# SINH BOI run_workspace/mcu/innovus/scripts/make_1x_lef.py sram - KHONG sua tay.
# = srambank_128x4x20_6t122.lef.4x.fixed.lef chia 4 (ban 4x da chay sach DRC).
VERSION 5.8 ;
BUSBITCHARS "[]" ; 
DIVIDERCHAR "/" ; 


PROPERTYDEFINITIONS 
  MACRO CatenaDesignType STRING ; 
END PROPERTYDEFINITIONS 


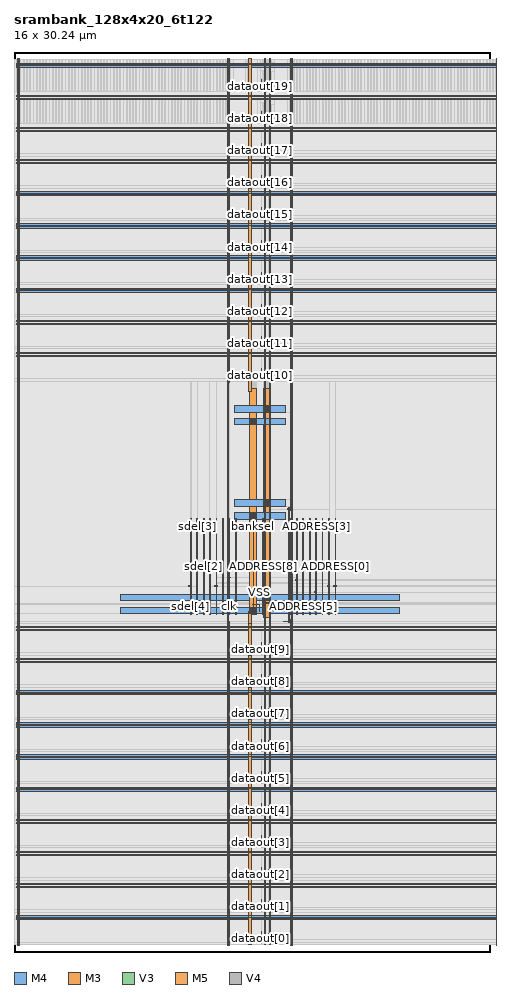
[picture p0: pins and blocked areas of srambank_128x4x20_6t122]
MACRO srambank_128x4x20_6t122 
  CLASS BLOCK ; 
  ORIGIN 0 0 ; 
  FOREIGN srambank_128x4x20_6t122 0 0 ; 
  SIZE 16 BY 30.24 ; 
  SYMMETRY X Y ; 
  SITE asap7sc7p5t ; 
  PIN VDD 
    DIRECTION INOUT ; 
    USE POWER ; 
    PORT 
      LAYER M4 ; 
        RECT 0.094 1.172 16.442 1.22 ; 
        RECT 0.094 2.252 16.442 2.3 ; 
        RECT 0.094 3.332 16.442 3.38 ; 
        RECT 0.094 4.412 16.442 4.46 ; 
        RECT 0.094 5.492 16.442 5.54 ; 
        RECT 0.094 6.572 16.442 6.62 ; 
        RECT 0.094 7.652 16.442 7.7 ; 
        RECT 0.094 8.732 16.442 8.78 ; 
        RECT 0.094 9.812 16.442 9.86 ; 
        RECT 0.094 10.892 16.442 10.94 ; 
        RECT 3.564 11.373 12.96 11.589 ; 
        RECT 9.197 14.877 9.338 14.901 ; 
        RECT 9.066 11.093 9.329 11.117 ; 
        RECT 7.398 14.541 9.126 14.757 ; 
        RECT 7.398 17.709 9.126 17.925 ; 
        RECT 0.094 20.099 16.442 20.147 ; 
        RECT 0.094 21.179 16.442 21.227 ; 
        RECT 0.094 22.259 16.442 22.307 ; 
        RECT 0.094 23.339 16.442 23.387 ; 
        RECT 0.094 24.419 16.442 24.467 ; 
        RECT 0.094 25.499 16.442 25.547 ; 
        RECT 0.094 26.579 16.442 26.627 ; 
        RECT 0.094 27.659 16.442 27.707 ; 
        RECT 0.094 28.739 16.442 28.787 ; 
        RECT 0.094 29.819 16.442 29.867 ; 
      LAYER M3 ; 
        RECT 16.394 0.217 16.412 1.377 ; 
        RECT 9.284 0.217 9.302 1.376 ; 
        RECT 7.88 0.257 7.97 1.371 ; 
        RECT 7.232 0.217 7.25 1.376 ; 
        RECT 0.122 0.217 0.14 1.377 ; 
        RECT 16.394 1.297 16.412 2.457 ; 
        RECT 9.284 1.297 9.302 2.456 ; 
        RECT 7.88 1.337 7.97 2.451 ; 
        RECT 7.232 1.297 7.25 2.456 ; 
        RECT 0.122 1.297 0.14 2.457 ; 
        RECT 16.394 2.377 16.412 3.537 ; 
        RECT 9.284 2.377 9.302 3.536 ; 
        RECT 7.88 2.417 7.97 3.531 ; 
        RECT 7.232 2.377 7.25 3.536 ; 
        RECT 0.122 2.377 0.14 3.537 ; 
        RECT 16.394 3.457 16.412 4.617 ; 
        RECT 9.284 3.457 9.302 4.616 ; 
        RECT 7.88 3.497 7.97 4.611 ; 
        RECT 7.232 3.457 7.25 4.616 ; 
        RECT 0.122 3.457 0.14 4.617 ; 
        RECT 16.394 4.537 16.412 5.697 ; 
        RECT 9.284 4.537 9.302 5.696 ; 
        RECT 7.88 4.577 7.97 5.691 ; 
        RECT 7.232 4.537 7.25 5.696 ; 
        RECT 0.122 4.537 0.14 5.697 ; 
        RECT 16.394 5.617 16.412 6.777 ; 
        RECT 9.284 5.617 9.302 6.776 ; 
        RECT 7.88 5.657 7.97 6.771 ; 
        RECT 7.232 5.617 7.25 6.776 ; 
        RECT 0.122 5.617 0.14 6.777 ; 
        RECT 16.394 6.697 16.412 7.857 ; 
        RECT 9.284 6.697 9.302 7.856 ; 
        RECT 7.88 6.737 7.97 7.851 ; 
        RECT 7.232 6.697 7.25 7.856 ; 
        RECT 0.122 6.697 0.14 7.857 ; 
        RECT 16.394 7.777 16.412 8.937 ; 
        RECT 9.284 7.777 9.302 8.936 ; 
        RECT 7.88 7.817 7.97 8.931 ; 
        RECT 7.232 7.777 7.25 8.936 ; 
        RECT 0.122 7.777 0.14 8.937 ; 
        RECT 16.394 8.857 16.412 10.017 ; 
        RECT 9.284 8.857 9.302 10.016 ; 
        RECT 7.88 8.897 7.97 10.011 ; 
        RECT 7.232 8.857 7.25 10.016 ; 
        RECT 0.122 8.857 0.14 10.017 ; 
        RECT 16.394 9.937 16.412 11.097 ; 
        RECT 9.284 9.937 9.302 11.096 ; 
        RECT 7.88 9.977 7.97 11.091 ; 
        RECT 7.232 9.937 7.25 11.096 ; 
        RECT 0.122 9.937 0.14 11.097 ; 
        RECT 16.389 11.011 16.407 19.218 ; 
        RECT 9.297 14.83 9.315 19.179 ; 
        RECT 9.279 11.044 9.297 11.182 ; 
        RECT 7.911 11.334 8.145 18.917 ; 
        RECT 7.875 18.834 7.965 19.21 ; 
        RECT 7.875 11.05 7.965 11.426 ; 
        RECT 0.117 11.011 0.135 19.218 ; 
        RECT 16.394 19.144 16.412 20.304 ; 
        RECT 9.284 19.144 9.302 20.303 ; 
        RECT 7.88 19.184 7.97 20.298 ; 
        RECT 7.232 19.144 7.25 20.303 ; 
        RECT 0.122 19.144 0.14 20.304 ; 
        RECT 16.394 20.224 16.412 21.384 ; 
        RECT 9.284 20.224 9.302 21.383 ; 
        RECT 7.88 20.264 7.97 21.378 ; 
        RECT 7.232 20.224 7.25 21.383 ; 
        RECT 0.122 20.224 0.14 21.384 ; 
        RECT 16.394 21.304 16.412 22.464 ; 
        RECT 9.284 21.304 9.302 22.463 ; 
        RECT 7.88 21.344 7.97 22.458 ; 
        RECT 7.232 21.304 7.25 22.463 ; 
        RECT 0.122 21.304 0.14 22.464 ; 
        RECT 16.394 22.384 16.412 23.544 ; 
        RECT 9.284 22.384 9.302 23.543 ; 
        RECT 7.88 22.424 7.97 23.538 ; 
        RECT 7.232 22.384 7.25 23.543 ; 
        RECT 0.122 22.384 0.14 23.544 ; 
        RECT 16.394 23.464 16.412 24.624 ; 
        RECT 9.284 23.464 9.302 24.623 ; 
        RECT 7.88 23.504 7.97 24.618 ; 
        RECT 7.232 23.464 7.25 24.623 ; 
        RECT 0.122 23.464 0.14 24.624 ; 
        RECT 16.394 24.544 16.412 25.704 ; 
        RECT 9.284 24.544 9.302 25.703 ; 
        RECT 7.88 24.584 7.97 25.698 ; 
        RECT 7.232 24.544 7.25 25.703 ; 
        RECT 0.122 24.544 0.14 25.704 ; 
        RECT 16.394 25.624 16.412 26.784 ; 
        RECT 9.284 25.624 9.302 26.783 ; 
        RECT 7.88 25.664 7.97 26.778 ; 
        RECT 7.232 25.624 7.25 26.783 ; 
        RECT 0.122 25.624 0.14 26.784 ; 
        RECT 16.394 26.704 16.412 27.864 ; 
        RECT 9.284 26.704 9.302 27.863 ; 
        RECT 7.88 26.744 7.97 27.858 ; 
        RECT 7.232 26.704 7.25 27.863 ; 
        RECT 0.122 26.704 0.14 27.864 ; 
        RECT 16.394 27.784 16.412 28.944 ; 
        RECT 9.284 27.784 9.302 28.943 ; 
        RECT 7.88 27.824 7.97 28.938 ; 
        RECT 7.232 27.784 7.25 28.943 ; 
        RECT 0.122 27.784 0.14 28.944 ; 
        RECT 16.394 28.864 16.412 30.024 ; 
        RECT 9.284 28.864 9.302 30.023 ; 
        RECT 7.88 28.904 7.97 30.018 ; 
        RECT 7.232 28.864 7.25 30.023 ; 
        RECT 0.122 28.864 0.14 30.024 ; 
      LAYER V3 ; 
        RECT 0.122 1.172 0.14 1.22 ; 
        RECT 7.232 1.172 7.25 1.22 ; 
        RECT 7.88 1.172 7.97 1.22 ; 
        RECT 9.284 1.172 9.302 1.22 ; 
        RECT 16.394 1.172 16.412 1.22 ; 
        RECT 0.122 2.252 0.14 2.3 ; 
        RECT 7.232 2.252 7.25 2.3 ; 
        RECT 7.88 2.252 7.97 2.3 ; 
        RECT 9.284 2.252 9.302 2.3 ; 
        RECT 16.394 2.252 16.412 2.3 ; 
        RECT 0.122 3.332 0.14 3.38 ; 
        RECT 7.232 3.332 7.25 3.38 ; 
        RECT 7.88 3.332 7.97 3.38 ; 
        RECT 9.284 3.332 9.302 3.38 ; 
        RECT 16.394 3.332 16.412 3.38 ; 
        RECT 0.122 4.412 0.14 4.46 ; 
        RECT 7.232 4.412 7.25 4.46 ; 
        RECT 7.88 4.412 7.97 4.46 ; 
        RECT 9.284 4.412 9.302 4.46 ; 
        RECT 16.394 4.412 16.412 4.46 ; 
        RECT 0.122 5.492 0.14 5.54 ; 
        RECT 7.232 5.492 7.25 5.54 ; 
        RECT 7.88 5.492 7.97 5.54 ; 
        RECT 9.284 5.492 9.302 5.54 ; 
        RECT 16.394 5.492 16.412 5.54 ; 
        RECT 0.122 6.572 0.14 6.62 ; 
        RECT 7.232 6.572 7.25 6.62 ; 
        RECT 7.88 6.572 7.97 6.62 ; 
        RECT 9.284 6.572 9.302 6.62 ; 
        RECT 16.394 6.572 16.412 6.62 ; 
        RECT 0.122 7.652 0.14 7.7 ; 
        RECT 7.232 7.652 7.25 7.7 ; 
        RECT 7.88 7.652 7.97 7.7 ; 
        RECT 9.284 7.652 9.302 7.7 ; 
        RECT 16.394 7.652 16.412 7.7 ; 
        RECT 0.122 8.732 0.14 8.78 ; 
        RECT 7.232 8.732 7.25 8.78 ; 
        RECT 7.88 8.732 7.97 8.78 ; 
        RECT 9.284 8.732 9.302 8.78 ; 
        RECT 16.394 8.732 16.412 8.78 ; 
        RECT 0.122 9.812 0.14 9.86 ; 
        RECT 7.232 9.812 7.25 9.86 ; 
        RECT 7.88 9.812 7.97 9.86 ; 
        RECT 9.284 9.812 9.302 9.86 ; 
        RECT 16.394 9.812 16.412 9.86 ; 
        RECT 0.122 10.892 0.14 10.94 ; 
        RECT 7.232 10.892 7.25 10.94 ; 
        RECT 7.88 10.892 7.97 10.94 ; 
        RECT 9.284 10.892 9.302 10.94 ; 
        RECT 16.394 10.892 16.412 10.94 ; 
        RECT 7.915 17.709 7.933 17.925 ; 
        RECT 7.915 14.541 7.933 14.757 ; 
        RECT 7.915 11.373 7.933 11.589 ; 
        RECT 7.967 17.709 7.985 17.925 ; 
        RECT 7.967 14.541 7.985 14.757 ; 
        RECT 7.967 11.373 7.985 11.589 ; 
        RECT 8.019 17.709 8.037 17.925 ; 
        RECT 8.019 14.541 8.037 14.757 ; 
        RECT 8.019 11.373 8.037 11.589 ; 
        RECT 8.071 17.709 8.089 17.925 ; 
        RECT 8.071 14.541 8.089 14.757 ; 
        RECT 8.071 11.373 8.089 11.589 ; 
        RECT 8.123 17.709 8.141 17.925 ; 
        RECT 8.123 14.541 8.141 14.757 ; 
        RECT 8.123 11.373 8.141 11.589 ; 
        RECT 9.279 11.093 9.297 11.117 ; 
        RECT 9.297 14.877 9.315 14.901 ; 
        RECT 0.122 20.099 0.14 20.147 ; 
        RECT 7.232 20.099 7.25 20.147 ; 
        RECT 7.88 20.099 7.97 20.147 ; 
        RECT 9.284 20.099 9.302 20.147 ; 
        RECT 16.394 20.099 16.412 20.147 ; 
        RECT 0.122 21.179 0.14 21.227 ; 
        RECT 7.232 21.179 7.25 21.227 ; 
        RECT 7.88 21.179 7.97 21.227 ; 
        RECT 9.284 21.179 9.302 21.227 ; 
        RECT 16.394 21.179 16.412 21.227 ; 
        RECT 0.122 22.259 0.14 22.307 ; 
        RECT 7.232 22.259 7.25 22.307 ; 
        RECT 7.88 22.259 7.97 22.307 ; 
        RECT 9.284 22.259 9.302 22.307 ; 
        RECT 16.394 22.259 16.412 22.307 ; 
        RECT 0.122 23.339 0.14 23.387 ; 
        RECT 7.232 23.339 7.25 23.387 ; 
        RECT 7.88 23.339 7.97 23.387 ; 
        RECT 9.284 23.339 9.302 23.387 ; 
        RECT 16.394 23.339 16.412 23.387 ; 
        RECT 0.122 24.419 0.14 24.467 ; 
        RECT 7.232 24.419 7.25 24.467 ; 
        RECT 7.88 24.419 7.97 24.467 ; 
        RECT 9.284 24.419 9.302 24.467 ; 
        RECT 16.394 24.419 16.412 24.467 ; 
        RECT 0.122 25.499 0.14 25.547 ; 
        RECT 7.232 25.499 7.25 25.547 ; 
        RECT 7.88 25.499 7.97 25.547 ; 
        RECT 9.284 25.499 9.302 25.547 ; 
        RECT 16.394 25.499 16.412 25.547 ; 
        RECT 0.122 26.579 0.14 26.627 ; 
        RECT 7.232 26.579 7.25 26.627 ; 
        RECT 7.88 26.579 7.97 26.627 ; 
        RECT 9.284 26.579 9.302 26.627 ; 
        RECT 16.394 26.579 16.412 26.627 ; 
        RECT 0.122 27.659 0.14 27.707 ; 
        RECT 7.232 27.659 7.25 27.707 ; 
        RECT 7.88 27.659 7.97 27.707 ; 
        RECT 9.284 27.659 9.302 27.707 ; 
        RECT 16.394 27.659 16.412 27.707 ; 
        RECT 0.122 28.739 0.14 28.787 ; 
        RECT 7.232 28.739 7.25 28.787 ; 
        RECT 7.88 28.739 7.97 28.787 ; 
        RECT 9.284 28.739 9.302 28.787 ; 
        RECT 16.394 28.739 16.412 28.787 ; 
        RECT 0.122 29.819 0.14 29.867 ; 
        RECT 7.232 29.819 7.25 29.867 ; 
        RECT 7.88 29.819 7.97 29.867 ; 
        RECT 9.284 29.819 9.302 29.867 ; 
        RECT 16.394 29.819 16.412 29.867 ; 
      LAYER M5 ; 
        RECT 9.216 11.075 9.24 14.919 ; 
      LAYER V4 ; 
        RECT 9.216 14.877 9.24 14.901 ; 
        RECT 9.216 11.373 9.24 11.589 ; 
        RECT 9.216 11.093 9.24 11.117 ; 
    END 
  END VDD 
  PIN VSS 
    DIRECTION INOUT ; 
    USE POWER ; 
    PORT 
      LAYER M4 ; 
        RECT 0.094 1.076 16.437 1.124 ; 
        RECT 0.094 2.156 16.437 2.204 ; 
        RECT 0.094 3.236 16.437 3.284 ; 
        RECT 0.094 4.316 16.437 4.364 ; 
        RECT 0.094 5.396 16.437 5.444 ; 
        RECT 0.094 6.476 16.437 6.524 ; 
        RECT 0.094 7.556 16.437 7.604 ; 
        RECT 0.094 8.636 16.437 8.684 ; 
        RECT 0.094 9.716 16.437 9.764 ; 
        RECT 0.094 10.796 16.437 10.844 ; 
        RECT 3.564 11.805 12.96 12.021 ; 
        RECT 7.398 14.973 9.126 15.189 ; 
        RECT 7.398 18.141 9.126 18.357 ; 
        RECT 0.094 20.003 16.437 20.051 ; 
        RECT 0.094 21.083 16.437 21.131 ; 
        RECT 0.094 22.163 16.437 22.211 ; 
        RECT 0.094 23.243 16.437 23.291 ; 
        RECT 0.094 24.323 16.437 24.371 ; 
        RECT 0.094 25.403 16.437 25.451 ; 
        RECT 0.094 26.483 16.437 26.531 ; 
        RECT 0.094 27.563 16.437 27.611 ; 
        RECT 0.094 28.643 16.437 28.691 ; 
        RECT 0.094 29.723 16.437 29.771 ; 
      LAYER M3 ; 
        RECT 16.358 0.217 16.376 1.377 ; 
        RECT 9.338 0.217 9.356 1.377 ; 
        RECT 8.573 0.253 8.609 1.367 ; 
        RECT 8.42 0.253 8.447 1.367 ; 
        RECT 7.178 0.217 7.196 1.377 ; 
        RECT 0.158 0.217 0.176 1.377 ; 
        RECT 16.358 1.297 16.376 2.457 ; 
        RECT 9.338 1.297 9.356 2.457 ; 
        RECT 8.573 1.333 8.609 2.447 ; 
        RECT 8.42 1.333 8.447 2.447 ; 
        RECT 7.178 1.297 7.196 2.457 ; 
        RECT 0.158 1.297 0.176 2.457 ; 
        RECT 16.358 2.377 16.376 3.537 ; 
        RECT 9.338 2.377 9.356 3.537 ; 
        RECT 8.573 2.413 8.609 3.527 ; 
        RECT 8.42 2.413 8.447 3.527 ; 
        RECT 7.178 2.377 7.196 3.537 ; 
        RECT 0.158 2.377 0.176 3.537 ; 
        RECT 16.358 3.457 16.376 4.617 ; 
        RECT 9.338 3.457 9.356 4.617 ; 
        RECT 8.573 3.493 8.609 4.607 ; 
        RECT 8.42 3.493 8.447 4.607 ; 
        RECT 7.178 3.457 7.196 4.617 ; 
        RECT 0.158 3.457 0.176 4.617 ; 
        RECT 16.358 4.537 16.376 5.697 ; 
        RECT 9.338 4.537 9.356 5.697 ; 
        RECT 8.573 4.573 8.609 5.687 ; 
        RECT 8.42 4.573 8.447 5.687 ; 
        RECT 7.178 4.537 7.196 5.697 ; 
        RECT 0.158 4.537 0.176 5.697 ; 
        RECT 16.358 5.617 16.376 6.777 ; 
        RECT 9.338 5.617 9.356 6.777 ; 
        RECT 8.573 5.653 8.609 6.767 ; 
        RECT 8.42 5.653 8.447 6.767 ; 
        RECT 7.178 5.617 7.196 6.777 ; 
        RECT 0.158 5.617 0.176 6.777 ; 
        RECT 16.358 6.697 16.376 7.857 ; 
        RECT 9.338 6.697 9.356 7.857 ; 
        RECT 8.573 6.733 8.609 7.847 ; 
        RECT 8.42 6.733 8.447 7.847 ; 
        RECT 7.178 6.697 7.196 7.857 ; 
        RECT 0.158 6.697 0.176 7.857 ; 
        RECT 16.358 7.777 16.376 8.937 ; 
        RECT 9.338 7.777 9.356 8.937 ; 
        RECT 8.573 7.813 8.609 8.927 ; 
        RECT 8.42 7.813 8.447 8.927 ; 
        RECT 7.178 7.777 7.196 8.937 ; 
        RECT 0.158 7.777 0.176 8.937 ; 
        RECT 16.358 8.857 16.376 10.017 ; 
        RECT 9.338 8.857 9.356 10.017 ; 
        RECT 8.573 8.893 8.609 10.007 ; 
        RECT 8.42 8.893 8.447 10.007 ; 
        RECT 7.178 8.857 7.196 10.017 ; 
        RECT 0.158 8.857 0.176 10.017 ; 
        RECT 16.358 9.937 16.376 11.097 ; 
        RECT 9.338 9.937 9.356 11.097 ; 
        RECT 8.573 9.973 8.609 11.087 ; 
        RECT 8.42 9.973 8.447 11.087 ; 
        RECT 7.178 9.937 7.196 11.097 ; 
        RECT 0.158 9.937 0.176 11.097 ; 
        RECT 16.353 11.011 16.371 19.218 ; 
        RECT 9.333 11.011 9.351 19.218 ; 
        RECT 8.379 11.234 8.613 18.917 ; 
        RECT 8.568 11.055 8.604 19.174 ; 
        RECT 8.415 11.054 8.442 19.174 ; 
        RECT 7.173 11.011 7.191 19.218 ; 
        RECT 0.153 11.011 0.171 19.218 ; 
        RECT 16.358 19.144 16.376 20.304 ; 
        RECT 9.338 19.144 9.356 20.304 ; 
        RECT 8.573 19.18 8.609 20.294 ; 
        RECT 8.42 19.18 8.447 20.294 ; 
        RECT 7.178 19.144 7.196 20.304 ; 
        RECT 0.158 19.144 0.176 20.304 ; 
        RECT 16.358 20.224 16.376 21.384 ; 
        RECT 9.338 20.224 9.356 21.384 ; 
        RECT 8.573 20.26 8.609 21.374 ; 
        RECT 8.42 20.26 8.447 21.374 ; 
        RECT 7.178 20.224 7.196 21.384 ; 
        RECT 0.158 20.224 0.176 21.384 ; 
        RECT 16.358 21.304 16.376 22.464 ; 
        RECT 9.338 21.304 9.356 22.464 ; 
        RECT 8.573 21.34 8.609 22.454 ; 
        RECT 8.42 21.34 8.447 22.454 ; 
        RECT 7.178 21.304 7.196 22.464 ; 
        RECT 0.158 21.304 0.176 22.464 ; 
        RECT 16.358 22.384 16.376 23.544 ; 
        RECT 9.338 22.384 9.356 23.544 ; 
        RECT 8.573 22.42 8.609 23.534 ; 
        RECT 8.42 22.42 8.447 23.534 ; 
        RECT 7.178 22.384 7.196 23.544 ; 
        RECT 0.158 22.384 0.176 23.544 ; 
        RECT 16.358 23.464 16.376 24.624 ; 
        RECT 9.338 23.464 9.356 24.624 ; 
        RECT 8.573 23.5 8.609 24.614 ; 
        RECT 8.42 23.5 8.447 24.614 ; 
        RECT 7.178 23.464 7.196 24.624 ; 
        RECT 0.158 23.464 0.176 24.624 ; 
        RECT 16.358 24.544 16.376 25.704 ; 
        RECT 9.338 24.544 9.356 25.704 ; 
        RECT 8.573 24.58 8.609 25.694 ; 
        RECT 8.42 24.58 8.447 25.694 ; 
        RECT 7.178 24.544 7.196 25.704 ; 
        RECT 0.158 24.544 0.176 25.704 ; 
        RECT 16.358 25.624 16.376 26.784 ; 
        RECT 9.338 25.624 9.356 26.784 ; 
        RECT 8.573 25.66 8.609 26.774 ; 
        RECT 8.42 25.66 8.447 26.774 ; 
        RECT 7.178 25.624 7.196 26.784 ; 
        RECT 0.158 25.624 0.176 26.784 ; 
        RECT 16.358 26.704 16.376 27.864 ; 
        RECT 9.338 26.704 9.356 27.864 ; 
        RECT 8.573 26.74 8.609 27.854 ; 
        RECT 8.42 26.74 8.447 27.854 ; 
        RECT 7.178 26.704 7.196 27.864 ; 
        RECT 0.158 26.704 0.176 27.864 ; 
        RECT 16.358 27.784 16.376 28.944 ; 
        RECT 9.338 27.784 9.356 28.944 ; 
        RECT 8.573 27.82 8.609 28.934 ; 
        RECT 8.42 27.82 8.447 28.934 ; 
        RECT 7.178 27.784 7.196 28.944 ; 
        RECT 0.158 27.784 0.176 28.944 ; 
        RECT 16.358 28.864 16.376 30.024 ; 
        RECT 9.338 28.864 9.356 30.024 ; 
        RECT 8.573 28.9 8.609 30.014 ; 
        RECT 8.42 28.9 8.447 30.014 ; 
        RECT 7.178 28.864 7.196 30.024 ; 
        RECT 0.158 28.864 0.176 30.024 ; 
      LAYER V3 ; 
        RECT 0.158 1.076 0.176 1.124 ; 
        RECT 7.178 1.076 7.196 1.124 ; 
        RECT 8.42 1.076 8.447 1.124 ; 
        RECT 8.573 1.076 8.609 1.124 ; 
        RECT 9.338 1.076 9.356 1.124 ; 
        RECT 16.358 1.076 16.376 1.124 ; 
        RECT 0.158 2.156 0.176 2.204 ; 
        RECT 7.178 2.156 7.196 2.204 ; 
        RECT 8.42 2.156 8.447 2.204 ; 
        RECT 8.573 2.156 8.609 2.204 ; 
        RECT 9.338 2.156 9.356 2.204 ; 
        RECT 16.358 2.156 16.376 2.204 ; 
        RECT 0.158 3.236 0.176 3.284 ; 
        RECT 7.178 3.236 7.196 3.284 ; 
        RECT 8.42 3.236 8.447 3.284 ; 
        RECT 8.573 3.236 8.609 3.284 ; 
        RECT 9.338 3.236 9.356 3.284 ; 
        RECT 16.358 3.236 16.376 3.284 ; 
        RECT 0.158 4.316 0.176 4.364 ; 
        RECT 7.178 4.316 7.196 4.364 ; 
        RECT 8.42 4.316 8.447 4.364 ; 
        RECT 8.573 4.316 8.609 4.364 ; 
        RECT 9.338 4.316 9.356 4.364 ; 
        RECT 16.358 4.316 16.376 4.364 ; 
        RECT 0.158 5.396 0.176 5.444 ; 
        RECT 7.178 5.396 7.196 5.444 ; 
        RECT 8.42 5.396 8.447 5.444 ; 
        RECT 8.573 5.396 8.609 5.444 ; 
        RECT 9.338 5.396 9.356 5.444 ; 
        RECT 16.358 5.396 16.376 5.444 ; 
        RECT 0.158 6.476 0.176 6.524 ; 
        RECT 7.178 6.476 7.196 6.524 ; 
        RECT 8.42 6.476 8.447 6.524 ; 
        RECT 8.573 6.476 8.609 6.524 ; 
        RECT 9.338 6.476 9.356 6.524 ; 
        RECT 16.358 6.476 16.376 6.524 ; 
        RECT 0.158 7.556 0.176 7.604 ; 
        RECT 7.178 7.556 7.196 7.604 ; 
        RECT 8.42 7.556 8.447 7.604 ; 
        RECT 8.573 7.556 8.609 7.604 ; 
        RECT 9.338 7.556 9.356 7.604 ; 
        RECT 16.358 7.556 16.376 7.604 ; 
        RECT 0.158 8.636 0.176 8.684 ; 
        RECT 7.178 8.636 7.196 8.684 ; 
        RECT 8.42 8.636 8.447 8.684 ; 
        RECT 8.573 8.636 8.609 8.684 ; 
        RECT 9.338 8.636 9.356 8.684 ; 
        RECT 16.358 8.636 16.376 8.684 ; 
        RECT 0.158 9.716 0.176 9.764 ; 
        RECT 7.178 9.716 7.196 9.764 ; 
        RECT 8.42 9.716 8.447 9.764 ; 
        RECT 8.573 9.716 8.609 9.764 ; 
        RECT 9.338 9.716 9.356 9.764 ; 
        RECT 16.358 9.716 16.376 9.764 ; 
        RECT 0.158 10.796 0.176 10.844 ; 
        RECT 7.178 10.796 7.196 10.844 ; 
        RECT 8.42 10.796 8.447 10.844 ; 
        RECT 8.573 10.796 8.609 10.844 ; 
        RECT 9.338 10.796 9.356 10.844 ; 
        RECT 16.358 10.796 16.376 10.844 ; 
        RECT 8.383 18.141 8.401 18.357 ; 
        RECT 8.383 14.973 8.401 15.189 ; 
        RECT 8.383 11.805 8.401 12.021 ; 
        RECT 8.435 18.141 8.453 18.357 ; 
        RECT 8.435 14.973 8.453 15.189 ; 
        RECT 8.435 11.805 8.453 12.021 ; 
        RECT 8.487 18.141 8.505 18.357 ; 
        RECT 8.487 14.973 8.505 15.189 ; 
        RECT 8.487 11.805 8.505 12.021 ; 
        RECT 8.539 18.141 8.557 18.357 ; 
        RECT 8.539 14.973 8.557 15.189 ; 
        RECT 8.539 11.805 8.557 12.021 ; 
        RECT 8.591 18.141 8.609 18.357 ; 
        RECT 8.591 14.973 8.609 15.189 ; 
        RECT 8.591 11.805 8.609 12.021 ; 
        RECT 9.333 11.806 9.351 12.022 ; 
        RECT 0.158 20.003 0.176 20.051 ; 
        RECT 7.178 20.003 7.196 20.051 ; 
        RECT 8.42 20.003 8.447 20.051 ; 
        RECT 8.573 20.003 8.609 20.051 ; 
        RECT 9.338 20.003 9.356 20.051 ; 
        RECT 16.358 20.003 16.376 20.051 ; 
        RECT 0.158 21.083 0.176 21.131 ; 
        RECT 7.178 21.083 7.196 21.131 ; 
        RECT 8.42 21.083 8.447 21.131 ; 
        RECT 8.573 21.083 8.609 21.131 ; 
        RECT 9.338 21.083 9.356 21.131 ; 
        RECT 16.358 21.083 16.376 21.131 ; 
        RECT 0.158 22.163 0.176 22.211 ; 
        RECT 7.178 22.163 7.196 22.211 ; 
        RECT 8.42 22.163 8.447 22.211 ; 
        RECT 8.573 22.163 8.609 22.211 ; 
        RECT 9.338 22.163 9.356 22.211 ; 
        RECT 16.358 22.163 16.376 22.211 ; 
        RECT 0.158 23.243 0.176 23.291 ; 
        RECT 7.178 23.243 7.196 23.291 ; 
        RECT 8.42 23.243 8.447 23.291 ; 
        RECT 8.573 23.243 8.609 23.291 ; 
        RECT 9.338 23.243 9.356 23.291 ; 
        RECT 16.358 23.243 16.376 23.291 ; 
        RECT 0.158 24.323 0.176 24.371 ; 
        RECT 7.178 24.323 7.196 24.371 ; 
        RECT 8.42 24.323 8.447 24.371 ; 
        RECT 8.573 24.323 8.609 24.371 ; 
        RECT 9.338 24.323 9.356 24.371 ; 
        RECT 16.358 24.323 16.376 24.371 ; 
        RECT 0.158 25.403 0.176 25.451 ; 
        RECT 7.178 25.403 7.196 25.451 ; 
        RECT 8.42 25.403 8.447 25.451 ; 
        RECT 8.573 25.403 8.609 25.451 ; 
        RECT 9.338 25.403 9.356 25.451 ; 
        RECT 16.358 25.403 16.376 25.451 ; 
        RECT 0.158 26.483 0.176 26.531 ; 
        RECT 7.178 26.483 7.196 26.531 ; 
        RECT 8.42 26.483 8.447 26.531 ; 
        RECT 8.573 26.483 8.609 26.531 ; 
        RECT 9.338 26.483 9.356 26.531 ; 
        RECT 16.358 26.483 16.376 26.531 ; 
        RECT 0.158 27.563 0.176 27.611 ; 
        RECT 7.178 27.563 7.196 27.611 ; 
        RECT 8.42 27.563 8.447 27.611 ; 
        RECT 8.573 27.563 8.609 27.611 ; 
        RECT 9.338 27.563 9.356 27.611 ; 
        RECT 16.358 27.563 16.376 27.611 ; 
        RECT 0.158 28.643 0.176 28.691 ; 
        RECT 7.178 28.643 7.196 28.691 ; 
        RECT 8.42 28.643 8.447 28.691 ; 
        RECT 8.573 28.643 8.609 28.691 ; 
        RECT 9.338 28.643 9.356 28.691 ; 
        RECT 16.358 28.643 16.376 28.691 ; 
        RECT 0.158 29.723 0.176 29.771 ; 
        RECT 7.178 29.723 7.196 29.771 ; 
        RECT 8.42 29.723 8.447 29.771 ; 
        RECT 8.573 29.723 8.609 29.771 ; 
        RECT 9.338 29.723 9.356 29.771 ; 
        RECT 16.358 29.723 16.376 29.771 ; 
    END 
  END VSS 
  PIN ADDRESS[0] 
    DIRECTION INPUT ; 
    USE SIGNAL ; 
    PORT 
      LAYER M3 ; 
        RECT 10.791 12.277 10.809 12.314 ; 
      LAYER M4 ; 
        RECT 10.739 12.285 10.823 12.309 ; 
      LAYER M5 ; 
        RECT 10.788 11.334 10.812 14.574 ; 
      LAYER V3 ; 
        RECT 10.791 12.285 10.809 12.309 ; 
      LAYER V4 ; 
        RECT 10.788 12.285 10.812 12.309 ; 
    END 
  END ADDRESS[0] 
  PIN ADDRESS[1] 
    DIRECTION INPUT ; 
    USE SIGNAL ; 
    PORT 
      LAYER M3 ; 
        RECT 10.575 12.28 10.593 12.317 ; 
      LAYER M4 ; 
        RECT 10.523 12.285 10.607 12.309 ; 
      LAYER M5 ; 
        RECT 10.572 11.334 10.596 14.574 ; 
      LAYER V3 ; 
        RECT 10.575 12.285 10.593 12.309 ; 
      LAYER V4 ; 
        RECT 10.572 12.285 10.596 12.309 ; 
    END 
  END ADDRESS[1] 
  PIN ADDRESS[2] 
    DIRECTION INPUT ; 
    USE SIGNAL ; 
    PORT 
      LAYER M3 ; 
        RECT 10.359 11.701 10.377 11.738 ; 
      LAYER M4 ; 
        RECT 10.307 11.709 10.391 11.733 ; 
      LAYER M5 ; 
        RECT 10.356 11.334 10.38 14.574 ; 
      LAYER V3 ; 
        RECT 10.359 11.709 10.377 11.733 ; 
      LAYER V4 ; 
        RECT 10.356 11.709 10.38 11.733 ; 
    END 
  END ADDRESS[2] 
  PIN ADDRESS[3] 
    DIRECTION INPUT ; 
    USE SIGNAL ; 
    PORT 
      LAYER M3 ; 
        RECT 10.143 11.941 10.161 12.122 ; 
      LAYER M4 ; 
        RECT 10.091 12.093 10.175 12.117 ; 
      LAYER M5 ; 
        RECT 10.14 11.334 10.164 14.574 ; 
      LAYER V3 ; 
        RECT 10.143 12.093 10.161 12.117 ; 
      LAYER V4 ; 
        RECT 10.14 12.093 10.164 12.117 ; 
    END 
  END ADDRESS[3] 
  PIN ADDRESS[4] 
    DIRECTION INPUT ; 
    USE SIGNAL ; 
    PORT 
      LAYER M3 ; 
        RECT 9.927 11.704 9.945 11.771 ; 
      LAYER M4 ; 
        RECT 9.875 11.709 9.959 11.733 ; 
      LAYER M5 ; 
        RECT 9.924 11.334 9.948 14.574 ; 
      LAYER V3 ; 
        RECT 9.927 11.709 9.945 11.733 ; 
      LAYER V4 ; 
        RECT 9.924 11.709 9.948 11.733 ; 
    END 
  END ADDRESS[4] 
  PIN ADDRESS[5] 
    DIRECTION INPUT ; 
    USE SIGNAL ; 
    PORT 
      LAYER M3 ; 
        RECT 9.711 11.437 9.729 11.69 ; 
      LAYER M4 ; 
        RECT 9.659 11.661 9.743 11.685 ; 
      LAYER M5 ; 
        RECT 9.708 11.334 9.732 14.574 ; 
      LAYER V3 ; 
        RECT 9.711 11.661 9.729 11.685 ; 
      LAYER V4 ; 
        RECT 9.708 11.661 9.732 11.685 ; 
    END 
  END ADDRESS[5] 
  PIN ADDRESS[6] 
    DIRECTION INPUT ; 
    USE SIGNAL ; 
    PORT 
      LAYER M3 ; 
        RECT 9.495 12.472 9.513 12.509 ; 
      LAYER M4 ; 
        RECT 9.443 12.477 9.527 12.501 ; 
      LAYER M5 ; 
        RECT 9.492 11.334 9.516 14.574 ; 
      LAYER V3 ; 
        RECT 9.495 12.477 9.513 12.501 ; 
      LAYER V4 ; 
        RECT 9.492 12.477 9.516 12.501 ; 
    END 
  END ADDRESS[6] 
  PIN ADDRESS[7] 
    DIRECTION INPUT ; 
    USE SIGNAL ; 
    PORT 
      LAYER M3 ; 
        RECT 9.279 12.319 9.297 12.41 ; 
      LAYER M4 ; 
        RECT 9.227 12.381 9.311 12.405 ; 
      LAYER M5 ; 
        RECT 9.276 11.334 9.3 14.574 ; 
      LAYER V3 ; 
        RECT 9.279 12.381 9.297 12.405 ; 
      LAYER V4 ; 
        RECT 9.276 12.381 9.3 12.405 ; 
    END 
  END ADDRESS[7] 
  PIN ADDRESS[8] 
    DIRECTION INPUT ; 
    USE SIGNAL ; 
    PORT 
      LAYER M3 ; 
        RECT 8.631 11.704 8.649 11.771 ; 
      LAYER M4 ; 
        RECT 8.347 11.709 8.66 11.733 ; 
      LAYER M5 ; 
        RECT 8.358 11.334 8.382 14.574 ; 
      LAYER V3 ; 
        RECT 8.631 11.709 8.649 11.733 ; 
      LAYER V4 ; 
        RECT 8.358 11.709 8.382 11.733 ; 
    END 
  END ADDRESS[8] 
  PIN banksel 
    DIRECTION INPUT ; 
    USE SIGNAL ; 
    PORT 
      LAYER M3 ; 
        RECT 8.235 11.437 8.253 11.69 ; 
      LAYER M4 ; 
        RECT 8.023 11.661 8.264 11.685 ; 
      LAYER M5 ; 
        RECT 8.034 11.334 8.058 14.574 ; 
      LAYER V3 ; 
        RECT 8.235 11.661 8.253 11.685 ; 
      LAYER V4 ; 
        RECT 8.034 11.661 8.058 11.685 ; 
    END 
  END banksel 
  PIN write 
    DIRECTION INPUT ; 
    USE SIGNAL ; 
    PORT 
      LAYER M3 ; 
        RECT 7.443 11.704 7.461 11.771 ; 
      LAYER M4 ; 
        RECT 7.391 11.709 7.475 11.733 ; 
      LAYER M5 ; 
        RECT 7.44 11.334 7.464 14.574 ; 
      LAYER V3 ; 
        RECT 7.443 11.709 7.461 11.733 ; 
      LAYER V4 ; 
        RECT 7.44 11.709 7.464 11.733 ; 
    END 
  END write 
  PIN clk 
    DIRECTION INPUT ; 
    USE SIGNAL ; 
    PORT 
      LAYER M3 ; 
        RECT 7.227 12.568 7.245 12.617 ; 
      LAYER M4 ; 
        RECT 7.175 12.573 7.259 12.597 ; 
      LAYER M5 ; 
        RECT 7.224 11.334 7.248 14.574 ; 
      LAYER V3 ; 
        RECT 7.227 12.573 7.245 12.597 ; 
      LAYER V4 ; 
        RECT 7.224 12.573 7.248 12.597 ; 
    END 
  END clk 
  PIN read 
    DIRECTION INPUT ; 
    USE SIGNAL ; 
    PORT 
      LAYER M3 ; 
        RECT 7.263 11.437 7.281 11.69 ; 
      LAYER M4 ; 
        RECT 6.997 11.661 7.292 11.685 ; 
      LAYER M5 ; 
        RECT 7.008 11.334 7.032 14.574 ; 
      LAYER V3 ; 
        RECT 7.263 11.661 7.281 11.685 ; 
      LAYER V4 ; 
        RECT 7.008 11.661 7.032 11.685 ; 
    END 
  END read 
  PIN sdel[0] 
    DIRECTION INPUT ; 
    USE SIGNAL ; 
    PORT 
      LAYER M3 ; 
        RECT 6.795 12.277 6.813 12.314 ; 
      LAYER M4 ; 
        RECT 6.743 12.285 6.827 12.309 ; 
      LAYER M5 ; 
        RECT 6.792 11.334 6.816 14.574 ; 
      LAYER V3 ; 
        RECT 6.795 12.285 6.813 12.309 ; 
      LAYER V4 ; 
        RECT 6.792 12.285 6.816 12.309 ; 
    END 
  END sdel[0] 
  PIN sdel[1] 
    DIRECTION INPUT ; 
    USE SIGNAL ; 
    PORT 
      LAYER M3 ; 
        RECT 6.579 11.704 6.597 11.933 ; 
      LAYER M4 ; 
        RECT 6.527 11.709 6.611 11.733 ; 
      LAYER M5 ; 
        RECT 6.576 11.334 6.6 14.574 ; 
      LAYER V3 ; 
        RECT 6.579 11.709 6.597 11.733 ; 
      LAYER V4 ; 
        RECT 6.576 11.709 6.6 11.733 ; 
    END 
  END sdel[1] 
  PIN sdel[2] 
    DIRECTION INPUT ; 
    USE SIGNAL ; 
    PORT 
      LAYER M3 ; 
        RECT 6.363 11.437 6.381 11.69 ; 
      LAYER M4 ; 
        RECT 6.311 11.661 6.395 11.685 ; 
      LAYER M5 ; 
        RECT 6.36 11.334 6.384 14.574 ; 
      LAYER V3 ; 
        RECT 6.363 11.661 6.381 11.685 ; 
      LAYER V4 ; 
        RECT 6.36 11.661 6.384 11.685 ; 
    END 
  END sdel[2] 
  PIN sdel[3] 
    DIRECTION INPUT ; 
    USE SIGNAL ; 
    PORT 
      LAYER M3 ; 
        RECT 6.147 11.701 6.165 11.738 ; 
      LAYER M4 ; 
        RECT 6.095 11.709 6.179 11.733 ; 
      LAYER M5 ; 
        RECT 6.144 11.334 6.168 14.574 ; 
      LAYER V3 ; 
        RECT 6.147 11.709 6.165 11.733 ; 
      LAYER V4 ; 
        RECT 6.144 11.709 6.168 11.733 ; 
    END 
  END sdel[3] 
  PIN sdel[4] 
    DIRECTION INPUT ; 
    USE SIGNAL ; 
    PORT 
      LAYER M3 ; 
        RECT 5.931 12.277 5.949 12.314 ; 
      LAYER M4 ; 
        RECT 5.879 12.285 5.963 12.309 ; 
      LAYER M5 ; 
        RECT 5.928 11.334 5.952 14.574 ; 
      LAYER V3 ; 
        RECT 5.931 12.285 5.949 12.309 ; 
      LAYER V4 ; 
        RECT 5.928 12.285 5.952 12.309 ; 
    END 
  END sdel[4] 
  PIN dataout[0] 
    DIRECTION OUTPUT ; 
    USE SIGNAL ; 
    PORT 
      LAYER M4 ; 
        RECT 7.949 0.428 8.597 0.452 ; 
      LAYER M3 ; 
        RECT 8.537 0.378 8.555 0.617 ; 
      LAYER V3 ; 
        RECT 8.537 0.428 8.555 0.452 ; 
    END 
  END dataout[0] 
  PIN wd[0] 
    DIRECTION INPUT ; 
    USE SIGNAL ; 
    PORT 
      LAYER M4 ; 
        RECT 7.949 0.332 8.665 0.356 ; 
      LAYER M3 ; 
        RECT 8.312 0.27 8.33 0.675 ; 
      LAYER V3 ; 
        RECT 8.312 0.332 8.33 0.356 ; 
    END 
  END wd[0] 
  PIN dataout[1] 
    DIRECTION OUTPUT ; 
    USE SIGNAL ; 
    PORT 
      LAYER M4 ; 
        RECT 7.949 1.508 8.597 1.532 ; 
      LAYER M3 ; 
        RECT 8.537 1.458 8.555 1.697 ; 
      LAYER V3 ; 
        RECT 8.537 1.508 8.555 1.532 ; 
    END 
  END dataout[1] 
  PIN wd[1] 
    DIRECTION INPUT ; 
    USE SIGNAL ; 
    PORT 
      LAYER M4 ; 
        RECT 7.949 1.412 8.665 1.436 ; 
      LAYER M3 ; 
        RECT 8.312 1.35 8.33 1.755 ; 
      LAYER V3 ; 
        RECT 8.312 1.412 8.33 1.436 ; 
    END 
  END wd[1] 
  PIN dataout[2] 
    DIRECTION OUTPUT ; 
    USE SIGNAL ; 
    PORT 
      LAYER M4 ; 
        RECT 7.949 2.588 8.597 2.612 ; 
      LAYER M3 ; 
        RECT 8.537 2.538 8.555 2.777 ; 
      LAYER V3 ; 
        RECT 8.537 2.588 8.555 2.612 ; 
    END 
  END dataout[2] 
  PIN wd[2] 
    DIRECTION INPUT ; 
    USE SIGNAL ; 
    PORT 
      LAYER M4 ; 
        RECT 7.949 2.492 8.665 2.516 ; 
      LAYER M3 ; 
        RECT 8.312 2.43 8.33 2.835 ; 
      LAYER V3 ; 
        RECT 8.312 2.492 8.33 2.516 ; 
    END 
  END wd[2] 
  PIN dataout[3] 
    DIRECTION OUTPUT ; 
    USE SIGNAL ; 
    PORT 
      LAYER M4 ; 
        RECT 7.949 3.668 8.597 3.692 ; 
      LAYER M3 ; 
        RECT 8.537 3.618 8.555 3.857 ; 
      LAYER V3 ; 
        RECT 8.537 3.668 8.555 3.692 ; 
    END 
  END dataout[3] 
  PIN wd[3] 
    DIRECTION INPUT ; 
    USE SIGNAL ; 
    PORT 
      LAYER M4 ; 
        RECT 7.949 3.572 8.665 3.596 ; 
      LAYER M3 ; 
        RECT 8.312 3.51 8.33 3.915 ; 
      LAYER V3 ; 
        RECT 8.312 3.572 8.33 3.596 ; 
    END 
  END wd[3] 
  PIN dataout[4] 
    DIRECTION OUTPUT ; 
    USE SIGNAL ; 
    PORT 
      LAYER M4 ; 
        RECT 7.949 4.748 8.597 4.772 ; 
      LAYER M3 ; 
        RECT 8.537 4.698 8.555 4.937 ; 
      LAYER V3 ; 
        RECT 8.537 4.748 8.555 4.772 ; 
    END 
  END dataout[4] 
  PIN wd[4] 
    DIRECTION INPUT ; 
    USE SIGNAL ; 
    PORT 
      LAYER M4 ; 
        RECT 7.949 4.652 8.665 4.676 ; 
      LAYER M3 ; 
        RECT 8.312 4.59 8.33 4.995 ; 
      LAYER V3 ; 
        RECT 8.312 4.652 8.33 4.676 ; 
    END 
  END wd[4] 
  PIN dataout[5] 
    DIRECTION OUTPUT ; 
    USE SIGNAL ; 
    PORT 
      LAYER M4 ; 
        RECT 7.949 5.828 8.597 5.852 ; 
      LAYER M3 ; 
        RECT 8.537 5.778 8.555 6.017 ; 
      LAYER V3 ; 
        RECT 8.537 5.828 8.555 5.852 ; 
    END 
  END dataout[5] 
  PIN wd[5] 
    DIRECTION INPUT ; 
    USE SIGNAL ; 
    PORT 
      LAYER M4 ; 
        RECT 7.949 5.732 8.665 5.756 ; 
      LAYER M3 ; 
        RECT 8.312 5.67 8.33 6.075 ; 
      LAYER V3 ; 
        RECT 8.312 5.732 8.33 5.756 ; 
    END 
  END wd[5] 
  PIN dataout[6] 
    DIRECTION OUTPUT ; 
    USE SIGNAL ; 
    PORT 
      LAYER M4 ; 
        RECT 7.949 6.908 8.597 6.932 ; 
      LAYER M3 ; 
        RECT 8.537 6.858 8.555 7.097 ; 
      LAYER V3 ; 
        RECT 8.537 6.908 8.555 6.932 ; 
    END 
  END dataout[6] 
  PIN wd[6] 
    DIRECTION INPUT ; 
    USE SIGNAL ; 
    PORT 
      LAYER M4 ; 
        RECT 7.949 6.812 8.665 6.836 ; 
      LAYER M3 ; 
        RECT 8.312 6.75 8.33 7.155 ; 
      LAYER V3 ; 
        RECT 8.312 6.812 8.33 6.836 ; 
    END 
  END wd[6] 
  PIN dataout[7] 
    DIRECTION OUTPUT ; 
    USE SIGNAL ; 
    PORT 
      LAYER M4 ; 
        RECT 7.949 7.988 8.597 8.012 ; 
      LAYER M3 ; 
        RECT 8.537 7.938 8.555 8.177 ; 
      LAYER V3 ; 
        RECT 8.537 7.988 8.555 8.012 ; 
    END 
  END dataout[7] 
  PIN wd[7] 
    DIRECTION INPUT ; 
    USE SIGNAL ; 
    PORT 
      LAYER M4 ; 
        RECT 7.949 7.892 8.665 7.916 ; 
      LAYER M3 ; 
        RECT 8.312 7.83 8.33 8.235 ; 
      LAYER V3 ; 
        RECT 8.312 7.892 8.33 7.916 ; 
    END 
  END wd[7] 
  PIN dataout[8] 
    DIRECTION OUTPUT ; 
    USE SIGNAL ; 
    PORT 
      LAYER M4 ; 
        RECT 7.949 9.068 8.597 9.092 ; 
      LAYER M3 ; 
        RECT 8.537 9.018 8.555 9.257 ; 
      LAYER V3 ; 
        RECT 8.537 9.068 8.555 9.092 ; 
    END 
  END dataout[8] 
  PIN wd[8] 
    DIRECTION INPUT ; 
    USE SIGNAL ; 
    PORT 
      LAYER M4 ; 
        RECT 7.949 8.972 8.665 8.996 ; 
      LAYER M3 ; 
        RECT 8.312 8.91 8.33 9.315 ; 
      LAYER V3 ; 
        RECT 8.312 8.972 8.33 8.996 ; 
    END 
  END wd[8] 
  PIN dataout[9] 
    DIRECTION OUTPUT ; 
    USE SIGNAL ; 
    PORT 
      LAYER M4 ; 
        RECT 7.949 10.148 8.597 10.172 ; 
      LAYER M3 ; 
        RECT 8.537 10.098 8.555 10.337 ; 
      LAYER V3 ; 
        RECT 8.537 10.148 8.555 10.172 ; 
    END 
  END dataout[9] 
  PIN wd[9] 
    DIRECTION INPUT ; 
    USE SIGNAL ; 
    PORT 
      LAYER M4 ; 
        RECT 7.949 10.052 8.665 10.076 ; 
      LAYER M3 ; 
        RECT 8.312 9.99 8.33 10.395 ; 
      LAYER V3 ; 
        RECT 8.312 10.052 8.33 10.076 ; 
    END 
  END wd[9] 
  PIN dataout[10] 
    DIRECTION OUTPUT ; 
    USE SIGNAL ; 
    PORT 
      LAYER M4 ; 
        RECT 7.949 19.355 8.597 19.379 ; 
      LAYER M3 ; 
        RECT 8.537 19.305 8.555 19.544 ; 
      LAYER V3 ; 
        RECT 8.537 19.355 8.555 19.379 ; 
    END 
  END dataout[10] 
  PIN wd[10] 
    DIRECTION INPUT ; 
    USE SIGNAL ; 
    PORT 
      LAYER M4 ; 
        RECT 7.949 19.259 8.665 19.283 ; 
      LAYER M3 ; 
        RECT 8.312 19.197 8.33 19.602 ; 
      LAYER V3 ; 
        RECT 8.312 19.259 8.33 19.283 ; 
    END 
  END wd[10] 
  PIN dataout[11] 
    DIRECTION OUTPUT ; 
    USE SIGNAL ; 
    PORT 
      LAYER M4 ; 
        RECT 7.949 20.435 8.597 20.459 ; 
      LAYER M3 ; 
        RECT 8.537 20.385 8.555 20.624 ; 
      LAYER V3 ; 
        RECT 8.537 20.435 8.555 20.459 ; 
    END 
  END dataout[11] 
  PIN wd[11] 
    DIRECTION INPUT ; 
    USE SIGNAL ; 
    PORT 
      LAYER M4 ; 
        RECT 7.949 20.339 8.665 20.363 ; 
      LAYER M3 ; 
        RECT 8.312 20.277 8.33 20.682 ; 
      LAYER V3 ; 
        RECT 8.312 20.339 8.33 20.363 ; 
    END 
  END wd[11] 
  PIN dataout[12] 
    DIRECTION OUTPUT ; 
    USE SIGNAL ; 
    PORT 
      LAYER M4 ; 
        RECT 7.949 21.515 8.597 21.539 ; 
      LAYER M3 ; 
        RECT 8.537 21.465 8.555 21.704 ; 
      LAYER V3 ; 
        RECT 8.537 21.515 8.555 21.539 ; 
    END 
  END dataout[12] 
  PIN wd[12] 
    DIRECTION INPUT ; 
    USE SIGNAL ; 
    PORT 
      LAYER M4 ; 
        RECT 7.949 21.419 8.665 21.443 ; 
      LAYER M3 ; 
        RECT 8.312 21.357 8.33 21.762 ; 
      LAYER V3 ; 
        RECT 8.312 21.419 8.33 21.443 ; 
    END 
  END wd[12] 
  PIN dataout[13] 
    DIRECTION OUTPUT ; 
    USE SIGNAL ; 
    PORT 
      LAYER M4 ; 
        RECT 7.949 22.595 8.597 22.619 ; 
      LAYER M3 ; 
        RECT 8.537 22.545 8.555 22.784 ; 
      LAYER V3 ; 
        RECT 8.537 22.595 8.555 22.619 ; 
    END 
  END dataout[13] 
  PIN wd[13] 
    DIRECTION INPUT ; 
    USE SIGNAL ; 
    PORT 
      LAYER M4 ; 
        RECT 7.949 22.499 8.665 22.523 ; 
      LAYER M3 ; 
        RECT 8.312 22.437 8.33 22.842 ; 
      LAYER V3 ; 
        RECT 8.312 22.499 8.33 22.523 ; 
    END 
  END wd[13] 
  PIN dataout[14] 
    DIRECTION OUTPUT ; 
    USE SIGNAL ; 
    PORT 
      LAYER M4 ; 
        RECT 7.949 23.675 8.597 23.699 ; 
      LAYER M3 ; 
        RECT 8.537 23.625 8.555 23.864 ; 
      LAYER V3 ; 
        RECT 8.537 23.675 8.555 23.699 ; 
    END 
  END dataout[14] 
  PIN wd[14] 
    DIRECTION INPUT ; 
    USE SIGNAL ; 
    PORT 
      LAYER M4 ; 
        RECT 7.949 23.579 8.665 23.603 ; 
      LAYER M3 ; 
        RECT 8.312 23.517 8.33 23.922 ; 
      LAYER V3 ; 
        RECT 8.312 23.579 8.33 23.603 ; 
    END 
  END wd[14] 
  PIN dataout[15] 
    DIRECTION OUTPUT ; 
    USE SIGNAL ; 
    PORT 
      LAYER M4 ; 
        RECT 7.949 24.755 8.597 24.779 ; 
      LAYER M3 ; 
        RECT 8.537 24.705 8.555 24.944 ; 
      LAYER V3 ; 
        RECT 8.537 24.755 8.555 24.779 ; 
    END 
  END dataout[15] 
  PIN wd[15] 
    DIRECTION INPUT ; 
    USE SIGNAL ; 
    PORT 
      LAYER M4 ; 
        RECT 7.949 24.659 8.665 24.683 ; 
      LAYER M3 ; 
        RECT 8.312 24.597 8.33 25.002 ; 
      LAYER V3 ; 
        RECT 8.312 24.659 8.33 24.683 ; 
    END 
  END wd[15] 
  PIN dataout[16] 
    DIRECTION OUTPUT ; 
    USE SIGNAL ; 
    PORT 
      LAYER M4 ; 
        RECT 7.949 25.835 8.597 25.859 ; 
      LAYER M3 ; 
        RECT 8.537 25.785 8.555 26.024 ; 
      LAYER V3 ; 
        RECT 8.537 25.835 8.555 25.859 ; 
    END 
  END dataout[16] 
  PIN wd[16] 
    DIRECTION INPUT ; 
    USE SIGNAL ; 
    PORT 
      LAYER M4 ; 
        RECT 7.949 25.739 8.665 25.763 ; 
      LAYER M3 ; 
        RECT 8.312 25.677 8.33 26.082 ; 
      LAYER V3 ; 
        RECT 8.312 25.739 8.33 25.763 ; 
    END 
  END wd[16] 
  PIN dataout[17] 
    DIRECTION OUTPUT ; 
    USE SIGNAL ; 
    PORT 
      LAYER M4 ; 
        RECT 7.949 26.915 8.597 26.939 ; 
      LAYER M3 ; 
        RECT 8.537 26.865 8.555 27.104 ; 
      LAYER V3 ; 
        RECT 8.537 26.915 8.555 26.939 ; 
    END 
  END dataout[17] 
  PIN wd[17] 
    DIRECTION INPUT ; 
    USE SIGNAL ; 
    PORT 
      LAYER M4 ; 
        RECT 7.949 26.819 8.665 26.843 ; 
      LAYER M3 ; 
        RECT 8.312 26.757 8.33 27.162 ; 
      LAYER V3 ; 
        RECT 8.312 26.819 8.33 26.843 ; 
    END 
  END wd[17] 
  PIN dataout[18] 
    DIRECTION OUTPUT ; 
    USE SIGNAL ; 
    PORT 
      LAYER M4 ; 
        RECT 7.949 27.995 8.597 28.019 ; 
      LAYER M3 ; 
        RECT 8.537 27.945 8.555 28.184 ; 
      LAYER V3 ; 
        RECT 8.537 27.995 8.555 28.019 ; 
    END 
  END dataout[18] 
  PIN wd[18] 
    DIRECTION INPUT ; 
    USE SIGNAL ; 
    PORT 
      LAYER M4 ; 
        RECT 7.949 27.899 8.665 27.923 ; 
      LAYER M3 ; 
        RECT 8.312 27.837 8.33 28.242 ; 
      LAYER V3 ; 
        RECT 8.312 27.899 8.33 27.923 ; 
    END 
  END wd[18] 
  PIN dataout[19] 
    DIRECTION OUTPUT ; 
    USE SIGNAL ; 
    PORT 
      LAYER M4 ; 
        RECT 7.949 29.075 8.597 29.099 ; 
      LAYER M3 ; 
        RECT 8.537 29.025 8.555 29.264 ; 
      LAYER V3 ; 
        RECT 8.537 29.075 8.555 29.099 ; 
    END 
  END dataout[19] 
  PIN wd[19] 
    DIRECTION INPUT ; 
    USE SIGNAL ; 
    PORT 
      LAYER M4 ; 
        RECT 7.949 28.979 8.665 29.003 ; 
      LAYER M3 ; 
        RECT 8.312 28.917 8.33 29.322 ; 
      LAYER V3 ; 
        RECT 8.312 28.979 8.33 29.003 ; 
    END 
  END wd[19] 
OBS 
  LAYER M1 SPACING 0.072 ; 
      RECT 0.005 0.257 16.529 1.35 ; 
      RECT 0.005 1.337 16.529 2.43 ; 
      RECT 0.005 2.417 16.529 3.51 ; 
      RECT 0.005 3.497 16.529 4.59 ; 
      RECT 0.005 4.577 16.529 5.67 ; 
      RECT 0.005 5.657 16.529 6.75 ; 
      RECT 0.005 6.737 16.529 7.83 ; 
      RECT 0.005 7.817 16.529 8.91 ; 
      RECT 0.005 8.897 16.529 9.99 ; 
      RECT 0.005 9.977 16.529 11.07 ; 
      RECT 0 11.037 16.524 19.691 ; 
        RECT 0.005 19.184 16.529 20.277 ; 
        RECT 0.005 20.264 16.529 21.357 ; 
        RECT 0.005 21.344 16.529 22.437 ; 
        RECT 0.005 22.424 16.529 23.517 ; 
        RECT 0.005 23.504 16.529 24.597 ; 
        RECT 0.005 24.584 16.529 25.677 ; 
        RECT 0.005 25.664 16.529 26.757 ; 
        RECT 0.005 26.744 16.529 27.837 ; 
        RECT 0.005 27.824 16.529 28.917 ; 
        RECT 0.005 28.904 16.529 29.997 ; 
  LAYER M2 SPACING 0.072 ; 
      RECT 0.005 0.257 16.529 1.35 ; 
      RECT 0.005 1.337 16.529 2.43 ; 
      RECT 0.005 2.417 16.529 3.51 ; 
      RECT 0.005 3.497 16.529 4.59 ; 
      RECT 0.005 4.577 16.529 5.67 ; 
      RECT 0.005 5.657 16.529 6.75 ; 
      RECT 0.005 6.737 16.529 7.83 ; 
      RECT 0.005 7.817 16.529 8.91 ; 
      RECT 0.005 8.897 16.529 9.99 ; 
      RECT 0.005 9.977 16.529 11.07 ; 
      RECT 0 11.037 16.524 19.691 ; 
        RECT 0.005 19.184 16.529 20.277 ; 
        RECT 0.005 20.264 16.529 21.357 ; 
        RECT 0.005 21.344 16.529 22.437 ; 
        RECT 0.005 22.424 16.529 23.517 ; 
        RECT 0.005 23.504 16.529 24.597 ; 
        RECT 0.005 24.584 16.529 25.677 ; 
        RECT 0.005 25.664 16.529 26.757 ; 
        RECT 0.005 26.744 16.529 27.837 ; 
        RECT 0.005 27.824 16.529 28.917 ; 
        RECT 0.005 28.904 16.529 29.997 ; 
  LAYER V1 SPACING 0.072 ; 
      RECT 0.005 0.257 16.529 1.35 ; 
      RECT 0.005 1.337 16.529 2.43 ; 
      RECT 0.005 2.417 16.529 3.51 ; 
      RECT 0.005 3.497 16.529 4.59 ; 
      RECT 0.005 4.577 16.529 5.67 ; 
      RECT 0.005 5.657 16.529 6.75 ; 
      RECT 0.005 6.737 16.529 7.83 ; 
      RECT 0.005 7.817 16.529 8.91 ; 
      RECT 0.005 8.897 16.529 9.99 ; 
      RECT 0.005 9.977 16.529 11.07 ; 
      RECT 0 11.037 16.524 19.691 ; 
        RECT 0.005 19.184 16.529 20.277 ; 
        RECT 0.005 20.264 16.529 21.357 ; 
        RECT 0.005 21.344 16.529 22.437 ; 
        RECT 0.005 22.424 16.529 23.517 ; 
        RECT 0.005 23.504 16.529 24.597 ; 
        RECT 0.005 24.584 16.529 25.677 ; 
        RECT 0.005 25.664 16.529 26.757 ; 
        RECT 0.005 26.744 16.529 27.837 ; 
        RECT 0.005 27.824 16.529 28.917 ; 
        RECT 0.005 28.904 16.529 29.997 ; 
  LAYER V2 SPACING 0.072 ; 
      RECT 0.005 0.257 16.529 1.35 ; 
      RECT 0.005 1.337 16.529 2.43 ; 
      RECT 0.005 2.417 16.529 3.51 ; 
      RECT 0.005 3.497 16.529 4.59 ; 
      RECT 0.005 4.577 16.529 5.67 ; 
      RECT 0.005 5.657 16.529 6.75 ; 
      RECT 0.005 6.737 16.529 7.83 ; 
      RECT 0.005 7.817 16.529 8.91 ; 
      RECT 0.005 8.897 16.529 9.99 ; 
      RECT 0.005 9.977 16.529 11.07 ; 
      RECT 0 11.037 16.524 19.691 ; 
        RECT 0.005 19.184 16.529 20.277 ; 
        RECT 0.005 20.264 16.529 21.357 ; 
        RECT 0.005 21.344 16.529 22.437 ; 
        RECT 0.005 22.424 16.529 23.517 ; 
        RECT 0.005 23.504 16.529 24.597 ; 
        RECT 0.005 24.584 16.529 25.677 ; 
        RECT 0.005 25.664 16.529 26.757 ; 
        RECT 0.005 26.744 16.529 27.837 ; 
        RECT 0.005 27.824 16.529 28.917 ; 
        RECT 0.005 28.904 16.529 29.997 ; 
  LAYER M3 ; 
      RECT 8.699 0.345 8.717 1.281 ; 
      RECT 8.663 0.345 8.681 1.281 ; 
      RECT 8.627 0.922 8.645 1.245 ; 
      RECT 8.51 1.119 8.528 1.229 ; 
      RECT 8.501 0.378 8.519 0.617 ; 
      RECT 8.465 0.959 8.483 1.112 ; 
      RECT 8.384 0.984 8.402 1.242 ; 
      RECT 7.844 0.345 7.862 1.281 ; 
      RECT 7.808 0.345 7.826 1.281 ; 
      RECT 7.772 0.526 7.79 1.094 ; 
      RECT 8.699 1.425 8.717 2.361 ; 
      RECT 8.663 1.425 8.681 2.361 ; 
      RECT 8.627 2.002 8.645 2.325 ; 
      RECT 8.51 2.199 8.528 2.309 ; 
      RECT 8.501 1.458 8.519 1.697 ; 
      RECT 8.465 2.039 8.483 2.192 ; 
      RECT 8.384 2.064 8.402 2.322 ; 
      RECT 7.844 1.425 7.862 2.361 ; 
      RECT 7.808 1.425 7.826 2.361 ; 
      RECT 7.772 1.606 7.79 2.174 ; 
      RECT 8.699 2.505 8.717 3.441 ; 
      RECT 8.663 2.505 8.681 3.441 ; 
      RECT 8.627 3.082 8.645 3.405 ; 
      RECT 8.51 3.279 8.528 3.389 ; 
      RECT 8.501 2.538 8.519 2.777 ; 
      RECT 8.465 3.119 8.483 3.272 ; 
      RECT 8.384 3.144 8.402 3.402 ; 
      RECT 7.844 2.505 7.862 3.441 ; 
      RECT 7.808 2.505 7.826 3.441 ; 
      RECT 7.772 2.686 7.79 3.254 ; 
      RECT 8.699 3.585 8.717 4.521 ; 
      RECT 8.663 3.585 8.681 4.521 ; 
      RECT 8.627 4.162 8.645 4.485 ; 
      RECT 8.51 4.359 8.528 4.469 ; 
      RECT 8.501 3.618 8.519 3.857 ; 
      RECT 8.465 4.199 8.483 4.352 ; 
      RECT 8.384 4.224 8.402 4.482 ; 
      RECT 7.844 3.585 7.862 4.521 ; 
      RECT 7.808 3.585 7.826 4.521 ; 
      RECT 7.772 3.766 7.79 4.334 ; 
      RECT 8.699 4.665 8.717 5.601 ; 
      RECT 8.663 4.665 8.681 5.601 ; 
      RECT 8.627 5.242 8.645 5.565 ; 
      RECT 8.51 5.439 8.528 5.549 ; 
      RECT 8.501 4.698 8.519 4.937 ; 
      RECT 8.465 5.279 8.483 5.432 ; 
      RECT 8.384 5.304 8.402 5.562 ; 
      RECT 7.844 4.665 7.862 5.601 ; 
      RECT 7.808 4.665 7.826 5.601 ; 
      RECT 7.772 4.846 7.79 5.414 ; 
      RECT 8.699 5.745 8.717 6.681 ; 
      RECT 8.663 5.745 8.681 6.681 ; 
      RECT 8.627 6.322 8.645 6.645 ; 
      RECT 8.51 6.519 8.528 6.629 ; 
      RECT 8.501 5.778 8.519 6.017 ; 
      RECT 8.465 6.359 8.483 6.512 ; 
      RECT 8.384 6.384 8.402 6.642 ; 
      RECT 7.844 5.745 7.862 6.681 ; 
      RECT 7.808 5.745 7.826 6.681 ; 
      RECT 7.772 5.926 7.79 6.494 ; 
      RECT 8.699 6.825 8.717 7.761 ; 
      RECT 8.663 6.825 8.681 7.761 ; 
      RECT 8.627 7.402 8.645 7.725 ; 
      RECT 8.51 7.599 8.528 7.709 ; 
      RECT 8.501 6.858 8.519 7.097 ; 
      RECT 8.465 7.439 8.483 7.592 ; 
      RECT 8.384 7.464 8.402 7.722 ; 
      RECT 7.844 6.825 7.862 7.761 ; 
      RECT 7.808 6.825 7.826 7.761 ; 
      RECT 7.772 7.006 7.79 7.574 ; 
      RECT 8.699 7.905 8.717 8.841 ; 
      RECT 8.663 7.905 8.681 8.841 ; 
      RECT 8.627 8.482 8.645 8.805 ; 
      RECT 8.51 8.679 8.528 8.789 ; 
      RECT 8.501 7.938 8.519 8.177 ; 
      RECT 8.465 8.519 8.483 8.672 ; 
      RECT 8.384 8.544 8.402 8.802 ; 
      RECT 7.844 7.905 7.862 8.841 ; 
      RECT 7.808 7.905 7.826 8.841 ; 
      RECT 7.772 8.086 7.79 8.654 ; 
      RECT 8.699 8.985 8.717 9.921 ; 
      RECT 8.663 8.985 8.681 9.921 ; 
      RECT 8.627 9.562 8.645 9.885 ; 
      RECT 8.51 9.759 8.528 9.869 ; 
      RECT 8.501 9.018 8.519 9.257 ; 
      RECT 8.465 9.599 8.483 9.752 ; 
      RECT 8.384 9.624 8.402 9.882 ; 
      RECT 7.844 8.985 7.862 9.921 ; 
      RECT 7.808 8.985 7.826 9.921 ; 
      RECT 7.772 9.166 7.79 9.734 ; 
      RECT 8.699 10.065 8.717 11.001 ; 
      RECT 8.663 10.065 8.681 11.001 ; 
      RECT 8.627 10.642 8.645 10.965 ; 
      RECT 8.51 10.839 8.528 10.949 ; 
      RECT 8.501 10.098 8.519 10.337 ; 
      RECT 8.465 10.679 8.483 10.832 ; 
      RECT 8.384 10.704 8.402 10.962 ; 
      RECT 7.844 10.065 7.862 11.001 ; 
      RECT 7.808 10.065 7.826 11.001 ; 
      RECT 7.772 10.246 7.79 10.814 ; 
      RECT 16.317 14.83 16.335 19.184 ; 
      RECT 16.281 13.515 16.299 13.584 ; 
      RECT 16.281 15.135 16.299 15.218 ; 
      RECT 16.245 11.011 16.263 19.218 ; 
      RECT 16.209 14.863 16.227 15.553 ; 
      RECT 16.209 15.604 16.227 16.59 ; 
      RECT 16.209 16.63 16.227 17.247 ; 
      RECT 16.173 14.799 16.191 15.504 ; 
      RECT 16.173 16.257 16.191 17.427 ; 
      RECT 16.137 11.011 16.155 14.607 ; 
      RECT 16.029 11.011 16.047 14.607 ; 
      RECT 15.921 11.011 15.939 14.607 ; 
      RECT 15.813 11.011 15.831 14.607 ; 
      RECT 15.705 11.011 15.723 14.607 ; 
      RECT 15.597 11.011 15.615 14.607 ; 
      RECT 15.489 11.011 15.507 14.607 ; 
      RECT 15.381 11.011 15.399 14.607 ; 
      RECT 15.273 11.011 15.291 14.607 ; 
      RECT 15.165 11.011 15.183 14.607 ; 
      RECT 15.057 11.011 15.075 14.607 ; 
      RECT 14.949 11.011 14.967 14.607 ; 
      RECT 14.841 11.011 14.859 14.607 ; 
      RECT 14.733 11.011 14.751 14.607 ; 
      RECT 14.625 11.011 14.643 14.607 ; 
      RECT 14.517 11.011 14.535 14.607 ; 
      RECT 14.409 11.011 14.427 14.607 ; 
      RECT 14.301 11.011 14.319 14.607 ; 
      RECT 14.193 11.011 14.211 14.607 ; 
      RECT 14.085 11.011 14.103 14.607 ; 
      RECT 13.977 11.011 13.995 14.607 ; 
      RECT 13.869 11.011 13.887 14.607 ; 
      RECT 13.761 11.011 13.779 14.607 ; 
      RECT 13.653 11.011 13.671 14.607 ; 
      RECT 13.545 11.011 13.563 14.607 ; 
      RECT 13.437 11.011 13.455 14.607 ; 
      RECT 13.329 11.011 13.347 14.607 ; 
      RECT 13.221 11.011 13.239 14.607 ; 
      RECT 13.113 11.011 13.131 14.607 ; 
      RECT 13.005 11.011 13.023 14.607 ; 
      RECT 12.897 11.011 12.915 14.607 ; 
      RECT 12.789 11.011 12.807 14.607 ; 
      RECT 12.681 11.011 12.699 14.607 ; 
      RECT 12.573 11.011 12.591 14.607 ; 
      RECT 12.465 11.011 12.483 14.607 ; 
      RECT 12.357 11.011 12.375 14.607 ; 
      RECT 12.249 11.011 12.267 14.607 ; 
      RECT 12.141 11.011 12.159 14.607 ; 
      RECT 12.033 11.011 12.051 14.607 ; 
      RECT 11.925 11.011 11.943 14.607 ; 
      RECT 11.817 11.011 11.835 14.607 ; 
      RECT 11.709 11.011 11.727 14.607 ; 
      RECT 11.601 11.011 11.619 14.607 ; 
      RECT 11.493 11.011 11.511 14.607 ; 
      RECT 11.385 11.011 11.403 14.607 ; 
      RECT 11.277 11.011 11.295 14.607 ; 
      RECT 11.169 11.011 11.187 14.607 ; 
      RECT 11.061 11.011 11.079 14.607 ; 
      RECT 10.953 11.011 10.971 14.607 ; 
      RECT 10.845 11.011 10.863 14.607 ; 
      RECT 10.737 11.011 10.755 14.607 ; 
      RECT 10.629 11.011 10.647 14.607 ; 
      RECT 10.521 11.011 10.539 14.607 ; 
      RECT 10.413 11.011 10.431 14.607 ; 
      RECT 10.305 11.011 10.323 14.607 ; 
      RECT 10.197 11.011 10.215 14.607 ; 
      RECT 10.089 11.011 10.107 14.607 ; 
      RECT 9.981 11.011 9.999 14.607 ; 
      RECT 9.873 11.011 9.891 14.607 ; 
      RECT 9.765 11.011 9.783 14.607 ; 
      RECT 9.657 11.011 9.675 14.607 ; 
      RECT 9.549 11.011 9.567 14.607 ; 
      RECT 9.513 14.866 9.531 15.508 ; 
      RECT 9.513 16.185 9.531 16.717 ; 
      RECT 9.495 11.671 9.513 12.347 ; 
      RECT 9.495 13.093 9.513 13.391 ; 
      RECT 9.495 14.209 9.513 14.471 ; 
      RECT 9.477 14.78 9.495 15.553 ; 
      RECT 9.477 15.604 9.495 16.095 ; 
      RECT 9.477 16.14 9.495 16.511 ; 
      RECT 9.477 16.587 9.495 17.247 ; 
      RECT 9.441 11.011 9.459 19.218 ; 
      RECT 9.405 15.323 9.423 15.788 ; 
      RECT 9.387 11.779 9.405 12.41 ; 
      RECT 9.387 12.823 9.405 13.013 ; 
      RECT 9.387 13.705 9.405 13.754 ; 
      RECT 9.387 14.437 9.405 14.474 ; 
      RECT 9.369 14.83 9.387 19.18 ; 
      RECT 9.279 11.401 9.297 12.203 ; 
      RECT 9.279 12.751 9.297 13.319 ; 
      RECT 9.243 12.823 9.261 13.193 ; 
      RECT 9.207 12.175 9.225 12.311 ; 
      RECT 9.207 13.165 9.225 13.391 ; 
      RECT 9.207 14.407 9.225 14.471 ; 
      RECT 9.171 12.277 9.189 12.314 ; 
      RECT 9.171 13.903 9.189 13.946 ; 
      RECT 9.171 14.437 9.189 14.474 ; 
      RECT 9.135 12.589 9.153 13.085 ; 
      RECT 9.135 13.129 9.153 13.319 ; 
      RECT 9.135 14.089 9.153 14.399 ; 
      RECT 9.099 12.481 9.117 13.728 ; 
      RECT 9.099 16.369 9.117 17.099 ; 
      RECT 9.099 17.449 9.117 18.179 ; 
      RECT 8.775 12.211 8.793 12.509 ; 
      RECT 8.775 13.399 8.793 13.463 ; 
      RECT 8.775 13.669 8.793 14.129 ; 
      RECT 8.775 14.869 8.793 14.906 ; 
      RECT 8.775 16.909 8.793 17.207 ; 
      RECT 8.739 12.283 8.757 12.788 ; 
      RECT 8.739 13.057 8.757 13.859 ; 
      RECT 8.739 14.902 8.757 15.173 ; 
      RECT 8.739 15.253 8.757 15.479 ; 
      RECT 8.703 12.211 8.721 12.887 ; 
      RECT 8.703 12.985 8.721 13.319 ; 
      RECT 8.703 13.525 8.721 13.661 ; 
      RECT 8.703 14.209 8.721 15.011 ; 
      RECT 8.703 15.445 8.721 15.482 ; 
      RECT 8.703 17.611 8.721 17.945 ; 
      RECT 8.667 12.445 8.685 12.581 ; 
      RECT 8.667 14.335 8.685 15.317 ; 
      RECT 8.667 15.757 8.685 16.055 ; 
      RECT 8.667 17.449 8.685 17.711 ; 
      RECT 8.631 11.509 8.649 11.663 ; 
      RECT 8.631 12.319 8.649 14.105 ; 
      RECT 8.631 15.145 8.649 17.477 ; 
      RECT 8.631 17.683 8.649 18.791 ; 
      RECT 8.343 11.779 8.361 12.041 ; 
      RECT 8.343 12.175 8.361 12.239 ; 
      RECT 8.343 12.319 8.361 12.545 ; 
      RECT 8.343 12.589 8.361 12.779 ; 
      RECT 8.343 12.859 8.361 15.479 ; 
      RECT 8.343 15.523 8.361 16.829 ; 
      RECT 8.343 17.917 8.361 18.179 ; 
      RECT 8.307 12.778 8.325 13.049 ; 
      RECT 8.307 13.129 8.325 13.967 ; 
      RECT 8.307 14.137 8.325 14.975 ; 
      RECT 8.307 15.019 8.325 16.289 ; 
      RECT 8.307 16.495 8.325 16.667 ; 
      RECT 8.307 17.377 8.325 18.449 ; 
      RECT 8.271 12.859 8.289 13.13 ; 
      RECT 8.271 13.285 8.289 13.322 ; 
      RECT 8.271 14.065 8.289 15.047 ; 
      RECT 8.271 15.289 8.289 15.749 ; 
      RECT 8.271 16.099 8.289 16.838 ; 
      RECT 8.235 11.977 8.253 13.049 ; 
      RECT 8.235 14.641 8.253 14.858 ; 
      RECT 8.235 16.027 8.253 16.325 ; 
      RECT 8.199 12.625 8.217 13.085 ; 
      RECT 8.199 14.209 8.217 14.399 ; 
      RECT 8.199 14.44 8.217 14.477 ; 
      RECT 8.199 14.713 8.217 15.047 ; 
      RECT 8.199 15.181 8.217 16.523 ; 
      RECT 8.199 16.63 8.217 17.747 ; 
      RECT 8.163 12.049 8.181 12.239 ; 
      RECT 8.163 12.445 8.181 12.581 ; 
      RECT 8.163 12.859 8.181 16.019 ; 
      RECT 8.163 16.099 8.181 16.559 ; 
      RECT 8.163 17.179 8.181 17.639 ; 
      RECT 8.163 18.493 8.181 18.719 ; 
      RECT 8.127 11.037 8.145 11.191 ; 
      RECT 8.127 19.032 8.145 19.198 ; 
      RECT 8.091 11.037 8.109 11.087 ; 
      RECT 8.019 11.037 8.037 11.109 ; 
      RECT 8.019 19.102 8.037 19.218 ; 
      RECT 7.875 12.553 7.893 12.743 ; 
      RECT 7.875 13.291 7.893 13.661 ; 
      RECT 7.875 15.253 7.893 15.479 ; 
      RECT 7.875 15.793 7.893 16.937 ; 
      RECT 7.875 17.719 7.893 18.179 ; 
      RECT 7.875 18.757 7.893 18.794 ; 
      RECT 7.839 11.509 7.857 12.005 ; 
      RECT 7.839 15.589 7.857 15.626 ; 
      RECT 7.839 16.666 7.857 17.477 ; 
      RECT 7.803 11.977 7.821 12.239 ; 
      RECT 7.803 12.517 7.821 12.851 ; 
      RECT 7.803 13.057 7.821 13.157 ; 
      RECT 7.803 13.939 7.821 16.703 ; 
      RECT 7.803 16.837 7.821 17.063 ; 
      RECT 7.767 11.635 7.785 12.779 ; 
      RECT 7.767 16.369 7.785 16.559 ; 
      RECT 7.767 17.173 7.785 17.21 ; 
      RECT 7.767 17.449 7.785 18.251 ; 
      RECT 7.731 12.589 7.749 13.589 ; 
      RECT 7.731 17.029 7.749 17.066 ; 
      RECT 7.371 12.175 7.389 12.581 ; 
      RECT 7.299 12.211 7.317 12.815 ; 
      RECT 7.263 12.049 7.281 12.113 ; 
      RECT 7.227 11.09 7.245 11.141 ; 
      RECT 7.227 14.209 7.245 14.399 ; 
      RECT 7.209 14.83 7.227 19.179 ; 
      RECT 7.137 14.83 7.155 19.18 ; 
      RECT 7.119 11.509 7.137 11.699 ; 
      RECT 7.119 12.283 7.137 14.543 ; 
      RECT 7.101 15.323 7.119 15.788 ; 
      RECT 7.065 11.011 7.083 19.218 ; 
      RECT 7.029 14.78 7.047 15.553 ; 
      RECT 7.029 15.604 7.047 16.095 ; 
      RECT 7.029 16.14 7.047 16.511 ; 
      RECT 7.029 16.587 7.047 17.247 ; 
      RECT 7.011 11.509 7.029 12.005 ; 
      RECT 7.011 12.787 7.029 13.355 ; 
      RECT 7.011 13.669 7.029 14.399 ; 
      RECT 6.993 14.866 7.011 15.508 ; 
      RECT 6.993 16.185 7.011 16.717 ; 
      RECT 6.957 11.011 6.975 14.607 ; 
      RECT 6.849 11.011 6.867 14.607 ; 
      RECT 6.741 11.011 6.759 14.607 ; 
      RECT 6.633 11.011 6.651 14.607 ; 
      RECT 6.525 11.011 6.543 14.607 ; 
      RECT 6.417 11.011 6.435 14.607 ; 
      RECT 6.309 11.011 6.327 14.607 ; 
      RECT 6.201 11.011 6.219 14.607 ; 
      RECT 6.093 11.011 6.111 14.607 ; 
      RECT 5.985 11.011 6.003 14.607 ; 
      RECT 5.877 11.011 5.895 14.607 ; 
      RECT 5.769 11.011 5.787 14.607 ; 
      RECT 5.661 11.011 5.679 14.607 ; 
      RECT 5.553 11.011 5.571 14.607 ; 
      RECT 5.445 11.011 5.463 14.607 ; 
      RECT 5.337 11.011 5.355 14.607 ; 
      RECT 5.229 11.011 5.247 14.607 ; 
      RECT 5.121 11.011 5.139 14.607 ; 
      RECT 5.013 11.011 5.031 14.607 ; 
      RECT 4.905 11.011 4.923 14.607 ; 
      RECT 4.797 11.011 4.815 14.607 ; 
      RECT 4.689 11.011 4.707 14.607 ; 
      RECT 4.581 11.011 4.599 14.607 ; 
      RECT 4.473 11.011 4.491 14.607 ; 
      RECT 4.365 11.011 4.383 14.607 ; 
      RECT 4.257 11.011 4.275 14.607 ; 
      RECT 4.149 11.011 4.167 14.607 ; 
      RECT 4.041 11.011 4.059 14.607 ; 
      RECT 3.933 11.011 3.951 14.607 ; 
      RECT 3.825 11.011 3.843 14.607 ; 
      RECT 3.717 11.011 3.735 14.607 ; 
      RECT 3.609 11.011 3.627 14.607 ; 
      RECT 3.501 11.011 3.519 14.607 ; 
      RECT 3.393 11.011 3.411 14.607 ; 
      RECT 3.285 11.011 3.303 14.607 ; 
      RECT 3.177 11.011 3.195 14.607 ; 
      RECT 3.069 11.011 3.087 14.607 ; 
      RECT 2.961 11.011 2.979 14.607 ; 
      RECT 2.853 11.011 2.871 14.607 ; 
      RECT 2.745 11.011 2.763 14.607 ; 
      RECT 2.637 11.011 2.655 14.607 ; 
      RECT 2.529 11.011 2.547 14.607 ; 
      RECT 2.421 11.011 2.439 14.607 ; 
      RECT 2.313 11.011 2.331 14.607 ; 
      RECT 2.205 11.011 2.223 14.607 ; 
      RECT 2.097 11.011 2.115 14.607 ; 
      RECT 1.989 11.011 2.007 14.607 ; 
      RECT 1.881 11.011 1.899 14.607 ; 
      RECT 1.773 11.011 1.791 14.607 ; 
      RECT 1.665 11.011 1.683 14.607 ; 
      RECT 1.557 11.011 1.575 14.607 ; 
      RECT 1.449 11.011 1.467 14.607 ; 
      RECT 1.341 11.011 1.359 14.607 ; 
      RECT 1.233 11.011 1.251 14.607 ; 
      RECT 1.125 11.011 1.143 14.607 ; 
      RECT 1.017 11.011 1.035 14.607 ; 
      RECT 0.909 11.011 0.927 14.607 ; 
      RECT 0.801 11.011 0.819 14.607 ; 
      RECT 0.693 11.011 0.711 14.607 ; 
      RECT 0.585 11.011 0.603 14.607 ; 
      RECT 0.477 11.011 0.495 14.607 ; 
      RECT 0.369 11.011 0.387 14.607 ; 
      RECT 0.333 14.799 0.351 15.504 ; 
      RECT 0.333 16.257 0.351 17.427 ; 
      RECT 0.297 14.863 0.315 15.553 ; 
      RECT 0.297 15.604 0.315 16.59 ; 
      RECT 0.297 16.63 0.315 17.247 ; 
      RECT 0.261 11.011 0.279 19.218 ; 
      RECT 0.225 13.515 0.243 13.584 ; 
      RECT 0.225 15.135 0.243 15.218 ; 
      RECT 0.189 14.83 0.207 19.184 ; 
        RECT 8.699 19.272 8.717 20.208 ; 
        RECT 8.663 19.272 8.681 20.208 ; 
        RECT 8.627 19.849 8.645 20.172 ; 
        RECT 8.51 20.046 8.528 20.156 ; 
        RECT 8.501 19.305 8.519 19.544 ; 
        RECT 8.465 19.886 8.483 20.039 ; 
        RECT 8.384 19.911 8.402 20.169 ; 
        RECT 7.844 19.272 7.862 20.208 ; 
        RECT 7.808 19.272 7.826 20.208 ; 
        RECT 7.772 19.453 7.79 20.021 ; 
        RECT 8.699 20.352 8.717 21.288 ; 
        RECT 8.663 20.352 8.681 21.288 ; 
        RECT 8.627 20.929 8.645 21.252 ; 
        RECT 8.51 21.126 8.528 21.236 ; 
        RECT 8.501 20.385 8.519 20.624 ; 
        RECT 8.465 20.966 8.483 21.119 ; 
        RECT 8.384 20.991 8.402 21.249 ; 
        RECT 7.844 20.352 7.862 21.288 ; 
        RECT 7.808 20.352 7.826 21.288 ; 
        RECT 7.772 20.533 7.79 21.101 ; 
        RECT 8.699 21.432 8.717 22.368 ; 
        RECT 8.663 21.432 8.681 22.368 ; 
        RECT 8.627 22.009 8.645 22.332 ; 
        RECT 8.51 22.206 8.528 22.316 ; 
        RECT 8.501 21.465 8.519 21.704 ; 
        RECT 8.465 22.046 8.483 22.199 ; 
        RECT 8.384 22.071 8.402 22.329 ; 
        RECT 7.844 21.432 7.862 22.368 ; 
        RECT 7.808 21.432 7.826 22.368 ; 
        RECT 7.772 21.613 7.79 22.181 ; 
        RECT 8.699 22.512 8.717 23.448 ; 
        RECT 8.663 22.512 8.681 23.448 ; 
        RECT 8.627 23.089 8.645 23.412 ; 
        RECT 8.51 23.286 8.528 23.396 ; 
        RECT 8.501 22.545 8.519 22.784 ; 
        RECT 8.465 23.126 8.483 23.279 ; 
        RECT 8.384 23.151 8.402 23.409 ; 
        RECT 7.844 22.512 7.862 23.448 ; 
        RECT 7.808 22.512 7.826 23.448 ; 
        RECT 7.772 22.693 7.79 23.261 ; 
        RECT 8.699 23.592 8.717 24.528 ; 
        RECT 8.663 23.592 8.681 24.528 ; 
        RECT 8.627 24.169 8.645 24.492 ; 
        RECT 8.51 24.366 8.528 24.476 ; 
        RECT 8.501 23.625 8.519 23.864 ; 
        RECT 8.465 24.206 8.483 24.359 ; 
        RECT 8.384 24.231 8.402 24.489 ; 
        RECT 7.844 23.592 7.862 24.528 ; 
        RECT 7.808 23.592 7.826 24.528 ; 
        RECT 7.772 23.773 7.79 24.341 ; 
        RECT 8.699 24.672 8.717 25.608 ; 
        RECT 8.663 24.672 8.681 25.608 ; 
        RECT 8.627 25.249 8.645 25.572 ; 
        RECT 8.51 25.446 8.528 25.556 ; 
        RECT 8.501 24.705 8.519 24.944 ; 
        RECT 8.465 25.286 8.483 25.439 ; 
        RECT 8.384 25.311 8.402 25.569 ; 
        RECT 7.844 24.672 7.862 25.608 ; 
        RECT 7.808 24.672 7.826 25.608 ; 
        RECT 7.772 24.853 7.79 25.421 ; 
        RECT 8.699 25.752 8.717 26.688 ; 
        RECT 8.663 25.752 8.681 26.688 ; 
        RECT 8.627 26.329 8.645 26.652 ; 
        RECT 8.51 26.526 8.528 26.636 ; 
        RECT 8.501 25.785 8.519 26.024 ; 
        RECT 8.465 26.366 8.483 26.519 ; 
        RECT 8.384 26.391 8.402 26.649 ; 
        RECT 7.844 25.752 7.862 26.688 ; 
        RECT 7.808 25.752 7.826 26.688 ; 
        RECT 7.772 25.933 7.79 26.501 ; 
        RECT 8.699 26.832 8.717 27.768 ; 
        RECT 8.663 26.832 8.681 27.768 ; 
        RECT 8.627 27.409 8.645 27.732 ; 
        RECT 8.51 27.606 8.528 27.716 ; 
        RECT 8.501 26.865 8.519 27.104 ; 
        RECT 8.465 27.446 8.483 27.599 ; 
        RECT 8.384 27.471 8.402 27.729 ; 
        RECT 7.844 26.832 7.862 27.768 ; 
        RECT 7.808 26.832 7.826 27.768 ; 
        RECT 7.772 27.013 7.79 27.581 ; 
        RECT 8.699 27.912 8.717 28.848 ; 
        RECT 8.663 27.912 8.681 28.848 ; 
        RECT 8.627 28.489 8.645 28.812 ; 
        RECT 8.51 28.686 8.528 28.796 ; 
        RECT 8.501 27.945 8.519 28.184 ; 
        RECT 8.465 28.526 8.483 28.679 ; 
        RECT 8.384 28.551 8.402 28.809 ; 
        RECT 7.844 27.912 7.862 28.848 ; 
        RECT 7.808 27.912 7.826 28.848 ; 
        RECT 7.772 28.093 7.79 28.661 ; 
        RECT 8.699 28.992 8.717 29.928 ; 
        RECT 8.663 28.992 8.681 29.928 ; 
        RECT 8.627 29.569 8.645 29.892 ; 
        RECT 8.51 29.766 8.528 29.876 ; 
        RECT 8.501 29.025 8.519 29.264 ; 
        RECT 8.465 29.606 8.483 29.759 ; 
        RECT 8.384 29.631 8.402 29.889 ; 
        RECT 7.844 28.992 7.862 29.928 ; 
        RECT 7.808 28.992 7.826 29.928 ; 
        RECT 7.772 29.173 7.79 29.741 ; 
  LAYER M3 SPACING 0.072 ; 
      RECT 8.641 0.257 8.769 1.35 ; 
      RECT 8.627 0.922 8.769 1.245 ; 
      RECT 8.479 0.649 8.541 1.35 ; 
      RECT 8.465 0.959 8.541 1.112 ; 
      RECT 8.479 0.257 8.505 1.35 ; 
      RECT 8.479 0.378 8.519 0.617 ; 
      RECT 8.479 0.257 8.541 0.346 ; 
      RECT 8.182 0.707 8.388 1.35 ; 
      RECT 8.362 0.257 8.388 1.35 ; 
      RECT 8.182 0.984 8.402 1.242 ; 
      RECT 8.182 0.257 8.28 1.35 ; 
      RECT 7.765 0.257 7.848 1.35 ; 
      RECT 7.765 0.345 7.862 1.281 ; 
      RECT 16.444 0.257 16.529 1.35 ; 
      RECT 16.3 0.257 16.326 1.35 ; 
      RECT 16.192 0.257 16.218 1.35 ; 
      RECT 16.084 0.257 16.11 1.35 ; 
      RECT 15.976 0.257 16.002 1.35 ; 
      RECT 15.868 0.257 15.894 1.35 ; 
      RECT 15.76 0.257 15.786 1.35 ; 
      RECT 15.652 0.257 15.678 1.35 ; 
      RECT 15.544 0.257 15.57 1.35 ; 
      RECT 15.436 0.257 15.462 1.35 ; 
      RECT 15.328 0.257 15.354 1.35 ; 
      RECT 15.22 0.257 15.246 1.35 ; 
      RECT 15.112 0.257 15.138 1.35 ; 
      RECT 15.004 0.257 15.03 1.35 ; 
      RECT 14.896 0.257 14.922 1.35 ; 
      RECT 14.788 0.257 14.814 1.35 ; 
      RECT 14.68 0.257 14.706 1.35 ; 
      RECT 14.572 0.257 14.598 1.35 ; 
      RECT 14.464 0.257 14.49 1.35 ; 
      RECT 14.356 0.257 14.382 1.35 ; 
      RECT 14.248 0.257 14.274 1.35 ; 
      RECT 14.14 0.257 14.166 1.35 ; 
      RECT 14.032 0.257 14.058 1.35 ; 
      RECT 13.924 0.257 13.95 1.35 ; 
      RECT 13.816 0.257 13.842 1.35 ; 
      RECT 13.708 0.257 13.734 1.35 ; 
      RECT 13.6 0.257 13.626 1.35 ; 
      RECT 13.492 0.257 13.518 1.35 ; 
      RECT 13.384 0.257 13.41 1.35 ; 
      RECT 13.276 0.257 13.302 1.35 ; 
      RECT 13.168 0.257 13.194 1.35 ; 
      RECT 13.06 0.257 13.086 1.35 ; 
      RECT 12.952 0.257 12.978 1.35 ; 
      RECT 12.844 0.257 12.87 1.35 ; 
      RECT 12.736 0.257 12.762 1.35 ; 
      RECT 12.628 0.257 12.654 1.35 ; 
      RECT 12.52 0.257 12.546 1.35 ; 
      RECT 12.412 0.257 12.438 1.35 ; 
      RECT 12.304 0.257 12.33 1.35 ; 
      RECT 12.196 0.257 12.222 1.35 ; 
      RECT 12.088 0.257 12.114 1.35 ; 
      RECT 11.98 0.257 12.006 1.35 ; 
      RECT 11.872 0.257 11.898 1.35 ; 
      RECT 11.764 0.257 11.79 1.35 ; 
      RECT 11.656 0.257 11.682 1.35 ; 
      RECT 11.548 0.257 11.574 1.35 ; 
      RECT 11.44 0.257 11.466 1.35 ; 
      RECT 11.332 0.257 11.358 1.35 ; 
      RECT 11.224 0.257 11.25 1.35 ; 
      RECT 11.116 0.257 11.142 1.35 ; 
      RECT 11.008 0.257 11.034 1.35 ; 
      RECT 10.9 0.257 10.926 1.35 ; 
      RECT 10.792 0.257 10.818 1.35 ; 
      RECT 10.684 0.257 10.71 1.35 ; 
      RECT 10.576 0.257 10.602 1.35 ; 
      RECT 10.468 0.257 10.494 1.35 ; 
      RECT 10.36 0.257 10.386 1.35 ; 
      RECT 10.252 0.257 10.278 1.35 ; 
      RECT 10.144 0.257 10.17 1.35 ; 
      RECT 10.036 0.257 10.062 1.35 ; 
      RECT 9.928 0.257 9.954 1.35 ; 
      RECT 9.82 0.257 9.846 1.35 ; 
      RECT 9.712 0.257 9.738 1.35 ; 
      RECT 9.604 0.257 9.63 1.35 ; 
      RECT 9.496 0.257 9.522 1.35 ; 
      RECT 9.388 0.257 9.414 1.35 ; 
      RECT 9.175 0.257 9.252 1.35 ; 
      RECT 7.282 0.257 7.359 1.35 ; 
      RECT 7.12 0.257 7.146 1.35 ; 
      RECT 7.012 0.257 7.038 1.35 ; 
      RECT 6.904 0.257 6.93 1.35 ; 
      RECT 6.796 0.257 6.822 1.35 ; 
      RECT 6.688 0.257 6.714 1.35 ; 
      RECT 6.58 0.257 6.606 1.35 ; 
      RECT 6.472 0.257 6.498 1.35 ; 
      RECT 6.364 0.257 6.39 1.35 ; 
      RECT 6.256 0.257 6.282 1.35 ; 
      RECT 6.148 0.257 6.174 1.35 ; 
      RECT 6.04 0.257 6.066 1.35 ; 
      RECT 5.932 0.257 5.958 1.35 ; 
      RECT 5.824 0.257 5.85 1.35 ; 
      RECT 5.716 0.257 5.742 1.35 ; 
      RECT 5.608 0.257 5.634 1.35 ; 
      RECT 5.5 0.257 5.526 1.35 ; 
      RECT 5.392 0.257 5.418 1.35 ; 
      RECT 5.284 0.257 5.31 1.35 ; 
      RECT 5.176 0.257 5.202 1.35 ; 
      RECT 5.068 0.257 5.094 1.35 ; 
      RECT 4.96 0.257 4.986 1.35 ; 
      RECT 4.852 0.257 4.878 1.35 ; 
      RECT 4.744 0.257 4.77 1.35 ; 
      RECT 4.636 0.257 4.662 1.35 ; 
      RECT 4.528 0.257 4.554 1.35 ; 
      RECT 4.42 0.257 4.446 1.35 ; 
      RECT 4.312 0.257 4.338 1.35 ; 
      RECT 4.204 0.257 4.23 1.35 ; 
      RECT 4.096 0.257 4.122 1.35 ; 
      RECT 3.988 0.257 4.014 1.35 ; 
      RECT 3.88 0.257 3.906 1.35 ; 
      RECT 3.772 0.257 3.798 1.35 ; 
      RECT 3.664 0.257 3.69 1.35 ; 
      RECT 3.556 0.257 3.582 1.35 ; 
      RECT 3.448 0.257 3.474 1.35 ; 
      RECT 3.34 0.257 3.366 1.35 ; 
      RECT 3.232 0.257 3.258 1.35 ; 
      RECT 3.124 0.257 3.15 1.35 ; 
      RECT 3.016 0.257 3.042 1.35 ; 
      RECT 2.908 0.257 2.934 1.35 ; 
      RECT 2.8 0.257 2.826 1.35 ; 
      RECT 2.692 0.257 2.718 1.35 ; 
      RECT 2.584 0.257 2.61 1.35 ; 
      RECT 2.476 0.257 2.502 1.35 ; 
      RECT 2.368 0.257 2.394 1.35 ; 
      RECT 2.26 0.257 2.286 1.35 ; 
      RECT 2.152 0.257 2.178 1.35 ; 
      RECT 2.044 0.257 2.07 1.35 ; 
      RECT 1.936 0.257 1.962 1.35 ; 
      RECT 1.828 0.257 1.854 1.35 ; 
      RECT 1.72 0.257 1.746 1.35 ; 
      RECT 1.612 0.257 1.638 1.35 ; 
      RECT 1.504 0.257 1.53 1.35 ; 
      RECT 1.396 0.257 1.422 1.35 ; 
      RECT 1.288 0.257 1.314 1.35 ; 
      RECT 1.18 0.257 1.206 1.35 ; 
      RECT 1.072 0.257 1.098 1.35 ; 
      RECT 0.964 0.257 0.99 1.35 ; 
      RECT 0.856 0.257 0.882 1.35 ; 
      RECT 0.748 0.257 0.774 1.35 ; 
      RECT 0.64 0.257 0.666 1.35 ; 
      RECT 0.532 0.257 0.558 1.35 ; 
      RECT 0.424 0.257 0.45 1.35 ; 
      RECT 0.316 0.257 0.342 1.35 ; 
      RECT 0.208 0.257 0.234 1.35 ; 
      RECT 0.005 0.257 0.09 1.35 ; 
      RECT 8.641 1.337 8.769 2.43 ; 
      RECT 8.627 2.002 8.769 2.325 ; 
      RECT 8.479 1.729 8.541 2.43 ; 
      RECT 8.465 2.039 8.541 2.192 ; 
      RECT 8.479 1.337 8.505 2.43 ; 
      RECT 8.479 1.458 8.519 1.697 ; 
      RECT 8.479 1.337 8.541 1.426 ; 
      RECT 8.182 1.787 8.388 2.43 ; 
      RECT 8.362 1.337 8.388 2.43 ; 
      RECT 8.182 2.064 8.402 2.322 ; 
      RECT 8.182 1.337 8.28 2.43 ; 
      RECT 7.765 1.337 7.848 2.43 ; 
      RECT 7.765 1.425 7.862 2.361 ; 
      RECT 16.444 1.337 16.529 2.43 ; 
      RECT 16.3 1.337 16.326 2.43 ; 
      RECT 16.192 1.337 16.218 2.43 ; 
      RECT 16.084 1.337 16.11 2.43 ; 
      RECT 15.976 1.337 16.002 2.43 ; 
      RECT 15.868 1.337 15.894 2.43 ; 
      RECT 15.76 1.337 15.786 2.43 ; 
      RECT 15.652 1.337 15.678 2.43 ; 
      RECT 15.544 1.337 15.57 2.43 ; 
      RECT 15.436 1.337 15.462 2.43 ; 
      RECT 15.328 1.337 15.354 2.43 ; 
      RECT 15.22 1.337 15.246 2.43 ; 
      RECT 15.112 1.337 15.138 2.43 ; 
      RECT 15.004 1.337 15.03 2.43 ; 
      RECT 14.896 1.337 14.922 2.43 ; 
      RECT 14.788 1.337 14.814 2.43 ; 
      RECT 14.68 1.337 14.706 2.43 ; 
      RECT 14.572 1.337 14.598 2.43 ; 
      RECT 14.464 1.337 14.49 2.43 ; 
      RECT 14.356 1.337 14.382 2.43 ; 
      RECT 14.248 1.337 14.274 2.43 ; 
      RECT 14.14 1.337 14.166 2.43 ; 
      RECT 14.032 1.337 14.058 2.43 ; 
      RECT 13.924 1.337 13.95 2.43 ; 
      RECT 13.816 1.337 13.842 2.43 ; 
      RECT 13.708 1.337 13.734 2.43 ; 
      RECT 13.6 1.337 13.626 2.43 ; 
      RECT 13.492 1.337 13.518 2.43 ; 
      RECT 13.384 1.337 13.41 2.43 ; 
      RECT 13.276 1.337 13.302 2.43 ; 
      RECT 13.168 1.337 13.194 2.43 ; 
      RECT 13.06 1.337 13.086 2.43 ; 
      RECT 12.952 1.337 12.978 2.43 ; 
      RECT 12.844 1.337 12.87 2.43 ; 
      RECT 12.736 1.337 12.762 2.43 ; 
      RECT 12.628 1.337 12.654 2.43 ; 
      RECT 12.52 1.337 12.546 2.43 ; 
      RECT 12.412 1.337 12.438 2.43 ; 
      RECT 12.304 1.337 12.33 2.43 ; 
      RECT 12.196 1.337 12.222 2.43 ; 
      RECT 12.088 1.337 12.114 2.43 ; 
      RECT 11.98 1.337 12.006 2.43 ; 
      RECT 11.872 1.337 11.898 2.43 ; 
      RECT 11.764 1.337 11.79 2.43 ; 
      RECT 11.656 1.337 11.682 2.43 ; 
      RECT 11.548 1.337 11.574 2.43 ; 
      RECT 11.44 1.337 11.466 2.43 ; 
      RECT 11.332 1.337 11.358 2.43 ; 
      RECT 11.224 1.337 11.25 2.43 ; 
      RECT 11.116 1.337 11.142 2.43 ; 
      RECT 11.008 1.337 11.034 2.43 ; 
      RECT 10.9 1.337 10.926 2.43 ; 
      RECT 10.792 1.337 10.818 2.43 ; 
      RECT 10.684 1.337 10.71 2.43 ; 
      RECT 10.576 1.337 10.602 2.43 ; 
      RECT 10.468 1.337 10.494 2.43 ; 
      RECT 10.36 1.337 10.386 2.43 ; 
      RECT 10.252 1.337 10.278 2.43 ; 
      RECT 10.144 1.337 10.17 2.43 ; 
      RECT 10.036 1.337 10.062 2.43 ; 
      RECT 9.928 1.337 9.954 2.43 ; 
      RECT 9.82 1.337 9.846 2.43 ; 
      RECT 9.712 1.337 9.738 2.43 ; 
      RECT 9.604 1.337 9.63 2.43 ; 
      RECT 9.496 1.337 9.522 2.43 ; 
      RECT 9.388 1.337 9.414 2.43 ; 
      RECT 9.175 1.337 9.252 2.43 ; 
      RECT 7.282 1.337 7.359 2.43 ; 
      RECT 7.12 1.337 7.146 2.43 ; 
      RECT 7.012 1.337 7.038 2.43 ; 
      RECT 6.904 1.337 6.93 2.43 ; 
      RECT 6.796 1.337 6.822 2.43 ; 
      RECT 6.688 1.337 6.714 2.43 ; 
      RECT 6.58 1.337 6.606 2.43 ; 
      RECT 6.472 1.337 6.498 2.43 ; 
      RECT 6.364 1.337 6.39 2.43 ; 
      RECT 6.256 1.337 6.282 2.43 ; 
      RECT 6.148 1.337 6.174 2.43 ; 
      RECT 6.04 1.337 6.066 2.43 ; 
      RECT 5.932 1.337 5.958 2.43 ; 
      RECT 5.824 1.337 5.85 2.43 ; 
      RECT 5.716 1.337 5.742 2.43 ; 
      RECT 5.608 1.337 5.634 2.43 ; 
      RECT 5.5 1.337 5.526 2.43 ; 
      RECT 5.392 1.337 5.418 2.43 ; 
      RECT 5.284 1.337 5.31 2.43 ; 
      RECT 5.176 1.337 5.202 2.43 ; 
      RECT 5.068 1.337 5.094 2.43 ; 
      RECT 4.96 1.337 4.986 2.43 ; 
      RECT 4.852 1.337 4.878 2.43 ; 
      RECT 4.744 1.337 4.77 2.43 ; 
      RECT 4.636 1.337 4.662 2.43 ; 
      RECT 4.528 1.337 4.554 2.43 ; 
      RECT 4.42 1.337 4.446 2.43 ; 
      RECT 4.312 1.337 4.338 2.43 ; 
      RECT 4.204 1.337 4.23 2.43 ; 
      RECT 4.096 1.337 4.122 2.43 ; 
      RECT 3.988 1.337 4.014 2.43 ; 
      RECT 3.88 1.337 3.906 2.43 ; 
      RECT 3.772 1.337 3.798 2.43 ; 
      RECT 3.664 1.337 3.69 2.43 ; 
      RECT 3.556 1.337 3.582 2.43 ; 
      RECT 3.448 1.337 3.474 2.43 ; 
      RECT 3.34 1.337 3.366 2.43 ; 
      RECT 3.232 1.337 3.258 2.43 ; 
      RECT 3.124 1.337 3.15 2.43 ; 
      RECT 3.016 1.337 3.042 2.43 ; 
      RECT 2.908 1.337 2.934 2.43 ; 
      RECT 2.8 1.337 2.826 2.43 ; 
      RECT 2.692 1.337 2.718 2.43 ; 
      RECT 2.584 1.337 2.61 2.43 ; 
      RECT 2.476 1.337 2.502 2.43 ; 
      RECT 2.368 1.337 2.394 2.43 ; 
      RECT 2.26 1.337 2.286 2.43 ; 
      RECT 2.152 1.337 2.178 2.43 ; 
      RECT 2.044 1.337 2.07 2.43 ; 
      RECT 1.936 1.337 1.962 2.43 ; 
      RECT 1.828 1.337 1.854 2.43 ; 
      RECT 1.72 1.337 1.746 2.43 ; 
      RECT 1.612 1.337 1.638 2.43 ; 
      RECT 1.504 1.337 1.53 2.43 ; 
      RECT 1.396 1.337 1.422 2.43 ; 
      RECT 1.288 1.337 1.314 2.43 ; 
      RECT 1.18 1.337 1.206 2.43 ; 
      RECT 1.072 1.337 1.098 2.43 ; 
      RECT 0.964 1.337 0.99 2.43 ; 
      RECT 0.856 1.337 0.882 2.43 ; 
      RECT 0.748 1.337 0.774 2.43 ; 
      RECT 0.64 1.337 0.666 2.43 ; 
      RECT 0.532 1.337 0.558 2.43 ; 
      RECT 0.424 1.337 0.45 2.43 ; 
      RECT 0.316 1.337 0.342 2.43 ; 
      RECT 0.208 1.337 0.234 2.43 ; 
      RECT 0.005 1.337 0.09 2.43 ; 
      RECT 8.641 2.417 8.769 3.51 ; 
      RECT 8.627 3.082 8.769 3.405 ; 
      RECT 8.479 2.809 8.541 3.51 ; 
      RECT 8.465 3.119 8.541 3.272 ; 
      RECT 8.479 2.417 8.505 3.51 ; 
      RECT 8.479 2.538 8.519 2.777 ; 
      RECT 8.479 2.417 8.541 2.506 ; 
      RECT 8.182 2.867 8.388 3.51 ; 
      RECT 8.362 2.417 8.388 3.51 ; 
      RECT 8.182 3.144 8.402 3.402 ; 
      RECT 8.182 2.417 8.28 3.51 ; 
      RECT 7.765 2.417 7.848 3.51 ; 
      RECT 7.765 2.505 7.862 3.441 ; 
      RECT 16.444 2.417 16.529 3.51 ; 
      RECT 16.3 2.417 16.326 3.51 ; 
      RECT 16.192 2.417 16.218 3.51 ; 
      RECT 16.084 2.417 16.11 3.51 ; 
      RECT 15.976 2.417 16.002 3.51 ; 
      RECT 15.868 2.417 15.894 3.51 ; 
      RECT 15.76 2.417 15.786 3.51 ; 
      RECT 15.652 2.417 15.678 3.51 ; 
      RECT 15.544 2.417 15.57 3.51 ; 
      RECT 15.436 2.417 15.462 3.51 ; 
      RECT 15.328 2.417 15.354 3.51 ; 
      RECT 15.22 2.417 15.246 3.51 ; 
      RECT 15.112 2.417 15.138 3.51 ; 
      RECT 15.004 2.417 15.03 3.51 ; 
      RECT 14.896 2.417 14.922 3.51 ; 
      RECT 14.788 2.417 14.814 3.51 ; 
      RECT 14.68 2.417 14.706 3.51 ; 
      RECT 14.572 2.417 14.598 3.51 ; 
      RECT 14.464 2.417 14.49 3.51 ; 
      RECT 14.356 2.417 14.382 3.51 ; 
      RECT 14.248 2.417 14.274 3.51 ; 
      RECT 14.14 2.417 14.166 3.51 ; 
      RECT 14.032 2.417 14.058 3.51 ; 
      RECT 13.924 2.417 13.95 3.51 ; 
      RECT 13.816 2.417 13.842 3.51 ; 
      RECT 13.708 2.417 13.734 3.51 ; 
      RECT 13.6 2.417 13.626 3.51 ; 
      RECT 13.492 2.417 13.518 3.51 ; 
      RECT 13.384 2.417 13.41 3.51 ; 
      RECT 13.276 2.417 13.302 3.51 ; 
      RECT 13.168 2.417 13.194 3.51 ; 
      RECT 13.06 2.417 13.086 3.51 ; 
      RECT 12.952 2.417 12.978 3.51 ; 
      RECT 12.844 2.417 12.87 3.51 ; 
      RECT 12.736 2.417 12.762 3.51 ; 
      RECT 12.628 2.417 12.654 3.51 ; 
      RECT 12.52 2.417 12.546 3.51 ; 
      RECT 12.412 2.417 12.438 3.51 ; 
      RECT 12.304 2.417 12.33 3.51 ; 
      RECT 12.196 2.417 12.222 3.51 ; 
      RECT 12.088 2.417 12.114 3.51 ; 
      RECT 11.98 2.417 12.006 3.51 ; 
      RECT 11.872 2.417 11.898 3.51 ; 
      RECT 11.764 2.417 11.79 3.51 ; 
      RECT 11.656 2.417 11.682 3.51 ; 
      RECT 11.548 2.417 11.574 3.51 ; 
      RECT 11.44 2.417 11.466 3.51 ; 
      RECT 11.332 2.417 11.358 3.51 ; 
      RECT 11.224 2.417 11.25 3.51 ; 
      RECT 11.116 2.417 11.142 3.51 ; 
      RECT 11.008 2.417 11.034 3.51 ; 
      RECT 10.9 2.417 10.926 3.51 ; 
      RECT 10.792 2.417 10.818 3.51 ; 
      RECT 10.684 2.417 10.71 3.51 ; 
      RECT 10.576 2.417 10.602 3.51 ; 
      RECT 10.468 2.417 10.494 3.51 ; 
      RECT 10.36 2.417 10.386 3.51 ; 
      RECT 10.252 2.417 10.278 3.51 ; 
      RECT 10.144 2.417 10.17 3.51 ; 
      RECT 10.036 2.417 10.062 3.51 ; 
      RECT 9.928 2.417 9.954 3.51 ; 
      RECT 9.82 2.417 9.846 3.51 ; 
      RECT 9.712 2.417 9.738 3.51 ; 
      RECT 9.604 2.417 9.63 3.51 ; 
      RECT 9.496 2.417 9.522 3.51 ; 
      RECT 9.388 2.417 9.414 3.51 ; 
      RECT 9.175 2.417 9.252 3.51 ; 
      RECT 7.282 2.417 7.359 3.51 ; 
      RECT 7.12 2.417 7.146 3.51 ; 
      RECT 7.012 2.417 7.038 3.51 ; 
      RECT 6.904 2.417 6.93 3.51 ; 
      RECT 6.796 2.417 6.822 3.51 ; 
      RECT 6.688 2.417 6.714 3.51 ; 
      RECT 6.58 2.417 6.606 3.51 ; 
      RECT 6.472 2.417 6.498 3.51 ; 
      RECT 6.364 2.417 6.39 3.51 ; 
      RECT 6.256 2.417 6.282 3.51 ; 
      RECT 6.148 2.417 6.174 3.51 ; 
      RECT 6.04 2.417 6.066 3.51 ; 
      RECT 5.932 2.417 5.958 3.51 ; 
      RECT 5.824 2.417 5.85 3.51 ; 
      RECT 5.716 2.417 5.742 3.51 ; 
      RECT 5.608 2.417 5.634 3.51 ; 
      RECT 5.5 2.417 5.526 3.51 ; 
      RECT 5.392 2.417 5.418 3.51 ; 
      RECT 5.284 2.417 5.31 3.51 ; 
      RECT 5.176 2.417 5.202 3.51 ; 
      RECT 5.068 2.417 5.094 3.51 ; 
      RECT 4.96 2.417 4.986 3.51 ; 
      RECT 4.852 2.417 4.878 3.51 ; 
      RECT 4.744 2.417 4.77 3.51 ; 
      RECT 4.636 2.417 4.662 3.51 ; 
      RECT 4.528 2.417 4.554 3.51 ; 
      RECT 4.42 2.417 4.446 3.51 ; 
      RECT 4.312 2.417 4.338 3.51 ; 
      RECT 4.204 2.417 4.23 3.51 ; 
      RECT 4.096 2.417 4.122 3.51 ; 
      RECT 3.988 2.417 4.014 3.51 ; 
      RECT 3.88 2.417 3.906 3.51 ; 
      RECT 3.772 2.417 3.798 3.51 ; 
      RECT 3.664 2.417 3.69 3.51 ; 
      RECT 3.556 2.417 3.582 3.51 ; 
      RECT 3.448 2.417 3.474 3.51 ; 
      RECT 3.34 2.417 3.366 3.51 ; 
      RECT 3.232 2.417 3.258 3.51 ; 
      RECT 3.124 2.417 3.15 3.51 ; 
      RECT 3.016 2.417 3.042 3.51 ; 
      RECT 2.908 2.417 2.934 3.51 ; 
      RECT 2.8 2.417 2.826 3.51 ; 
      RECT 2.692 2.417 2.718 3.51 ; 
      RECT 2.584 2.417 2.61 3.51 ; 
      RECT 2.476 2.417 2.502 3.51 ; 
      RECT 2.368 2.417 2.394 3.51 ; 
      RECT 2.26 2.417 2.286 3.51 ; 
      RECT 2.152 2.417 2.178 3.51 ; 
      RECT 2.044 2.417 2.07 3.51 ; 
      RECT 1.936 2.417 1.962 3.51 ; 
      RECT 1.828 2.417 1.854 3.51 ; 
      RECT 1.72 2.417 1.746 3.51 ; 
      RECT 1.612 2.417 1.638 3.51 ; 
      RECT 1.504 2.417 1.53 3.51 ; 
      RECT 1.396 2.417 1.422 3.51 ; 
      RECT 1.288 2.417 1.314 3.51 ; 
      RECT 1.18 2.417 1.206 3.51 ; 
      RECT 1.072 2.417 1.098 3.51 ; 
      RECT 0.964 2.417 0.99 3.51 ; 
      RECT 0.856 2.417 0.882 3.51 ; 
      RECT 0.748 2.417 0.774 3.51 ; 
      RECT 0.64 2.417 0.666 3.51 ; 
      RECT 0.532 2.417 0.558 3.51 ; 
      RECT 0.424 2.417 0.45 3.51 ; 
      RECT 0.316 2.417 0.342 3.51 ; 
      RECT 0.208 2.417 0.234 3.51 ; 
      RECT 0.005 2.417 0.09 3.51 ; 
      RECT 8.641 3.497 8.769 4.59 ; 
      RECT 8.627 4.162 8.769 4.485 ; 
      RECT 8.479 3.889 8.541 4.59 ; 
      RECT 8.465 4.199 8.541 4.352 ; 
      RECT 8.479 3.497 8.505 4.59 ; 
      RECT 8.479 3.618 8.519 3.857 ; 
      RECT 8.479 3.497 8.541 3.586 ; 
      RECT 8.182 3.947 8.388 4.59 ; 
      RECT 8.362 3.497 8.388 4.59 ; 
      RECT 8.182 4.224 8.402 4.482 ; 
      RECT 8.182 3.497 8.28 4.59 ; 
      RECT 7.765 3.497 7.848 4.59 ; 
      RECT 7.765 3.585 7.862 4.521 ; 
      RECT 16.444 3.497 16.529 4.59 ; 
      RECT 16.3 3.497 16.326 4.59 ; 
      RECT 16.192 3.497 16.218 4.59 ; 
      RECT 16.084 3.497 16.11 4.59 ; 
      RECT 15.976 3.497 16.002 4.59 ; 
      RECT 15.868 3.497 15.894 4.59 ; 
      RECT 15.76 3.497 15.786 4.59 ; 
      RECT 15.652 3.497 15.678 4.59 ; 
      RECT 15.544 3.497 15.57 4.59 ; 
      RECT 15.436 3.497 15.462 4.59 ; 
      RECT 15.328 3.497 15.354 4.59 ; 
      RECT 15.22 3.497 15.246 4.59 ; 
      RECT 15.112 3.497 15.138 4.59 ; 
      RECT 15.004 3.497 15.03 4.59 ; 
      RECT 14.896 3.497 14.922 4.59 ; 
      RECT 14.788 3.497 14.814 4.59 ; 
      RECT 14.68 3.497 14.706 4.59 ; 
      RECT 14.572 3.497 14.598 4.59 ; 
      RECT 14.464 3.497 14.49 4.59 ; 
      RECT 14.356 3.497 14.382 4.59 ; 
      RECT 14.248 3.497 14.274 4.59 ; 
      RECT 14.14 3.497 14.166 4.59 ; 
      RECT 14.032 3.497 14.058 4.59 ; 
      RECT 13.924 3.497 13.95 4.59 ; 
      RECT 13.816 3.497 13.842 4.59 ; 
      RECT 13.708 3.497 13.734 4.59 ; 
      RECT 13.6 3.497 13.626 4.59 ; 
      RECT 13.492 3.497 13.518 4.59 ; 
      RECT 13.384 3.497 13.41 4.59 ; 
      RECT 13.276 3.497 13.302 4.59 ; 
      RECT 13.168 3.497 13.194 4.59 ; 
      RECT 13.06 3.497 13.086 4.59 ; 
      RECT 12.952 3.497 12.978 4.59 ; 
      RECT 12.844 3.497 12.87 4.59 ; 
      RECT 12.736 3.497 12.762 4.59 ; 
      RECT 12.628 3.497 12.654 4.59 ; 
      RECT 12.52 3.497 12.546 4.59 ; 
      RECT 12.412 3.497 12.438 4.59 ; 
      RECT 12.304 3.497 12.33 4.59 ; 
      RECT 12.196 3.497 12.222 4.59 ; 
      RECT 12.088 3.497 12.114 4.59 ; 
      RECT 11.98 3.497 12.006 4.59 ; 
      RECT 11.872 3.497 11.898 4.59 ; 
      RECT 11.764 3.497 11.79 4.59 ; 
      RECT 11.656 3.497 11.682 4.59 ; 
      RECT 11.548 3.497 11.574 4.59 ; 
      RECT 11.44 3.497 11.466 4.59 ; 
      RECT 11.332 3.497 11.358 4.59 ; 
      RECT 11.224 3.497 11.25 4.59 ; 
      RECT 11.116 3.497 11.142 4.59 ; 
      RECT 11.008 3.497 11.034 4.59 ; 
      RECT 10.9 3.497 10.926 4.59 ; 
      RECT 10.792 3.497 10.818 4.59 ; 
      RECT 10.684 3.497 10.71 4.59 ; 
      RECT 10.576 3.497 10.602 4.59 ; 
      RECT 10.468 3.497 10.494 4.59 ; 
      RECT 10.36 3.497 10.386 4.59 ; 
      RECT 10.252 3.497 10.278 4.59 ; 
      RECT 10.144 3.497 10.17 4.59 ; 
      RECT 10.036 3.497 10.062 4.59 ; 
      RECT 9.928 3.497 9.954 4.59 ; 
      RECT 9.82 3.497 9.846 4.59 ; 
      RECT 9.712 3.497 9.738 4.59 ; 
      RECT 9.604 3.497 9.63 4.59 ; 
      RECT 9.496 3.497 9.522 4.59 ; 
      RECT 9.388 3.497 9.414 4.59 ; 
      RECT 9.175 3.497 9.252 4.59 ; 
      RECT 7.282 3.497 7.359 4.59 ; 
      RECT 7.12 3.497 7.146 4.59 ; 
      RECT 7.012 3.497 7.038 4.59 ; 
      RECT 6.904 3.497 6.93 4.59 ; 
      RECT 6.796 3.497 6.822 4.59 ; 
      RECT 6.688 3.497 6.714 4.59 ; 
      RECT 6.58 3.497 6.606 4.59 ; 
      RECT 6.472 3.497 6.498 4.59 ; 
      RECT 6.364 3.497 6.39 4.59 ; 
      RECT 6.256 3.497 6.282 4.59 ; 
      RECT 6.148 3.497 6.174 4.59 ; 
      RECT 6.04 3.497 6.066 4.59 ; 
      RECT 5.932 3.497 5.958 4.59 ; 
      RECT 5.824 3.497 5.85 4.59 ; 
      RECT 5.716 3.497 5.742 4.59 ; 
      RECT 5.608 3.497 5.634 4.59 ; 
      RECT 5.5 3.497 5.526 4.59 ; 
      RECT 5.392 3.497 5.418 4.59 ; 
      RECT 5.284 3.497 5.31 4.59 ; 
      RECT 5.176 3.497 5.202 4.59 ; 
      RECT 5.068 3.497 5.094 4.59 ; 
      RECT 4.96 3.497 4.986 4.59 ; 
      RECT 4.852 3.497 4.878 4.59 ; 
      RECT 4.744 3.497 4.77 4.59 ; 
      RECT 4.636 3.497 4.662 4.59 ; 
      RECT 4.528 3.497 4.554 4.59 ; 
      RECT 4.42 3.497 4.446 4.59 ; 
      RECT 4.312 3.497 4.338 4.59 ; 
      RECT 4.204 3.497 4.23 4.59 ; 
      RECT 4.096 3.497 4.122 4.59 ; 
      RECT 3.988 3.497 4.014 4.59 ; 
      RECT 3.88 3.497 3.906 4.59 ; 
      RECT 3.772 3.497 3.798 4.59 ; 
      RECT 3.664 3.497 3.69 4.59 ; 
      RECT 3.556 3.497 3.582 4.59 ; 
      RECT 3.448 3.497 3.474 4.59 ; 
      RECT 3.34 3.497 3.366 4.59 ; 
      RECT 3.232 3.497 3.258 4.59 ; 
      RECT 3.124 3.497 3.15 4.59 ; 
      RECT 3.016 3.497 3.042 4.59 ; 
      RECT 2.908 3.497 2.934 4.59 ; 
      RECT 2.8 3.497 2.826 4.59 ; 
      RECT 2.692 3.497 2.718 4.59 ; 
      RECT 2.584 3.497 2.61 4.59 ; 
      RECT 2.476 3.497 2.502 4.59 ; 
      RECT 2.368 3.497 2.394 4.59 ; 
      RECT 2.26 3.497 2.286 4.59 ; 
      RECT 2.152 3.497 2.178 4.59 ; 
      RECT 2.044 3.497 2.07 4.59 ; 
      RECT 1.936 3.497 1.962 4.59 ; 
      RECT 1.828 3.497 1.854 4.59 ; 
      RECT 1.72 3.497 1.746 4.59 ; 
      RECT 1.612 3.497 1.638 4.59 ; 
      RECT 1.504 3.497 1.53 4.59 ; 
      RECT 1.396 3.497 1.422 4.59 ; 
      RECT 1.288 3.497 1.314 4.59 ; 
      RECT 1.18 3.497 1.206 4.59 ; 
      RECT 1.072 3.497 1.098 4.59 ; 
      RECT 0.964 3.497 0.99 4.59 ; 
      RECT 0.856 3.497 0.882 4.59 ; 
      RECT 0.748 3.497 0.774 4.59 ; 
      RECT 0.64 3.497 0.666 4.59 ; 
      RECT 0.532 3.497 0.558 4.59 ; 
      RECT 0.424 3.497 0.45 4.59 ; 
      RECT 0.316 3.497 0.342 4.59 ; 
      RECT 0.208 3.497 0.234 4.59 ; 
      RECT 0.005 3.497 0.09 4.59 ; 
      RECT 8.641 4.577 8.769 5.67 ; 
      RECT 8.627 5.242 8.769 5.565 ; 
      RECT 8.479 4.969 8.541 5.67 ; 
      RECT 8.465 5.279 8.541 5.432 ; 
      RECT 8.479 4.577 8.505 5.67 ; 
      RECT 8.479 4.698 8.519 4.937 ; 
      RECT 8.479 4.577 8.541 4.666 ; 
      RECT 8.182 5.027 8.388 5.67 ; 
      RECT 8.362 4.577 8.388 5.67 ; 
      RECT 8.182 5.304 8.402 5.562 ; 
      RECT 8.182 4.577 8.28 5.67 ; 
      RECT 7.765 4.577 7.848 5.67 ; 
      RECT 7.765 4.665 7.862 5.601 ; 
      RECT 16.444 4.577 16.529 5.67 ; 
      RECT 16.3 4.577 16.326 5.67 ; 
      RECT 16.192 4.577 16.218 5.67 ; 
      RECT 16.084 4.577 16.11 5.67 ; 
      RECT 15.976 4.577 16.002 5.67 ; 
      RECT 15.868 4.577 15.894 5.67 ; 
      RECT 15.76 4.577 15.786 5.67 ; 
      RECT 15.652 4.577 15.678 5.67 ; 
      RECT 15.544 4.577 15.57 5.67 ; 
      RECT 15.436 4.577 15.462 5.67 ; 
      RECT 15.328 4.577 15.354 5.67 ; 
      RECT 15.22 4.577 15.246 5.67 ; 
      RECT 15.112 4.577 15.138 5.67 ; 
      RECT 15.004 4.577 15.03 5.67 ; 
      RECT 14.896 4.577 14.922 5.67 ; 
      RECT 14.788 4.577 14.814 5.67 ; 
      RECT 14.68 4.577 14.706 5.67 ; 
      RECT 14.572 4.577 14.598 5.67 ; 
      RECT 14.464 4.577 14.49 5.67 ; 
      RECT 14.356 4.577 14.382 5.67 ; 
      RECT 14.248 4.577 14.274 5.67 ; 
      RECT 14.14 4.577 14.166 5.67 ; 
      RECT 14.032 4.577 14.058 5.67 ; 
      RECT 13.924 4.577 13.95 5.67 ; 
      RECT 13.816 4.577 13.842 5.67 ; 
      RECT 13.708 4.577 13.734 5.67 ; 
      RECT 13.6 4.577 13.626 5.67 ; 
      RECT 13.492 4.577 13.518 5.67 ; 
      RECT 13.384 4.577 13.41 5.67 ; 
      RECT 13.276 4.577 13.302 5.67 ; 
      RECT 13.168 4.577 13.194 5.67 ; 
      RECT 13.06 4.577 13.086 5.67 ; 
      RECT 12.952 4.577 12.978 5.67 ; 
      RECT 12.844 4.577 12.87 5.67 ; 
      RECT 12.736 4.577 12.762 5.67 ; 
      RECT 12.628 4.577 12.654 5.67 ; 
      RECT 12.52 4.577 12.546 5.67 ; 
      RECT 12.412 4.577 12.438 5.67 ; 
      RECT 12.304 4.577 12.33 5.67 ; 
      RECT 12.196 4.577 12.222 5.67 ; 
      RECT 12.088 4.577 12.114 5.67 ; 
      RECT 11.98 4.577 12.006 5.67 ; 
      RECT 11.872 4.577 11.898 5.67 ; 
      RECT 11.764 4.577 11.79 5.67 ; 
      RECT 11.656 4.577 11.682 5.67 ; 
      RECT 11.548 4.577 11.574 5.67 ; 
      RECT 11.44 4.577 11.466 5.67 ; 
      RECT 11.332 4.577 11.358 5.67 ; 
      RECT 11.224 4.577 11.25 5.67 ; 
      RECT 11.116 4.577 11.142 5.67 ; 
      RECT 11.008 4.577 11.034 5.67 ; 
      RECT 10.9 4.577 10.926 5.67 ; 
      RECT 10.792 4.577 10.818 5.67 ; 
      RECT 10.684 4.577 10.71 5.67 ; 
      RECT 10.576 4.577 10.602 5.67 ; 
      RECT 10.468 4.577 10.494 5.67 ; 
      RECT 10.36 4.577 10.386 5.67 ; 
      RECT 10.252 4.577 10.278 5.67 ; 
      RECT 10.144 4.577 10.17 5.67 ; 
      RECT 10.036 4.577 10.062 5.67 ; 
      RECT 9.928 4.577 9.954 5.67 ; 
      RECT 9.82 4.577 9.846 5.67 ; 
      RECT 9.712 4.577 9.738 5.67 ; 
      RECT 9.604 4.577 9.63 5.67 ; 
      RECT 9.496 4.577 9.522 5.67 ; 
      RECT 9.388 4.577 9.414 5.67 ; 
      RECT 9.175 4.577 9.252 5.67 ; 
      RECT 7.282 4.577 7.359 5.67 ; 
      RECT 7.12 4.577 7.146 5.67 ; 
      RECT 7.012 4.577 7.038 5.67 ; 
      RECT 6.904 4.577 6.93 5.67 ; 
      RECT 6.796 4.577 6.822 5.67 ; 
      RECT 6.688 4.577 6.714 5.67 ; 
      RECT 6.58 4.577 6.606 5.67 ; 
      RECT 6.472 4.577 6.498 5.67 ; 
      RECT 6.364 4.577 6.39 5.67 ; 
      RECT 6.256 4.577 6.282 5.67 ; 
      RECT 6.148 4.577 6.174 5.67 ; 
      RECT 6.04 4.577 6.066 5.67 ; 
      RECT 5.932 4.577 5.958 5.67 ; 
      RECT 5.824 4.577 5.85 5.67 ; 
      RECT 5.716 4.577 5.742 5.67 ; 
      RECT 5.608 4.577 5.634 5.67 ; 
      RECT 5.5 4.577 5.526 5.67 ; 
      RECT 5.392 4.577 5.418 5.67 ; 
      RECT 5.284 4.577 5.31 5.67 ; 
      RECT 5.176 4.577 5.202 5.67 ; 
      RECT 5.068 4.577 5.094 5.67 ; 
      RECT 4.96 4.577 4.986 5.67 ; 
      RECT 4.852 4.577 4.878 5.67 ; 
      RECT 4.744 4.577 4.77 5.67 ; 
      RECT 4.636 4.577 4.662 5.67 ; 
      RECT 4.528 4.577 4.554 5.67 ; 
      RECT 4.42 4.577 4.446 5.67 ; 
      RECT 4.312 4.577 4.338 5.67 ; 
      RECT 4.204 4.577 4.23 5.67 ; 
      RECT 4.096 4.577 4.122 5.67 ; 
      RECT 3.988 4.577 4.014 5.67 ; 
      RECT 3.88 4.577 3.906 5.67 ; 
      RECT 3.772 4.577 3.798 5.67 ; 
      RECT 3.664 4.577 3.69 5.67 ; 
      RECT 3.556 4.577 3.582 5.67 ; 
      RECT 3.448 4.577 3.474 5.67 ; 
      RECT 3.34 4.577 3.366 5.67 ; 
      RECT 3.232 4.577 3.258 5.67 ; 
      RECT 3.124 4.577 3.15 5.67 ; 
      RECT 3.016 4.577 3.042 5.67 ; 
      RECT 2.908 4.577 2.934 5.67 ; 
      RECT 2.8 4.577 2.826 5.67 ; 
      RECT 2.692 4.577 2.718 5.67 ; 
      RECT 2.584 4.577 2.61 5.67 ; 
      RECT 2.476 4.577 2.502 5.67 ; 
      RECT 2.368 4.577 2.394 5.67 ; 
      RECT 2.26 4.577 2.286 5.67 ; 
      RECT 2.152 4.577 2.178 5.67 ; 
      RECT 2.044 4.577 2.07 5.67 ; 
      RECT 1.936 4.577 1.962 5.67 ; 
      RECT 1.828 4.577 1.854 5.67 ; 
      RECT 1.72 4.577 1.746 5.67 ; 
      RECT 1.612 4.577 1.638 5.67 ; 
      RECT 1.504 4.577 1.53 5.67 ; 
      RECT 1.396 4.577 1.422 5.67 ; 
      RECT 1.288 4.577 1.314 5.67 ; 
      RECT 1.18 4.577 1.206 5.67 ; 
      RECT 1.072 4.577 1.098 5.67 ; 
      RECT 0.964 4.577 0.99 5.67 ; 
      RECT 0.856 4.577 0.882 5.67 ; 
      RECT 0.748 4.577 0.774 5.67 ; 
      RECT 0.64 4.577 0.666 5.67 ; 
      RECT 0.532 4.577 0.558 5.67 ; 
      RECT 0.424 4.577 0.45 5.67 ; 
      RECT 0.316 4.577 0.342 5.67 ; 
      RECT 0.208 4.577 0.234 5.67 ; 
      RECT 0.005 4.577 0.09 5.67 ; 
      RECT 8.641 5.657 8.769 6.75 ; 
      RECT 8.627 6.322 8.769 6.645 ; 
      RECT 8.479 6.049 8.541 6.75 ; 
      RECT 8.465 6.359 8.541 6.512 ; 
      RECT 8.479 5.657 8.505 6.75 ; 
      RECT 8.479 5.778 8.519 6.017 ; 
      RECT 8.479 5.657 8.541 5.746 ; 
      RECT 8.182 6.107 8.388 6.75 ; 
      RECT 8.362 5.657 8.388 6.75 ; 
      RECT 8.182 6.384 8.402 6.642 ; 
      RECT 8.182 5.657 8.28 6.75 ; 
      RECT 7.765 5.657 7.848 6.75 ; 
      RECT 7.765 5.745 7.862 6.681 ; 
      RECT 16.444 5.657 16.529 6.75 ; 
      RECT 16.3 5.657 16.326 6.75 ; 
      RECT 16.192 5.657 16.218 6.75 ; 
      RECT 16.084 5.657 16.11 6.75 ; 
      RECT 15.976 5.657 16.002 6.75 ; 
      RECT 15.868 5.657 15.894 6.75 ; 
      RECT 15.76 5.657 15.786 6.75 ; 
      RECT 15.652 5.657 15.678 6.75 ; 
      RECT 15.544 5.657 15.57 6.75 ; 
      RECT 15.436 5.657 15.462 6.75 ; 
      RECT 15.328 5.657 15.354 6.75 ; 
      RECT 15.22 5.657 15.246 6.75 ; 
      RECT 15.112 5.657 15.138 6.75 ; 
      RECT 15.004 5.657 15.03 6.75 ; 
      RECT 14.896 5.657 14.922 6.75 ; 
      RECT 14.788 5.657 14.814 6.75 ; 
      RECT 14.68 5.657 14.706 6.75 ; 
      RECT 14.572 5.657 14.598 6.75 ; 
      RECT 14.464 5.657 14.49 6.75 ; 
      RECT 14.356 5.657 14.382 6.75 ; 
      RECT 14.248 5.657 14.274 6.75 ; 
      RECT 14.14 5.657 14.166 6.75 ; 
      RECT 14.032 5.657 14.058 6.75 ; 
      RECT 13.924 5.657 13.95 6.75 ; 
      RECT 13.816 5.657 13.842 6.75 ; 
      RECT 13.708 5.657 13.734 6.75 ; 
      RECT 13.6 5.657 13.626 6.75 ; 
      RECT 13.492 5.657 13.518 6.75 ; 
      RECT 13.384 5.657 13.41 6.75 ; 
      RECT 13.276 5.657 13.302 6.75 ; 
      RECT 13.168 5.657 13.194 6.75 ; 
      RECT 13.06 5.657 13.086 6.75 ; 
      RECT 12.952 5.657 12.978 6.75 ; 
      RECT 12.844 5.657 12.87 6.75 ; 
      RECT 12.736 5.657 12.762 6.75 ; 
      RECT 12.628 5.657 12.654 6.75 ; 
      RECT 12.52 5.657 12.546 6.75 ; 
      RECT 12.412 5.657 12.438 6.75 ; 
      RECT 12.304 5.657 12.33 6.75 ; 
      RECT 12.196 5.657 12.222 6.75 ; 
      RECT 12.088 5.657 12.114 6.75 ; 
      RECT 11.98 5.657 12.006 6.75 ; 
      RECT 11.872 5.657 11.898 6.75 ; 
      RECT 11.764 5.657 11.79 6.75 ; 
      RECT 11.656 5.657 11.682 6.75 ; 
      RECT 11.548 5.657 11.574 6.75 ; 
      RECT 11.44 5.657 11.466 6.75 ; 
      RECT 11.332 5.657 11.358 6.75 ; 
      RECT 11.224 5.657 11.25 6.75 ; 
      RECT 11.116 5.657 11.142 6.75 ; 
      RECT 11.008 5.657 11.034 6.75 ; 
      RECT 10.9 5.657 10.926 6.75 ; 
      RECT 10.792 5.657 10.818 6.75 ; 
      RECT 10.684 5.657 10.71 6.75 ; 
      RECT 10.576 5.657 10.602 6.75 ; 
      RECT 10.468 5.657 10.494 6.75 ; 
      RECT 10.36 5.657 10.386 6.75 ; 
      RECT 10.252 5.657 10.278 6.75 ; 
      RECT 10.144 5.657 10.17 6.75 ; 
      RECT 10.036 5.657 10.062 6.75 ; 
      RECT 9.928 5.657 9.954 6.75 ; 
      RECT 9.82 5.657 9.846 6.75 ; 
      RECT 9.712 5.657 9.738 6.75 ; 
      RECT 9.604 5.657 9.63 6.75 ; 
      RECT 9.496 5.657 9.522 6.75 ; 
      RECT 9.388 5.657 9.414 6.75 ; 
      RECT 9.175 5.657 9.252 6.75 ; 
      RECT 7.282 5.657 7.359 6.75 ; 
      RECT 7.12 5.657 7.146 6.75 ; 
      RECT 7.012 5.657 7.038 6.75 ; 
      RECT 6.904 5.657 6.93 6.75 ; 
      RECT 6.796 5.657 6.822 6.75 ; 
      RECT 6.688 5.657 6.714 6.75 ; 
      RECT 6.58 5.657 6.606 6.75 ; 
      RECT 6.472 5.657 6.498 6.75 ; 
      RECT 6.364 5.657 6.39 6.75 ; 
      RECT 6.256 5.657 6.282 6.75 ; 
      RECT 6.148 5.657 6.174 6.75 ; 
      RECT 6.04 5.657 6.066 6.75 ; 
      RECT 5.932 5.657 5.958 6.75 ; 
      RECT 5.824 5.657 5.85 6.75 ; 
      RECT 5.716 5.657 5.742 6.75 ; 
      RECT 5.608 5.657 5.634 6.75 ; 
      RECT 5.5 5.657 5.526 6.75 ; 
      RECT 5.392 5.657 5.418 6.75 ; 
      RECT 5.284 5.657 5.31 6.75 ; 
      RECT 5.176 5.657 5.202 6.75 ; 
      RECT 5.068 5.657 5.094 6.75 ; 
      RECT 4.96 5.657 4.986 6.75 ; 
      RECT 4.852 5.657 4.878 6.75 ; 
      RECT 4.744 5.657 4.77 6.75 ; 
      RECT 4.636 5.657 4.662 6.75 ; 
      RECT 4.528 5.657 4.554 6.75 ; 
      RECT 4.42 5.657 4.446 6.75 ; 
      RECT 4.312 5.657 4.338 6.75 ; 
      RECT 4.204 5.657 4.23 6.75 ; 
      RECT 4.096 5.657 4.122 6.75 ; 
      RECT 3.988 5.657 4.014 6.75 ; 
      RECT 3.88 5.657 3.906 6.75 ; 
      RECT 3.772 5.657 3.798 6.75 ; 
      RECT 3.664 5.657 3.69 6.75 ; 
      RECT 3.556 5.657 3.582 6.75 ; 
      RECT 3.448 5.657 3.474 6.75 ; 
      RECT 3.34 5.657 3.366 6.75 ; 
      RECT 3.232 5.657 3.258 6.75 ; 
      RECT 3.124 5.657 3.15 6.75 ; 
      RECT 3.016 5.657 3.042 6.75 ; 
      RECT 2.908 5.657 2.934 6.75 ; 
      RECT 2.8 5.657 2.826 6.75 ; 
      RECT 2.692 5.657 2.718 6.75 ; 
      RECT 2.584 5.657 2.61 6.75 ; 
      RECT 2.476 5.657 2.502 6.75 ; 
      RECT 2.368 5.657 2.394 6.75 ; 
      RECT 2.26 5.657 2.286 6.75 ; 
      RECT 2.152 5.657 2.178 6.75 ; 
      RECT 2.044 5.657 2.07 6.75 ; 
      RECT 1.936 5.657 1.962 6.75 ; 
      RECT 1.828 5.657 1.854 6.75 ; 
      RECT 1.72 5.657 1.746 6.75 ; 
      RECT 1.612 5.657 1.638 6.75 ; 
      RECT 1.504 5.657 1.53 6.75 ; 
      RECT 1.396 5.657 1.422 6.75 ; 
      RECT 1.288 5.657 1.314 6.75 ; 
      RECT 1.18 5.657 1.206 6.75 ; 
      RECT 1.072 5.657 1.098 6.75 ; 
      RECT 0.964 5.657 0.99 6.75 ; 
      RECT 0.856 5.657 0.882 6.75 ; 
      RECT 0.748 5.657 0.774 6.75 ; 
      RECT 0.64 5.657 0.666 6.75 ; 
      RECT 0.532 5.657 0.558 6.75 ; 
      RECT 0.424 5.657 0.45 6.75 ; 
      RECT 0.316 5.657 0.342 6.75 ; 
      RECT 0.208 5.657 0.234 6.75 ; 
      RECT 0.005 5.657 0.09 6.75 ; 
      RECT 8.641 6.737 8.769 7.83 ; 
      RECT 8.627 7.402 8.769 7.725 ; 
      RECT 8.479 7.129 8.541 7.83 ; 
      RECT 8.465 7.439 8.541 7.592 ; 
      RECT 8.479 6.737 8.505 7.83 ; 
      RECT 8.479 6.858 8.519 7.097 ; 
      RECT 8.479 6.737 8.541 6.826 ; 
      RECT 8.182 7.187 8.388 7.83 ; 
      RECT 8.362 6.737 8.388 7.83 ; 
      RECT 8.182 7.464 8.402 7.722 ; 
      RECT 8.182 6.737 8.28 7.83 ; 
      RECT 7.765 6.737 7.848 7.83 ; 
      RECT 7.765 6.825 7.862 7.761 ; 
      RECT 16.444 6.737 16.529 7.83 ; 
      RECT 16.3 6.737 16.326 7.83 ; 
      RECT 16.192 6.737 16.218 7.83 ; 
      RECT 16.084 6.737 16.11 7.83 ; 
      RECT 15.976 6.737 16.002 7.83 ; 
      RECT 15.868 6.737 15.894 7.83 ; 
      RECT 15.76 6.737 15.786 7.83 ; 
      RECT 15.652 6.737 15.678 7.83 ; 
      RECT 15.544 6.737 15.57 7.83 ; 
      RECT 15.436 6.737 15.462 7.83 ; 
      RECT 15.328 6.737 15.354 7.83 ; 
      RECT 15.22 6.737 15.246 7.83 ; 
      RECT 15.112 6.737 15.138 7.83 ; 
      RECT 15.004 6.737 15.03 7.83 ; 
      RECT 14.896 6.737 14.922 7.83 ; 
      RECT 14.788 6.737 14.814 7.83 ; 
      RECT 14.68 6.737 14.706 7.83 ; 
      RECT 14.572 6.737 14.598 7.83 ; 
      RECT 14.464 6.737 14.49 7.83 ; 
      RECT 14.356 6.737 14.382 7.83 ; 
      RECT 14.248 6.737 14.274 7.83 ; 
      RECT 14.14 6.737 14.166 7.83 ; 
      RECT 14.032 6.737 14.058 7.83 ; 
      RECT 13.924 6.737 13.95 7.83 ; 
      RECT 13.816 6.737 13.842 7.83 ; 
      RECT 13.708 6.737 13.734 7.83 ; 
      RECT 13.6 6.737 13.626 7.83 ; 
      RECT 13.492 6.737 13.518 7.83 ; 
      RECT 13.384 6.737 13.41 7.83 ; 
      RECT 13.276 6.737 13.302 7.83 ; 
      RECT 13.168 6.737 13.194 7.83 ; 
      RECT 13.06 6.737 13.086 7.83 ; 
      RECT 12.952 6.737 12.978 7.83 ; 
      RECT 12.844 6.737 12.87 7.83 ; 
      RECT 12.736 6.737 12.762 7.83 ; 
      RECT 12.628 6.737 12.654 7.83 ; 
      RECT 12.52 6.737 12.546 7.83 ; 
      RECT 12.412 6.737 12.438 7.83 ; 
      RECT 12.304 6.737 12.33 7.83 ; 
      RECT 12.196 6.737 12.222 7.83 ; 
      RECT 12.088 6.737 12.114 7.83 ; 
      RECT 11.98 6.737 12.006 7.83 ; 
      RECT 11.872 6.737 11.898 7.83 ; 
      RECT 11.764 6.737 11.79 7.83 ; 
      RECT 11.656 6.737 11.682 7.83 ; 
      RECT 11.548 6.737 11.574 7.83 ; 
      RECT 11.44 6.737 11.466 7.83 ; 
      RECT 11.332 6.737 11.358 7.83 ; 
      RECT 11.224 6.737 11.25 7.83 ; 
      RECT 11.116 6.737 11.142 7.83 ; 
      RECT 11.008 6.737 11.034 7.83 ; 
      RECT 10.9 6.737 10.926 7.83 ; 
      RECT 10.792 6.737 10.818 7.83 ; 
      RECT 10.684 6.737 10.71 7.83 ; 
      RECT 10.576 6.737 10.602 7.83 ; 
      RECT 10.468 6.737 10.494 7.83 ; 
      RECT 10.36 6.737 10.386 7.83 ; 
      RECT 10.252 6.737 10.278 7.83 ; 
      RECT 10.144 6.737 10.17 7.83 ; 
      RECT 10.036 6.737 10.062 7.83 ; 
      RECT 9.928 6.737 9.954 7.83 ; 
      RECT 9.82 6.737 9.846 7.83 ; 
      RECT 9.712 6.737 9.738 7.83 ; 
      RECT 9.604 6.737 9.63 7.83 ; 
      RECT 9.496 6.737 9.522 7.83 ; 
      RECT 9.388 6.737 9.414 7.83 ; 
      RECT 9.175 6.737 9.252 7.83 ; 
      RECT 7.282 6.737 7.359 7.83 ; 
      RECT 7.12 6.737 7.146 7.83 ; 
      RECT 7.012 6.737 7.038 7.83 ; 
      RECT 6.904 6.737 6.93 7.83 ; 
      RECT 6.796 6.737 6.822 7.83 ; 
      RECT 6.688 6.737 6.714 7.83 ; 
      RECT 6.58 6.737 6.606 7.83 ; 
      RECT 6.472 6.737 6.498 7.83 ; 
      RECT 6.364 6.737 6.39 7.83 ; 
      RECT 6.256 6.737 6.282 7.83 ; 
      RECT 6.148 6.737 6.174 7.83 ; 
      RECT 6.04 6.737 6.066 7.83 ; 
      RECT 5.932 6.737 5.958 7.83 ; 
      RECT 5.824 6.737 5.85 7.83 ; 
      RECT 5.716 6.737 5.742 7.83 ; 
      RECT 5.608 6.737 5.634 7.83 ; 
      RECT 5.5 6.737 5.526 7.83 ; 
      RECT 5.392 6.737 5.418 7.83 ; 
      RECT 5.284 6.737 5.31 7.83 ; 
      RECT 5.176 6.737 5.202 7.83 ; 
      RECT 5.068 6.737 5.094 7.83 ; 
      RECT 4.96 6.737 4.986 7.83 ; 
      RECT 4.852 6.737 4.878 7.83 ; 
      RECT 4.744 6.737 4.77 7.83 ; 
      RECT 4.636 6.737 4.662 7.83 ; 
      RECT 4.528 6.737 4.554 7.83 ; 
      RECT 4.42 6.737 4.446 7.83 ; 
      RECT 4.312 6.737 4.338 7.83 ; 
      RECT 4.204 6.737 4.23 7.83 ; 
      RECT 4.096 6.737 4.122 7.83 ; 
      RECT 3.988 6.737 4.014 7.83 ; 
      RECT 3.88 6.737 3.906 7.83 ; 
      RECT 3.772 6.737 3.798 7.83 ; 
      RECT 3.664 6.737 3.69 7.83 ; 
      RECT 3.556 6.737 3.582 7.83 ; 
      RECT 3.448 6.737 3.474 7.83 ; 
      RECT 3.34 6.737 3.366 7.83 ; 
      RECT 3.232 6.737 3.258 7.83 ; 
      RECT 3.124 6.737 3.15 7.83 ; 
      RECT 3.016 6.737 3.042 7.83 ; 
      RECT 2.908 6.737 2.934 7.83 ; 
      RECT 2.8 6.737 2.826 7.83 ; 
      RECT 2.692 6.737 2.718 7.83 ; 
      RECT 2.584 6.737 2.61 7.83 ; 
      RECT 2.476 6.737 2.502 7.83 ; 
      RECT 2.368 6.737 2.394 7.83 ; 
      RECT 2.26 6.737 2.286 7.83 ; 
      RECT 2.152 6.737 2.178 7.83 ; 
      RECT 2.044 6.737 2.07 7.83 ; 
      RECT 1.936 6.737 1.962 7.83 ; 
      RECT 1.828 6.737 1.854 7.83 ; 
      RECT 1.72 6.737 1.746 7.83 ; 
      RECT 1.612 6.737 1.638 7.83 ; 
      RECT 1.504 6.737 1.53 7.83 ; 
      RECT 1.396 6.737 1.422 7.83 ; 
      RECT 1.288 6.737 1.314 7.83 ; 
      RECT 1.18 6.737 1.206 7.83 ; 
      RECT 1.072 6.737 1.098 7.83 ; 
      RECT 0.964 6.737 0.99 7.83 ; 
      RECT 0.856 6.737 0.882 7.83 ; 
      RECT 0.748 6.737 0.774 7.83 ; 
      RECT 0.64 6.737 0.666 7.83 ; 
      RECT 0.532 6.737 0.558 7.83 ; 
      RECT 0.424 6.737 0.45 7.83 ; 
      RECT 0.316 6.737 0.342 7.83 ; 
      RECT 0.208 6.737 0.234 7.83 ; 
      RECT 0.005 6.737 0.09 7.83 ; 
      RECT 8.641 7.817 8.769 8.91 ; 
      RECT 8.627 8.482 8.769 8.805 ; 
      RECT 8.479 8.209 8.541 8.91 ; 
      RECT 8.465 8.519 8.541 8.672 ; 
      RECT 8.479 7.817 8.505 8.91 ; 
      RECT 8.479 7.938 8.519 8.177 ; 
      RECT 8.479 7.817 8.541 7.906 ; 
      RECT 8.182 8.267 8.388 8.91 ; 
      RECT 8.362 7.817 8.388 8.91 ; 
      RECT 8.182 8.544 8.402 8.802 ; 
      RECT 8.182 7.817 8.28 8.91 ; 
      RECT 7.765 7.817 7.848 8.91 ; 
      RECT 7.765 7.905 7.862 8.841 ; 
      RECT 16.444 7.817 16.529 8.91 ; 
      RECT 16.3 7.817 16.326 8.91 ; 
      RECT 16.192 7.817 16.218 8.91 ; 
      RECT 16.084 7.817 16.11 8.91 ; 
      RECT 15.976 7.817 16.002 8.91 ; 
      RECT 15.868 7.817 15.894 8.91 ; 
      RECT 15.76 7.817 15.786 8.91 ; 
      RECT 15.652 7.817 15.678 8.91 ; 
      RECT 15.544 7.817 15.57 8.91 ; 
      RECT 15.436 7.817 15.462 8.91 ; 
      RECT 15.328 7.817 15.354 8.91 ; 
      RECT 15.22 7.817 15.246 8.91 ; 
      RECT 15.112 7.817 15.138 8.91 ; 
      RECT 15.004 7.817 15.03 8.91 ; 
      RECT 14.896 7.817 14.922 8.91 ; 
      RECT 14.788 7.817 14.814 8.91 ; 
      RECT 14.68 7.817 14.706 8.91 ; 
      RECT 14.572 7.817 14.598 8.91 ; 
      RECT 14.464 7.817 14.49 8.91 ; 
      RECT 14.356 7.817 14.382 8.91 ; 
      RECT 14.248 7.817 14.274 8.91 ; 
      RECT 14.14 7.817 14.166 8.91 ; 
      RECT 14.032 7.817 14.058 8.91 ; 
      RECT 13.924 7.817 13.95 8.91 ; 
      RECT 13.816 7.817 13.842 8.91 ; 
      RECT 13.708 7.817 13.734 8.91 ; 
      RECT 13.6 7.817 13.626 8.91 ; 
      RECT 13.492 7.817 13.518 8.91 ; 
      RECT 13.384 7.817 13.41 8.91 ; 
      RECT 13.276 7.817 13.302 8.91 ; 
      RECT 13.168 7.817 13.194 8.91 ; 
      RECT 13.06 7.817 13.086 8.91 ; 
      RECT 12.952 7.817 12.978 8.91 ; 
      RECT 12.844 7.817 12.87 8.91 ; 
      RECT 12.736 7.817 12.762 8.91 ; 
      RECT 12.628 7.817 12.654 8.91 ; 
      RECT 12.52 7.817 12.546 8.91 ; 
      RECT 12.412 7.817 12.438 8.91 ; 
      RECT 12.304 7.817 12.33 8.91 ; 
      RECT 12.196 7.817 12.222 8.91 ; 
      RECT 12.088 7.817 12.114 8.91 ; 
      RECT 11.98 7.817 12.006 8.91 ; 
      RECT 11.872 7.817 11.898 8.91 ; 
      RECT 11.764 7.817 11.79 8.91 ; 
      RECT 11.656 7.817 11.682 8.91 ; 
      RECT 11.548 7.817 11.574 8.91 ; 
      RECT 11.44 7.817 11.466 8.91 ; 
      RECT 11.332 7.817 11.358 8.91 ; 
      RECT 11.224 7.817 11.25 8.91 ; 
      RECT 11.116 7.817 11.142 8.91 ; 
      RECT 11.008 7.817 11.034 8.91 ; 
      RECT 10.9 7.817 10.926 8.91 ; 
      RECT 10.792 7.817 10.818 8.91 ; 
      RECT 10.684 7.817 10.71 8.91 ; 
      RECT 10.576 7.817 10.602 8.91 ; 
      RECT 10.468 7.817 10.494 8.91 ; 
      RECT 10.36 7.817 10.386 8.91 ; 
      RECT 10.252 7.817 10.278 8.91 ; 
      RECT 10.144 7.817 10.17 8.91 ; 
      RECT 10.036 7.817 10.062 8.91 ; 
      RECT 9.928 7.817 9.954 8.91 ; 
      RECT 9.82 7.817 9.846 8.91 ; 
      RECT 9.712 7.817 9.738 8.91 ; 
      RECT 9.604 7.817 9.63 8.91 ; 
      RECT 9.496 7.817 9.522 8.91 ; 
      RECT 9.388 7.817 9.414 8.91 ; 
      RECT 9.175 7.817 9.252 8.91 ; 
      RECT 7.282 7.817 7.359 8.91 ; 
      RECT 7.12 7.817 7.146 8.91 ; 
      RECT 7.012 7.817 7.038 8.91 ; 
      RECT 6.904 7.817 6.93 8.91 ; 
      RECT 6.796 7.817 6.822 8.91 ; 
      RECT 6.688 7.817 6.714 8.91 ; 
      RECT 6.58 7.817 6.606 8.91 ; 
      RECT 6.472 7.817 6.498 8.91 ; 
      RECT 6.364 7.817 6.39 8.91 ; 
      RECT 6.256 7.817 6.282 8.91 ; 
      RECT 6.148 7.817 6.174 8.91 ; 
      RECT 6.04 7.817 6.066 8.91 ; 
      RECT 5.932 7.817 5.958 8.91 ; 
      RECT 5.824 7.817 5.85 8.91 ; 
      RECT 5.716 7.817 5.742 8.91 ; 
      RECT 5.608 7.817 5.634 8.91 ; 
      RECT 5.5 7.817 5.526 8.91 ; 
      RECT 5.392 7.817 5.418 8.91 ; 
      RECT 5.284 7.817 5.31 8.91 ; 
      RECT 5.176 7.817 5.202 8.91 ; 
      RECT 5.068 7.817 5.094 8.91 ; 
      RECT 4.96 7.817 4.986 8.91 ; 
      RECT 4.852 7.817 4.878 8.91 ; 
      RECT 4.744 7.817 4.77 8.91 ; 
      RECT 4.636 7.817 4.662 8.91 ; 
      RECT 4.528 7.817 4.554 8.91 ; 
      RECT 4.42 7.817 4.446 8.91 ; 
      RECT 4.312 7.817 4.338 8.91 ; 
      RECT 4.204 7.817 4.23 8.91 ; 
      RECT 4.096 7.817 4.122 8.91 ; 
      RECT 3.988 7.817 4.014 8.91 ; 
      RECT 3.88 7.817 3.906 8.91 ; 
      RECT 3.772 7.817 3.798 8.91 ; 
      RECT 3.664 7.817 3.69 8.91 ; 
      RECT 3.556 7.817 3.582 8.91 ; 
      RECT 3.448 7.817 3.474 8.91 ; 
      RECT 3.34 7.817 3.366 8.91 ; 
      RECT 3.232 7.817 3.258 8.91 ; 
      RECT 3.124 7.817 3.15 8.91 ; 
      RECT 3.016 7.817 3.042 8.91 ; 
      RECT 2.908 7.817 2.934 8.91 ; 
      RECT 2.8 7.817 2.826 8.91 ; 
      RECT 2.692 7.817 2.718 8.91 ; 
      RECT 2.584 7.817 2.61 8.91 ; 
      RECT 2.476 7.817 2.502 8.91 ; 
      RECT 2.368 7.817 2.394 8.91 ; 
      RECT 2.26 7.817 2.286 8.91 ; 
      RECT 2.152 7.817 2.178 8.91 ; 
      RECT 2.044 7.817 2.07 8.91 ; 
      RECT 1.936 7.817 1.962 8.91 ; 
      RECT 1.828 7.817 1.854 8.91 ; 
      RECT 1.72 7.817 1.746 8.91 ; 
      RECT 1.612 7.817 1.638 8.91 ; 
      RECT 1.504 7.817 1.53 8.91 ; 
      RECT 1.396 7.817 1.422 8.91 ; 
      RECT 1.288 7.817 1.314 8.91 ; 
      RECT 1.18 7.817 1.206 8.91 ; 
      RECT 1.072 7.817 1.098 8.91 ; 
      RECT 0.964 7.817 0.99 8.91 ; 
      RECT 0.856 7.817 0.882 8.91 ; 
      RECT 0.748 7.817 0.774 8.91 ; 
      RECT 0.64 7.817 0.666 8.91 ; 
      RECT 0.532 7.817 0.558 8.91 ; 
      RECT 0.424 7.817 0.45 8.91 ; 
      RECT 0.316 7.817 0.342 8.91 ; 
      RECT 0.208 7.817 0.234 8.91 ; 
      RECT 0.005 7.817 0.09 8.91 ; 
      RECT 8.641 8.897 8.769 9.99 ; 
      RECT 8.627 9.562 8.769 9.885 ; 
      RECT 8.479 9.289 8.541 9.99 ; 
      RECT 8.465 9.599 8.541 9.752 ; 
      RECT 8.479 8.897 8.505 9.99 ; 
      RECT 8.479 9.018 8.519 9.257 ; 
      RECT 8.479 8.897 8.541 8.986 ; 
      RECT 8.182 9.347 8.388 9.99 ; 
      RECT 8.362 8.897 8.388 9.99 ; 
      RECT 8.182 9.624 8.402 9.882 ; 
      RECT 8.182 8.897 8.28 9.99 ; 
      RECT 7.765 8.897 7.848 9.99 ; 
      RECT 7.765 8.985 7.862 9.921 ; 
      RECT 16.444 8.897 16.529 9.99 ; 
      RECT 16.3 8.897 16.326 9.99 ; 
      RECT 16.192 8.897 16.218 9.99 ; 
      RECT 16.084 8.897 16.11 9.99 ; 
      RECT 15.976 8.897 16.002 9.99 ; 
      RECT 15.868 8.897 15.894 9.99 ; 
      RECT 15.76 8.897 15.786 9.99 ; 
      RECT 15.652 8.897 15.678 9.99 ; 
      RECT 15.544 8.897 15.57 9.99 ; 
      RECT 15.436 8.897 15.462 9.99 ; 
      RECT 15.328 8.897 15.354 9.99 ; 
      RECT 15.22 8.897 15.246 9.99 ; 
      RECT 15.112 8.897 15.138 9.99 ; 
      RECT 15.004 8.897 15.03 9.99 ; 
      RECT 14.896 8.897 14.922 9.99 ; 
      RECT 14.788 8.897 14.814 9.99 ; 
      RECT 14.68 8.897 14.706 9.99 ; 
      RECT 14.572 8.897 14.598 9.99 ; 
      RECT 14.464 8.897 14.49 9.99 ; 
      RECT 14.356 8.897 14.382 9.99 ; 
      RECT 14.248 8.897 14.274 9.99 ; 
      RECT 14.14 8.897 14.166 9.99 ; 
      RECT 14.032 8.897 14.058 9.99 ; 
      RECT 13.924 8.897 13.95 9.99 ; 
      RECT 13.816 8.897 13.842 9.99 ; 
      RECT 13.708 8.897 13.734 9.99 ; 
      RECT 13.6 8.897 13.626 9.99 ; 
      RECT 13.492 8.897 13.518 9.99 ; 
      RECT 13.384 8.897 13.41 9.99 ; 
      RECT 13.276 8.897 13.302 9.99 ; 
      RECT 13.168 8.897 13.194 9.99 ; 
      RECT 13.06 8.897 13.086 9.99 ; 
      RECT 12.952 8.897 12.978 9.99 ; 
      RECT 12.844 8.897 12.87 9.99 ; 
      RECT 12.736 8.897 12.762 9.99 ; 
      RECT 12.628 8.897 12.654 9.99 ; 
      RECT 12.52 8.897 12.546 9.99 ; 
      RECT 12.412 8.897 12.438 9.99 ; 
      RECT 12.304 8.897 12.33 9.99 ; 
      RECT 12.196 8.897 12.222 9.99 ; 
      RECT 12.088 8.897 12.114 9.99 ; 
      RECT 11.98 8.897 12.006 9.99 ; 
      RECT 11.872 8.897 11.898 9.99 ; 
      RECT 11.764 8.897 11.79 9.99 ; 
      RECT 11.656 8.897 11.682 9.99 ; 
      RECT 11.548 8.897 11.574 9.99 ; 
      RECT 11.44 8.897 11.466 9.99 ; 
      RECT 11.332 8.897 11.358 9.99 ; 
      RECT 11.224 8.897 11.25 9.99 ; 
      RECT 11.116 8.897 11.142 9.99 ; 
      RECT 11.008 8.897 11.034 9.99 ; 
      RECT 10.9 8.897 10.926 9.99 ; 
      RECT 10.792 8.897 10.818 9.99 ; 
      RECT 10.684 8.897 10.71 9.99 ; 
      RECT 10.576 8.897 10.602 9.99 ; 
      RECT 10.468 8.897 10.494 9.99 ; 
      RECT 10.36 8.897 10.386 9.99 ; 
      RECT 10.252 8.897 10.278 9.99 ; 
      RECT 10.144 8.897 10.17 9.99 ; 
      RECT 10.036 8.897 10.062 9.99 ; 
      RECT 9.928 8.897 9.954 9.99 ; 
      RECT 9.82 8.897 9.846 9.99 ; 
      RECT 9.712 8.897 9.738 9.99 ; 
      RECT 9.604 8.897 9.63 9.99 ; 
      RECT 9.496 8.897 9.522 9.99 ; 
      RECT 9.388 8.897 9.414 9.99 ; 
      RECT 9.175 8.897 9.252 9.99 ; 
      RECT 7.282 8.897 7.359 9.99 ; 
      RECT 7.12 8.897 7.146 9.99 ; 
      RECT 7.012 8.897 7.038 9.99 ; 
      RECT 6.904 8.897 6.93 9.99 ; 
      RECT 6.796 8.897 6.822 9.99 ; 
      RECT 6.688 8.897 6.714 9.99 ; 
      RECT 6.58 8.897 6.606 9.99 ; 
      RECT 6.472 8.897 6.498 9.99 ; 
      RECT 6.364 8.897 6.39 9.99 ; 
      RECT 6.256 8.897 6.282 9.99 ; 
      RECT 6.148 8.897 6.174 9.99 ; 
      RECT 6.04 8.897 6.066 9.99 ; 
      RECT 5.932 8.897 5.958 9.99 ; 
      RECT 5.824 8.897 5.85 9.99 ; 
      RECT 5.716 8.897 5.742 9.99 ; 
      RECT 5.608 8.897 5.634 9.99 ; 
      RECT 5.5 8.897 5.526 9.99 ; 
      RECT 5.392 8.897 5.418 9.99 ; 
      RECT 5.284 8.897 5.31 9.99 ; 
      RECT 5.176 8.897 5.202 9.99 ; 
      RECT 5.068 8.897 5.094 9.99 ; 
      RECT 4.96 8.897 4.986 9.99 ; 
      RECT 4.852 8.897 4.878 9.99 ; 
      RECT 4.744 8.897 4.77 9.99 ; 
      RECT 4.636 8.897 4.662 9.99 ; 
      RECT 4.528 8.897 4.554 9.99 ; 
      RECT 4.42 8.897 4.446 9.99 ; 
      RECT 4.312 8.897 4.338 9.99 ; 
      RECT 4.204 8.897 4.23 9.99 ; 
      RECT 4.096 8.897 4.122 9.99 ; 
      RECT 3.988 8.897 4.014 9.99 ; 
      RECT 3.88 8.897 3.906 9.99 ; 
      RECT 3.772 8.897 3.798 9.99 ; 
      RECT 3.664 8.897 3.69 9.99 ; 
      RECT 3.556 8.897 3.582 9.99 ; 
      RECT 3.448 8.897 3.474 9.99 ; 
      RECT 3.34 8.897 3.366 9.99 ; 
      RECT 3.232 8.897 3.258 9.99 ; 
      RECT 3.124 8.897 3.15 9.99 ; 
      RECT 3.016 8.897 3.042 9.99 ; 
      RECT 2.908 8.897 2.934 9.99 ; 
      RECT 2.8 8.897 2.826 9.99 ; 
      RECT 2.692 8.897 2.718 9.99 ; 
      RECT 2.584 8.897 2.61 9.99 ; 
      RECT 2.476 8.897 2.502 9.99 ; 
      RECT 2.368 8.897 2.394 9.99 ; 
      RECT 2.26 8.897 2.286 9.99 ; 
      RECT 2.152 8.897 2.178 9.99 ; 
      RECT 2.044 8.897 2.07 9.99 ; 
      RECT 1.936 8.897 1.962 9.99 ; 
      RECT 1.828 8.897 1.854 9.99 ; 
      RECT 1.72 8.897 1.746 9.99 ; 
      RECT 1.612 8.897 1.638 9.99 ; 
      RECT 1.504 8.897 1.53 9.99 ; 
      RECT 1.396 8.897 1.422 9.99 ; 
      RECT 1.288 8.897 1.314 9.99 ; 
      RECT 1.18 8.897 1.206 9.99 ; 
      RECT 1.072 8.897 1.098 9.99 ; 
      RECT 0.964 8.897 0.99 9.99 ; 
      RECT 0.856 8.897 0.882 9.99 ; 
      RECT 0.748 8.897 0.774 9.99 ; 
      RECT 0.64 8.897 0.666 9.99 ; 
      RECT 0.532 8.897 0.558 9.99 ; 
      RECT 0.424 8.897 0.45 9.99 ; 
      RECT 0.316 8.897 0.342 9.99 ; 
      RECT 0.208 8.897 0.234 9.99 ; 
      RECT 0.005 8.897 0.09 9.99 ; 
      RECT 8.641 9.977 8.769 11.07 ; 
      RECT 8.627 10.642 8.769 10.965 ; 
      RECT 8.479 10.369 8.541 11.07 ; 
      RECT 8.465 10.679 8.541 10.832 ; 
      RECT 8.479 9.977 8.505 11.07 ; 
      RECT 8.479 10.098 8.519 10.337 ; 
      RECT 8.479 9.977 8.541 10.066 ; 
      RECT 8.182 10.427 8.388 11.07 ; 
      RECT 8.362 9.977 8.388 11.07 ; 
      RECT 8.182 10.704 8.402 10.962 ; 
      RECT 8.182 9.977 8.28 11.07 ; 
      RECT 7.765 9.977 7.848 11.07 ; 
      RECT 7.765 10.065 7.862 11.001 ; 
      RECT 16.444 9.977 16.529 11.07 ; 
      RECT 16.3 9.977 16.326 11.07 ; 
      RECT 16.192 9.977 16.218 11.07 ; 
      RECT 16.084 9.977 16.11 11.07 ; 
      RECT 15.976 9.977 16.002 11.07 ; 
      RECT 15.868 9.977 15.894 11.07 ; 
      RECT 15.76 9.977 15.786 11.07 ; 
      RECT 15.652 9.977 15.678 11.07 ; 
      RECT 15.544 9.977 15.57 11.07 ; 
      RECT 15.436 9.977 15.462 11.07 ; 
      RECT 15.328 9.977 15.354 11.07 ; 
      RECT 15.22 9.977 15.246 11.07 ; 
      RECT 15.112 9.977 15.138 11.07 ; 
      RECT 15.004 9.977 15.03 11.07 ; 
      RECT 14.896 9.977 14.922 11.07 ; 
      RECT 14.788 9.977 14.814 11.07 ; 
      RECT 14.68 9.977 14.706 11.07 ; 
      RECT 14.572 9.977 14.598 11.07 ; 
      RECT 14.464 9.977 14.49 11.07 ; 
      RECT 14.356 9.977 14.382 11.07 ; 
      RECT 14.248 9.977 14.274 11.07 ; 
      RECT 14.14 9.977 14.166 11.07 ; 
      RECT 14.032 9.977 14.058 11.07 ; 
      RECT 13.924 9.977 13.95 11.07 ; 
      RECT 13.816 9.977 13.842 11.07 ; 
      RECT 13.708 9.977 13.734 11.07 ; 
      RECT 13.6 9.977 13.626 11.07 ; 
      RECT 13.492 9.977 13.518 11.07 ; 
      RECT 13.384 9.977 13.41 11.07 ; 
      RECT 13.276 9.977 13.302 11.07 ; 
      RECT 13.168 9.977 13.194 11.07 ; 
      RECT 13.06 9.977 13.086 11.07 ; 
      RECT 12.952 9.977 12.978 11.07 ; 
      RECT 12.844 9.977 12.87 11.07 ; 
      RECT 12.736 9.977 12.762 11.07 ; 
      RECT 12.628 9.977 12.654 11.07 ; 
      RECT 12.52 9.977 12.546 11.07 ; 
      RECT 12.412 9.977 12.438 11.07 ; 
      RECT 12.304 9.977 12.33 11.07 ; 
      RECT 12.196 9.977 12.222 11.07 ; 
      RECT 12.088 9.977 12.114 11.07 ; 
      RECT 11.98 9.977 12.006 11.07 ; 
      RECT 11.872 9.977 11.898 11.07 ; 
      RECT 11.764 9.977 11.79 11.07 ; 
      RECT 11.656 9.977 11.682 11.07 ; 
      RECT 11.548 9.977 11.574 11.07 ; 
      RECT 11.44 9.977 11.466 11.07 ; 
      RECT 11.332 9.977 11.358 11.07 ; 
      RECT 11.224 9.977 11.25 11.07 ; 
      RECT 11.116 9.977 11.142 11.07 ; 
      RECT 11.008 9.977 11.034 11.07 ; 
      RECT 10.9 9.977 10.926 11.07 ; 
      RECT 10.792 9.977 10.818 11.07 ; 
      RECT 10.684 9.977 10.71 11.07 ; 
      RECT 10.576 9.977 10.602 11.07 ; 
      RECT 10.468 9.977 10.494 11.07 ; 
      RECT 10.36 9.977 10.386 11.07 ; 
      RECT 10.252 9.977 10.278 11.07 ; 
      RECT 10.144 9.977 10.17 11.07 ; 
      RECT 10.036 9.977 10.062 11.07 ; 
      RECT 9.928 9.977 9.954 11.07 ; 
      RECT 9.82 9.977 9.846 11.07 ; 
      RECT 9.712 9.977 9.738 11.07 ; 
      RECT 9.604 9.977 9.63 11.07 ; 
      RECT 9.496 9.977 9.522 11.07 ; 
      RECT 9.388 9.977 9.414 11.07 ; 
      RECT 9.175 9.977 9.252 11.07 ; 
      RECT 7.282 9.977 7.359 11.07 ; 
      RECT 7.12 9.977 7.146 11.07 ; 
      RECT 7.012 9.977 7.038 11.07 ; 
      RECT 6.904 9.977 6.93 11.07 ; 
      RECT 6.796 9.977 6.822 11.07 ; 
      RECT 6.688 9.977 6.714 11.07 ; 
      RECT 6.58 9.977 6.606 11.07 ; 
      RECT 6.472 9.977 6.498 11.07 ; 
      RECT 6.364 9.977 6.39 11.07 ; 
      RECT 6.256 9.977 6.282 11.07 ; 
      RECT 6.148 9.977 6.174 11.07 ; 
      RECT 6.04 9.977 6.066 11.07 ; 
      RECT 5.932 9.977 5.958 11.07 ; 
      RECT 5.824 9.977 5.85 11.07 ; 
      RECT 5.716 9.977 5.742 11.07 ; 
      RECT 5.608 9.977 5.634 11.07 ; 
      RECT 5.5 9.977 5.526 11.07 ; 
      RECT 5.392 9.977 5.418 11.07 ; 
      RECT 5.284 9.977 5.31 11.07 ; 
      RECT 5.176 9.977 5.202 11.07 ; 
      RECT 5.068 9.977 5.094 11.07 ; 
      RECT 4.96 9.977 4.986 11.07 ; 
      RECT 4.852 9.977 4.878 11.07 ; 
      RECT 4.744 9.977 4.77 11.07 ; 
      RECT 4.636 9.977 4.662 11.07 ; 
      RECT 4.528 9.977 4.554 11.07 ; 
      RECT 4.42 9.977 4.446 11.07 ; 
      RECT 4.312 9.977 4.338 11.07 ; 
      RECT 4.204 9.977 4.23 11.07 ; 
      RECT 4.096 9.977 4.122 11.07 ; 
      RECT 3.988 9.977 4.014 11.07 ; 
      RECT 3.88 9.977 3.906 11.07 ; 
      RECT 3.772 9.977 3.798 11.07 ; 
      RECT 3.664 9.977 3.69 11.07 ; 
      RECT 3.556 9.977 3.582 11.07 ; 
      RECT 3.448 9.977 3.474 11.07 ; 
      RECT 3.34 9.977 3.366 11.07 ; 
      RECT 3.232 9.977 3.258 11.07 ; 
      RECT 3.124 9.977 3.15 11.07 ; 
      RECT 3.016 9.977 3.042 11.07 ; 
      RECT 2.908 9.977 2.934 11.07 ; 
      RECT 2.8 9.977 2.826 11.07 ; 
      RECT 2.692 9.977 2.718 11.07 ; 
      RECT 2.584 9.977 2.61 11.07 ; 
      RECT 2.476 9.977 2.502 11.07 ; 
      RECT 2.368 9.977 2.394 11.07 ; 
      RECT 2.26 9.977 2.286 11.07 ; 
      RECT 2.152 9.977 2.178 11.07 ; 
      RECT 2.044 9.977 2.07 11.07 ; 
      RECT 1.936 9.977 1.962 11.07 ; 
      RECT 1.828 9.977 1.854 11.07 ; 
      RECT 1.72 9.977 1.746 11.07 ; 
      RECT 1.612 9.977 1.638 11.07 ; 
      RECT 1.504 9.977 1.53 11.07 ; 
      RECT 1.396 9.977 1.422 11.07 ; 
      RECT 1.288 9.977 1.314 11.07 ; 
      RECT 1.18 9.977 1.206 11.07 ; 
      RECT 1.072 9.977 1.098 11.07 ; 
      RECT 0.964 9.977 0.99 11.07 ; 
      RECT 0.856 9.977 0.882 11.07 ; 
      RECT 0.748 9.977 0.774 11.07 ; 
      RECT 0.64 9.977 0.666 11.07 ; 
      RECT 0.532 9.977 0.558 11.07 ; 
      RECT 0.424 9.977 0.45 11.07 ; 
      RECT 0.316 9.977 0.342 11.07 ; 
      RECT 0.208 9.977 0.234 11.07 ; 
      RECT 0.005 9.977 0.09 11.07 ; 
      RECT 0 19.25 16.524 19.691 ; 
      RECT 16.439 11.037 16.524 19.691 ; 
      RECT 9.383 12.541 16.321 19.691 ; 
      RECT 10.841 11.037 16.321 19.691 ; 
      RECT 7.223 19.242 9.301 19.691 ; 
      RECT 7.997 19.211 9.301 19.691 ; 
      RECT 0.203 12.346 7.141 19.691 ; 
      RECT 6.845 11.037 7.141 19.691 ; 
      RECT 0 11.037 0.085 19.691 ; 
      RECT 7.223 12.649 7.843 19.691 ; 
      RECT 7.997 19.206 9.265 19.691 ; 
      RECT 8.645 12.442 9.265 19.691 ; 
      RECT 8.636 18.949 9.265 19.691 ; 
      RECT 8.474 18.949 8.536 19.691 ; 
      RECT 7.997 18.949 8.383 19.691 ; 
      RECT 9.383 14.83 16.335 19.184 ; 
      RECT 0.189 14.83 7.141 19.184 ; 
      RECT 9.369 14.83 16.335 19.18 ; 
      RECT 0.189 14.83 7.155 19.18 ; 
      RECT 7.209 14.83 7.843 19.179 ; 
      RECT 8.177 11.722 8.347 19.691 ; 
      RECT 8.285 11.037 8.347 19.691 ; 
      RECT 7.493 11.458 7.879 18.802 ; 
      RECT 7.209 18.757 7.893 18.794 ; 
      RECT 8.631 17.683 9.265 18.791 ; 
      RECT 8.163 18.493 8.347 18.719 ; 
      RECT 8.177 17.917 8.361 18.179 ; 
      RECT 7.209 17.719 7.893 18.179 ; 
      RECT 8.163 17.179 8.347 17.639 ; 
      RECT 8.631 15.145 9.265 17.477 ; 
      RECT 7.209 15.793 7.893 16.937 ; 
      RECT 8.177 15.523 8.361 16.829 ; 
      RECT 8.163 16.099 8.361 16.559 ; 
      RECT 8.163 12.859 8.347 16.019 ; 
      RECT 8.163 12.859 8.361 15.479 ; 
      RECT 7.209 15.253 7.893 15.479 ; 
      RECT 8.645 12.442 9.301 14.798 ; 
      RECT 8.631 12.319 9.247 14.105 ; 
      RECT 7.223 13.291 7.893 13.661 ; 
      RECT 8.177 12.589 8.361 12.779 ; 
      RECT 7.277 12.553 7.893 12.743 ; 
      RECT 8.163 12.445 8.347 12.581 ; 
      RECT 7.277 11.803 7.879 18.802 ; 
      RECT 8.177 12.319 8.361 12.545 ; 
      RECT 9.545 12.349 16.321 19.691 ; 
      RECT 10.625 12.346 16.321 19.691 ; 
      RECT 9.383 11.037 9.463 19.691 ; 
      RECT 7.223 11.722 7.411 12.536 ; 
      RECT 9.383 11.037 9.679 12.44 ; 
      RECT 9.383 12.154 10.543 12.44 ; 
      RECT 10.625 11.037 10.759 19.691 ; 
      RECT 5.981 11.965 6.763 19.691 ; 
      RECT 0.203 11.037 5.899 19.691 ; 
      RECT 8.645 11.803 9.247 19.691 ; 
      RECT 8.681 11.214 9.301 12.287 ; 
      RECT 9.383 12.154 10.759 12.248 ; 
      RECT 10.409 11.037 16.321 12.245 ; 
      RECT 6.629 11.037 7.141 12.245 ; 
      RECT 8.163 12.175 8.361 12.239 ; 
      RECT 8.163 12.049 8.347 12.239 ; 
      RECT 10.193 11.77 16.321 12.245 ; 
      RECT 9.383 11.803 10.111 12.44 ; 
      RECT 8.177 11.779 8.361 12.041 ; 
      RECT 0.203 11.77 6.547 12.245 ; 
      RECT 6.413 11.037 6.547 19.691 ; 
      RECT 9.977 11.037 10.327 11.909 ; 
      RECT 9.383 11.722 9.895 12.44 ; 
      RECT 9.761 11.037 9.895 19.691 ; 
      RECT 6.197 11.722 6.547 19.691 ; 
      RECT 0.203 11.037 6.115 12.245 ; 
      RECT 8.177 11.037 8.203 19.691 ; 
      RECT 7.313 11.037 7.411 19.691 ; 
      RECT 6.197 11.037 6.331 19.691 ; 
      RECT 9.761 11.037 10.327 11.672 ; 
      RECT 8.645 11.037 9.247 11.672 ; 
      RECT 7.313 11.037 7.843 11.672 ; 
      RECT 6.413 11.037 7.141 11.672 ; 
      RECT 9.761 11.037 16.321 11.669 ; 
      RECT 0.203 11.037 6.331 11.669 ; 
      RECT 8.631 11.509 9.301 11.663 ; 
      RECT 9.383 11.037 16.321 11.405 ; 
      RECT 8.177 11.037 8.347 11.405 ; 
      RECT 7.223 11.037 7.843 11.405 ; 
      RECT 0.203 11.037 7.141 11.405 ; 
      RECT 7.997 11.037 8.347 11.302 ; 
      RECT 8.636 11.037 9.247 11.202 ; 
      RECT 7.997 11.037 8.383 11.202 ; 
      RECT 9.765 11.011 9.783 19.691 ; 
      RECT 9.657 11.011 9.675 19.691 ; 
      RECT 6.849 11.023 6.867 19.691 ; 
      RECT 6.741 11.023 6.759 19.691 ; 
      RECT 6.633 11.023 6.651 19.691 ; 
      RECT 6.525 11.023 6.543 19.691 ; 
      RECT 6.417 11.011 6.435 19.691 ; 
      RECT 6.309 11.011 6.327 19.691 ; 
      RECT 6.201 11.023 6.219 19.691 ; 
      RECT 6.093 11.023 6.111 19.691 ; 
      RECT 5.985 11.023 6.003 19.691 ; 
      RECT 5.877 11.023 5.895 19.691 ; 
      RECT 8.474 11.037 8.536 11.202 ; 
        RECT 8.641 19.184 8.769 20.277 ; 
        RECT 8.627 19.849 8.769 20.172 ; 
        RECT 8.479 19.576 8.541 20.277 ; 
        RECT 8.465 19.886 8.541 20.039 ; 
        RECT 8.479 19.184 8.505 20.277 ; 
        RECT 8.479 19.305 8.519 19.544 ; 
        RECT 8.479 19.184 8.541 19.273 ; 
        RECT 8.182 19.634 8.388 20.277 ; 
        RECT 8.362 19.184 8.388 20.277 ; 
        RECT 8.182 19.911 8.402 20.169 ; 
        RECT 8.182 19.184 8.28 20.277 ; 
        RECT 7.765 19.184 7.848 20.277 ; 
        RECT 7.765 19.272 7.862 20.208 ; 
        RECT 16.444 19.184 16.529 20.277 ; 
        RECT 16.3 19.184 16.326 20.277 ; 
        RECT 16.192 19.184 16.218 20.277 ; 
        RECT 16.084 19.184 16.11 20.277 ; 
        RECT 15.976 19.184 16.002 20.277 ; 
        RECT 15.868 19.184 15.894 20.277 ; 
        RECT 15.76 19.184 15.786 20.277 ; 
        RECT 15.652 19.184 15.678 20.277 ; 
        RECT 15.544 19.184 15.57 20.277 ; 
        RECT 15.436 19.184 15.462 20.277 ; 
        RECT 15.328 19.184 15.354 20.277 ; 
        RECT 15.22 19.184 15.246 20.277 ; 
        RECT 15.112 19.184 15.138 20.277 ; 
        RECT 15.004 19.184 15.03 20.277 ; 
        RECT 14.896 19.184 14.922 20.277 ; 
        RECT 14.788 19.184 14.814 20.277 ; 
        RECT 14.68 19.184 14.706 20.277 ; 
        RECT 14.572 19.184 14.598 20.277 ; 
        RECT 14.464 19.184 14.49 20.277 ; 
        RECT 14.356 19.184 14.382 20.277 ; 
        RECT 14.248 19.184 14.274 20.277 ; 
        RECT 14.14 19.184 14.166 20.277 ; 
        RECT 14.032 19.184 14.058 20.277 ; 
        RECT 13.924 19.184 13.95 20.277 ; 
        RECT 13.816 19.184 13.842 20.277 ; 
        RECT 13.708 19.184 13.734 20.277 ; 
        RECT 13.6 19.184 13.626 20.277 ; 
        RECT 13.492 19.184 13.518 20.277 ; 
        RECT 13.384 19.184 13.41 20.277 ; 
        RECT 13.276 19.184 13.302 20.277 ; 
        RECT 13.168 19.184 13.194 20.277 ; 
        RECT 13.06 19.184 13.086 20.277 ; 
        RECT 12.952 19.184 12.978 20.277 ; 
        RECT 12.844 19.184 12.87 20.277 ; 
        RECT 12.736 19.184 12.762 20.277 ; 
        RECT 12.628 19.184 12.654 20.277 ; 
        RECT 12.52 19.184 12.546 20.277 ; 
        RECT 12.412 19.184 12.438 20.277 ; 
        RECT 12.304 19.184 12.33 20.277 ; 
        RECT 12.196 19.184 12.222 20.277 ; 
        RECT 12.088 19.184 12.114 20.277 ; 
        RECT 11.98 19.184 12.006 20.277 ; 
        RECT 11.872 19.184 11.898 20.277 ; 
        RECT 11.764 19.184 11.79 20.277 ; 
        RECT 11.656 19.184 11.682 20.277 ; 
        RECT 11.548 19.184 11.574 20.277 ; 
        RECT 11.44 19.184 11.466 20.277 ; 
        RECT 11.332 19.184 11.358 20.277 ; 
        RECT 11.224 19.184 11.25 20.277 ; 
        RECT 11.116 19.184 11.142 20.277 ; 
        RECT 11.008 19.184 11.034 20.277 ; 
        RECT 10.9 19.184 10.926 20.277 ; 
        RECT 10.792 19.184 10.818 20.277 ; 
        RECT 10.684 19.184 10.71 20.277 ; 
        RECT 10.576 19.184 10.602 20.277 ; 
        RECT 10.468 19.184 10.494 20.277 ; 
        RECT 10.36 19.184 10.386 20.277 ; 
        RECT 10.252 19.184 10.278 20.277 ; 
        RECT 10.144 19.184 10.17 20.277 ; 
        RECT 10.036 19.184 10.062 20.277 ; 
        RECT 9.928 19.184 9.954 20.277 ; 
        RECT 9.82 19.184 9.846 20.277 ; 
        RECT 9.712 19.184 9.738 20.277 ; 
        RECT 9.604 19.184 9.63 20.277 ; 
        RECT 9.496 19.184 9.522 20.277 ; 
        RECT 9.388 19.184 9.414 20.277 ; 
        RECT 9.175 19.184 9.252 20.277 ; 
        RECT 7.282 19.184 7.359 20.277 ; 
        RECT 7.12 19.184 7.146 20.277 ; 
        RECT 7.012 19.184 7.038 20.277 ; 
        RECT 6.904 19.184 6.93 20.277 ; 
        RECT 6.796 19.184 6.822 20.277 ; 
        RECT 6.688 19.184 6.714 20.277 ; 
        RECT 6.58 19.184 6.606 20.277 ; 
        RECT 6.472 19.184 6.498 20.277 ; 
        RECT 6.364 19.184 6.39 20.277 ; 
        RECT 6.256 19.184 6.282 20.277 ; 
        RECT 6.148 19.184 6.174 20.277 ; 
        RECT 6.04 19.184 6.066 20.277 ; 
        RECT 5.932 19.184 5.958 20.277 ; 
        RECT 5.824 19.184 5.85 20.277 ; 
        RECT 5.716 19.184 5.742 20.277 ; 
        RECT 5.608 19.184 5.634 20.277 ; 
        RECT 5.5 19.184 5.526 20.277 ; 
        RECT 5.392 19.184 5.418 20.277 ; 
        RECT 5.284 19.184 5.31 20.277 ; 
        RECT 5.176 19.184 5.202 20.277 ; 
        RECT 5.068 19.184 5.094 20.277 ; 
        RECT 4.96 19.184 4.986 20.277 ; 
        RECT 4.852 19.184 4.878 20.277 ; 
        RECT 4.744 19.184 4.77 20.277 ; 
        RECT 4.636 19.184 4.662 20.277 ; 
        RECT 4.528 19.184 4.554 20.277 ; 
        RECT 4.42 19.184 4.446 20.277 ; 
        RECT 4.312 19.184 4.338 20.277 ; 
        RECT 4.204 19.184 4.23 20.277 ; 
        RECT 4.096 19.184 4.122 20.277 ; 
        RECT 3.988 19.184 4.014 20.277 ; 
        RECT 3.88 19.184 3.906 20.277 ; 
        RECT 3.772 19.184 3.798 20.277 ; 
        RECT 3.664 19.184 3.69 20.277 ; 
        RECT 3.556 19.184 3.582 20.277 ; 
        RECT 3.448 19.184 3.474 20.277 ; 
        RECT 3.34 19.184 3.366 20.277 ; 
        RECT 3.232 19.184 3.258 20.277 ; 
        RECT 3.124 19.184 3.15 20.277 ; 
        RECT 3.016 19.184 3.042 20.277 ; 
        RECT 2.908 19.184 2.934 20.277 ; 
        RECT 2.8 19.184 2.826 20.277 ; 
        RECT 2.692 19.184 2.718 20.277 ; 
        RECT 2.584 19.184 2.61 20.277 ; 
        RECT 2.476 19.184 2.502 20.277 ; 
        RECT 2.368 19.184 2.394 20.277 ; 
        RECT 2.26 19.184 2.286 20.277 ; 
        RECT 2.152 19.184 2.178 20.277 ; 
        RECT 2.044 19.184 2.07 20.277 ; 
        RECT 1.936 19.184 1.962 20.277 ; 
        RECT 1.828 19.184 1.854 20.277 ; 
        RECT 1.72 19.184 1.746 20.277 ; 
        RECT 1.612 19.184 1.638 20.277 ; 
        RECT 1.504 19.184 1.53 20.277 ; 
        RECT 1.396 19.184 1.422 20.277 ; 
        RECT 1.288 19.184 1.314 20.277 ; 
        RECT 1.18 19.184 1.206 20.277 ; 
        RECT 1.072 19.184 1.098 20.277 ; 
        RECT 0.964 19.184 0.99 20.277 ; 
        RECT 0.856 19.184 0.882 20.277 ; 
        RECT 0.748 19.184 0.774 20.277 ; 
        RECT 0.64 19.184 0.666 20.277 ; 
        RECT 0.532 19.184 0.558 20.277 ; 
        RECT 0.424 19.184 0.45 20.277 ; 
        RECT 0.316 19.184 0.342 20.277 ; 
        RECT 0.208 19.184 0.234 20.277 ; 
        RECT 0.005 19.184 0.09 20.277 ; 
        RECT 8.641 20.264 8.769 21.357 ; 
        RECT 8.627 20.929 8.769 21.252 ; 
        RECT 8.479 20.656 8.541 21.357 ; 
        RECT 8.465 20.966 8.541 21.119 ; 
        RECT 8.479 20.264 8.505 21.357 ; 
        RECT 8.479 20.385 8.519 20.624 ; 
        RECT 8.479 20.264 8.541 20.353 ; 
        RECT 8.182 20.714 8.388 21.357 ; 
        RECT 8.362 20.264 8.388 21.357 ; 
        RECT 8.182 20.991 8.402 21.249 ; 
        RECT 8.182 20.264 8.28 21.357 ; 
        RECT 7.765 20.264 7.848 21.357 ; 
        RECT 7.765 20.352 7.862 21.288 ; 
        RECT 16.444 20.264 16.529 21.357 ; 
        RECT 16.3 20.264 16.326 21.357 ; 
        RECT 16.192 20.264 16.218 21.357 ; 
        RECT 16.084 20.264 16.11 21.357 ; 
        RECT 15.976 20.264 16.002 21.357 ; 
        RECT 15.868 20.264 15.894 21.357 ; 
        RECT 15.76 20.264 15.786 21.357 ; 
        RECT 15.652 20.264 15.678 21.357 ; 
        RECT 15.544 20.264 15.57 21.357 ; 
        RECT 15.436 20.264 15.462 21.357 ; 
        RECT 15.328 20.264 15.354 21.357 ; 
        RECT 15.22 20.264 15.246 21.357 ; 
        RECT 15.112 20.264 15.138 21.357 ; 
        RECT 15.004 20.264 15.03 21.357 ; 
        RECT 14.896 20.264 14.922 21.357 ; 
        RECT 14.788 20.264 14.814 21.357 ; 
        RECT 14.68 20.264 14.706 21.357 ; 
        RECT 14.572 20.264 14.598 21.357 ; 
        RECT 14.464 20.264 14.49 21.357 ; 
        RECT 14.356 20.264 14.382 21.357 ; 
        RECT 14.248 20.264 14.274 21.357 ; 
        RECT 14.14 20.264 14.166 21.357 ; 
        RECT 14.032 20.264 14.058 21.357 ; 
        RECT 13.924 20.264 13.95 21.357 ; 
        RECT 13.816 20.264 13.842 21.357 ; 
        RECT 13.708 20.264 13.734 21.357 ; 
        RECT 13.6 20.264 13.626 21.357 ; 
        RECT 13.492 20.264 13.518 21.357 ; 
        RECT 13.384 20.264 13.41 21.357 ; 
        RECT 13.276 20.264 13.302 21.357 ; 
        RECT 13.168 20.264 13.194 21.357 ; 
        RECT 13.06 20.264 13.086 21.357 ; 
        RECT 12.952 20.264 12.978 21.357 ; 
        RECT 12.844 20.264 12.87 21.357 ; 
        RECT 12.736 20.264 12.762 21.357 ; 
        RECT 12.628 20.264 12.654 21.357 ; 
        RECT 12.52 20.264 12.546 21.357 ; 
        RECT 12.412 20.264 12.438 21.357 ; 
        RECT 12.304 20.264 12.33 21.357 ; 
        RECT 12.196 20.264 12.222 21.357 ; 
        RECT 12.088 20.264 12.114 21.357 ; 
        RECT 11.98 20.264 12.006 21.357 ; 
        RECT 11.872 20.264 11.898 21.357 ; 
        RECT 11.764 20.264 11.79 21.357 ; 
        RECT 11.656 20.264 11.682 21.357 ; 
        RECT 11.548 20.264 11.574 21.357 ; 
        RECT 11.44 20.264 11.466 21.357 ; 
        RECT 11.332 20.264 11.358 21.357 ; 
        RECT 11.224 20.264 11.25 21.357 ; 
        RECT 11.116 20.264 11.142 21.357 ; 
        RECT 11.008 20.264 11.034 21.357 ; 
        RECT 10.9 20.264 10.926 21.357 ; 
        RECT 10.792 20.264 10.818 21.357 ; 
        RECT 10.684 20.264 10.71 21.357 ; 
        RECT 10.576 20.264 10.602 21.357 ; 
        RECT 10.468 20.264 10.494 21.357 ; 
        RECT 10.36 20.264 10.386 21.357 ; 
        RECT 10.252 20.264 10.278 21.357 ; 
        RECT 10.144 20.264 10.17 21.357 ; 
        RECT 10.036 20.264 10.062 21.357 ; 
        RECT 9.928 20.264 9.954 21.357 ; 
        RECT 9.82 20.264 9.846 21.357 ; 
        RECT 9.712 20.264 9.738 21.357 ; 
        RECT 9.604 20.264 9.63 21.357 ; 
        RECT 9.496 20.264 9.522 21.357 ; 
        RECT 9.388 20.264 9.414 21.357 ; 
        RECT 9.175 20.264 9.252 21.357 ; 
        RECT 7.282 20.264 7.359 21.357 ; 
        RECT 7.12 20.264 7.146 21.357 ; 
        RECT 7.012 20.264 7.038 21.357 ; 
        RECT 6.904 20.264 6.93 21.357 ; 
        RECT 6.796 20.264 6.822 21.357 ; 
        RECT 6.688 20.264 6.714 21.357 ; 
        RECT 6.58 20.264 6.606 21.357 ; 
        RECT 6.472 20.264 6.498 21.357 ; 
        RECT 6.364 20.264 6.39 21.357 ; 
        RECT 6.256 20.264 6.282 21.357 ; 
        RECT 6.148 20.264 6.174 21.357 ; 
        RECT 6.04 20.264 6.066 21.357 ; 
        RECT 5.932 20.264 5.958 21.357 ; 
        RECT 5.824 20.264 5.85 21.357 ; 
        RECT 5.716 20.264 5.742 21.357 ; 
        RECT 5.608 20.264 5.634 21.357 ; 
        RECT 5.5 20.264 5.526 21.357 ; 
        RECT 5.392 20.264 5.418 21.357 ; 
        RECT 5.284 20.264 5.31 21.357 ; 
        RECT 5.176 20.264 5.202 21.357 ; 
        RECT 5.068 20.264 5.094 21.357 ; 
        RECT 4.96 20.264 4.986 21.357 ; 
        RECT 4.852 20.264 4.878 21.357 ; 
        RECT 4.744 20.264 4.77 21.357 ; 
        RECT 4.636 20.264 4.662 21.357 ; 
        RECT 4.528 20.264 4.554 21.357 ; 
        RECT 4.42 20.264 4.446 21.357 ; 
        RECT 4.312 20.264 4.338 21.357 ; 
        RECT 4.204 20.264 4.23 21.357 ; 
        RECT 4.096 20.264 4.122 21.357 ; 
        RECT 3.988 20.264 4.014 21.357 ; 
        RECT 3.88 20.264 3.906 21.357 ; 
        RECT 3.772 20.264 3.798 21.357 ; 
        RECT 3.664 20.264 3.69 21.357 ; 
        RECT 3.556 20.264 3.582 21.357 ; 
        RECT 3.448 20.264 3.474 21.357 ; 
        RECT 3.34 20.264 3.366 21.357 ; 
        RECT 3.232 20.264 3.258 21.357 ; 
        RECT 3.124 20.264 3.15 21.357 ; 
        RECT 3.016 20.264 3.042 21.357 ; 
        RECT 2.908 20.264 2.934 21.357 ; 
        RECT 2.8 20.264 2.826 21.357 ; 
        RECT 2.692 20.264 2.718 21.357 ; 
        RECT 2.584 20.264 2.61 21.357 ; 
        RECT 2.476 20.264 2.502 21.357 ; 
        RECT 2.368 20.264 2.394 21.357 ; 
        RECT 2.26 20.264 2.286 21.357 ; 
        RECT 2.152 20.264 2.178 21.357 ; 
        RECT 2.044 20.264 2.07 21.357 ; 
        RECT 1.936 20.264 1.962 21.357 ; 
        RECT 1.828 20.264 1.854 21.357 ; 
        RECT 1.72 20.264 1.746 21.357 ; 
        RECT 1.612 20.264 1.638 21.357 ; 
        RECT 1.504 20.264 1.53 21.357 ; 
        RECT 1.396 20.264 1.422 21.357 ; 
        RECT 1.288 20.264 1.314 21.357 ; 
        RECT 1.18 20.264 1.206 21.357 ; 
        RECT 1.072 20.264 1.098 21.357 ; 
        RECT 0.964 20.264 0.99 21.357 ; 
        RECT 0.856 20.264 0.882 21.357 ; 
        RECT 0.748 20.264 0.774 21.357 ; 
        RECT 0.64 20.264 0.666 21.357 ; 
        RECT 0.532 20.264 0.558 21.357 ; 
        RECT 0.424 20.264 0.45 21.357 ; 
        RECT 0.316 20.264 0.342 21.357 ; 
        RECT 0.208 20.264 0.234 21.357 ; 
        RECT 0.005 20.264 0.09 21.357 ; 
        RECT 8.641 21.344 8.769 22.437 ; 
        RECT 8.627 22.009 8.769 22.332 ; 
        RECT 8.479 21.736 8.541 22.437 ; 
        RECT 8.465 22.046 8.541 22.199 ; 
        RECT 8.479 21.344 8.505 22.437 ; 
        RECT 8.479 21.465 8.519 21.704 ; 
        RECT 8.479 21.344 8.541 21.433 ; 
        RECT 8.182 21.794 8.388 22.437 ; 
        RECT 8.362 21.344 8.388 22.437 ; 
        RECT 8.182 22.071 8.402 22.329 ; 
        RECT 8.182 21.344 8.28 22.437 ; 
        RECT 7.765 21.344 7.848 22.437 ; 
        RECT 7.765 21.432 7.862 22.368 ; 
        RECT 16.444 21.344 16.529 22.437 ; 
        RECT 16.3 21.344 16.326 22.437 ; 
        RECT 16.192 21.344 16.218 22.437 ; 
        RECT 16.084 21.344 16.11 22.437 ; 
        RECT 15.976 21.344 16.002 22.437 ; 
        RECT 15.868 21.344 15.894 22.437 ; 
        RECT 15.76 21.344 15.786 22.437 ; 
        RECT 15.652 21.344 15.678 22.437 ; 
        RECT 15.544 21.344 15.57 22.437 ; 
        RECT 15.436 21.344 15.462 22.437 ; 
        RECT 15.328 21.344 15.354 22.437 ; 
        RECT 15.22 21.344 15.246 22.437 ; 
        RECT 15.112 21.344 15.138 22.437 ; 
        RECT 15.004 21.344 15.03 22.437 ; 
        RECT 14.896 21.344 14.922 22.437 ; 
        RECT 14.788 21.344 14.814 22.437 ; 
        RECT 14.68 21.344 14.706 22.437 ; 
        RECT 14.572 21.344 14.598 22.437 ; 
        RECT 14.464 21.344 14.49 22.437 ; 
        RECT 14.356 21.344 14.382 22.437 ; 
        RECT 14.248 21.344 14.274 22.437 ; 
        RECT 14.14 21.344 14.166 22.437 ; 
        RECT 14.032 21.344 14.058 22.437 ; 
        RECT 13.924 21.344 13.95 22.437 ; 
        RECT 13.816 21.344 13.842 22.437 ; 
        RECT 13.708 21.344 13.734 22.437 ; 
        RECT 13.6 21.344 13.626 22.437 ; 
        RECT 13.492 21.344 13.518 22.437 ; 
        RECT 13.384 21.344 13.41 22.437 ; 
        RECT 13.276 21.344 13.302 22.437 ; 
        RECT 13.168 21.344 13.194 22.437 ; 
        RECT 13.06 21.344 13.086 22.437 ; 
        RECT 12.952 21.344 12.978 22.437 ; 
        RECT 12.844 21.344 12.87 22.437 ; 
        RECT 12.736 21.344 12.762 22.437 ; 
        RECT 12.628 21.344 12.654 22.437 ; 
        RECT 12.52 21.344 12.546 22.437 ; 
        RECT 12.412 21.344 12.438 22.437 ; 
        RECT 12.304 21.344 12.33 22.437 ; 
        RECT 12.196 21.344 12.222 22.437 ; 
        RECT 12.088 21.344 12.114 22.437 ; 
        RECT 11.98 21.344 12.006 22.437 ; 
        RECT 11.872 21.344 11.898 22.437 ; 
        RECT 11.764 21.344 11.79 22.437 ; 
        RECT 11.656 21.344 11.682 22.437 ; 
        RECT 11.548 21.344 11.574 22.437 ; 
        RECT 11.44 21.344 11.466 22.437 ; 
        RECT 11.332 21.344 11.358 22.437 ; 
        RECT 11.224 21.344 11.25 22.437 ; 
        RECT 11.116 21.344 11.142 22.437 ; 
        RECT 11.008 21.344 11.034 22.437 ; 
        RECT 10.9 21.344 10.926 22.437 ; 
        RECT 10.792 21.344 10.818 22.437 ; 
        RECT 10.684 21.344 10.71 22.437 ; 
        RECT 10.576 21.344 10.602 22.437 ; 
        RECT 10.468 21.344 10.494 22.437 ; 
        RECT 10.36 21.344 10.386 22.437 ; 
        RECT 10.252 21.344 10.278 22.437 ; 
        RECT 10.144 21.344 10.17 22.437 ; 
        RECT 10.036 21.344 10.062 22.437 ; 
        RECT 9.928 21.344 9.954 22.437 ; 
        RECT 9.82 21.344 9.846 22.437 ; 
        RECT 9.712 21.344 9.738 22.437 ; 
        RECT 9.604 21.344 9.63 22.437 ; 
        RECT 9.496 21.344 9.522 22.437 ; 
        RECT 9.388 21.344 9.414 22.437 ; 
        RECT 9.175 21.344 9.252 22.437 ; 
        RECT 7.282 21.344 7.359 22.437 ; 
        RECT 7.12 21.344 7.146 22.437 ; 
        RECT 7.012 21.344 7.038 22.437 ; 
        RECT 6.904 21.344 6.93 22.437 ; 
        RECT 6.796 21.344 6.822 22.437 ; 
        RECT 6.688 21.344 6.714 22.437 ; 
        RECT 6.58 21.344 6.606 22.437 ; 
        RECT 6.472 21.344 6.498 22.437 ; 
        RECT 6.364 21.344 6.39 22.437 ; 
        RECT 6.256 21.344 6.282 22.437 ; 
        RECT 6.148 21.344 6.174 22.437 ; 
        RECT 6.04 21.344 6.066 22.437 ; 
        RECT 5.932 21.344 5.958 22.437 ; 
        RECT 5.824 21.344 5.85 22.437 ; 
        RECT 5.716 21.344 5.742 22.437 ; 
        RECT 5.608 21.344 5.634 22.437 ; 
        RECT 5.5 21.344 5.526 22.437 ; 
        RECT 5.392 21.344 5.418 22.437 ; 
        RECT 5.284 21.344 5.31 22.437 ; 
        RECT 5.176 21.344 5.202 22.437 ; 
        RECT 5.068 21.344 5.094 22.437 ; 
        RECT 4.96 21.344 4.986 22.437 ; 
        RECT 4.852 21.344 4.878 22.437 ; 
        RECT 4.744 21.344 4.77 22.437 ; 
        RECT 4.636 21.344 4.662 22.437 ; 
        RECT 4.528 21.344 4.554 22.437 ; 
        RECT 4.42 21.344 4.446 22.437 ; 
        RECT 4.312 21.344 4.338 22.437 ; 
        RECT 4.204 21.344 4.23 22.437 ; 
        RECT 4.096 21.344 4.122 22.437 ; 
        RECT 3.988 21.344 4.014 22.437 ; 
        RECT 3.88 21.344 3.906 22.437 ; 
        RECT 3.772 21.344 3.798 22.437 ; 
        RECT 3.664 21.344 3.69 22.437 ; 
        RECT 3.556 21.344 3.582 22.437 ; 
        RECT 3.448 21.344 3.474 22.437 ; 
        RECT 3.34 21.344 3.366 22.437 ; 
        RECT 3.232 21.344 3.258 22.437 ; 
        RECT 3.124 21.344 3.15 22.437 ; 
        RECT 3.016 21.344 3.042 22.437 ; 
        RECT 2.908 21.344 2.934 22.437 ; 
        RECT 2.8 21.344 2.826 22.437 ; 
        RECT 2.692 21.344 2.718 22.437 ; 
        RECT 2.584 21.344 2.61 22.437 ; 
        RECT 2.476 21.344 2.502 22.437 ; 
        RECT 2.368 21.344 2.394 22.437 ; 
        RECT 2.26 21.344 2.286 22.437 ; 
        RECT 2.152 21.344 2.178 22.437 ; 
        RECT 2.044 21.344 2.07 22.437 ; 
        RECT 1.936 21.344 1.962 22.437 ; 
        RECT 1.828 21.344 1.854 22.437 ; 
        RECT 1.72 21.344 1.746 22.437 ; 
        RECT 1.612 21.344 1.638 22.437 ; 
        RECT 1.504 21.344 1.53 22.437 ; 
        RECT 1.396 21.344 1.422 22.437 ; 
        RECT 1.288 21.344 1.314 22.437 ; 
        RECT 1.18 21.344 1.206 22.437 ; 
        RECT 1.072 21.344 1.098 22.437 ; 
        RECT 0.964 21.344 0.99 22.437 ; 
        RECT 0.856 21.344 0.882 22.437 ; 
        RECT 0.748 21.344 0.774 22.437 ; 
        RECT 0.64 21.344 0.666 22.437 ; 
        RECT 0.532 21.344 0.558 22.437 ; 
        RECT 0.424 21.344 0.45 22.437 ; 
        RECT 0.316 21.344 0.342 22.437 ; 
        RECT 0.208 21.344 0.234 22.437 ; 
        RECT 0.005 21.344 0.09 22.437 ; 
        RECT 8.641 22.424 8.769 23.517 ; 
        RECT 8.627 23.089 8.769 23.412 ; 
        RECT 8.479 22.816 8.541 23.517 ; 
        RECT 8.465 23.126 8.541 23.279 ; 
        RECT 8.479 22.424 8.505 23.517 ; 
        RECT 8.479 22.545 8.519 22.784 ; 
        RECT 8.479 22.424 8.541 22.513 ; 
        RECT 8.182 22.874 8.388 23.517 ; 
        RECT 8.362 22.424 8.388 23.517 ; 
        RECT 8.182 23.151 8.402 23.409 ; 
        RECT 8.182 22.424 8.28 23.517 ; 
        RECT 7.765 22.424 7.848 23.517 ; 
        RECT 7.765 22.512 7.862 23.448 ; 
        RECT 16.444 22.424 16.529 23.517 ; 
        RECT 16.3 22.424 16.326 23.517 ; 
        RECT 16.192 22.424 16.218 23.517 ; 
        RECT 16.084 22.424 16.11 23.517 ; 
        RECT 15.976 22.424 16.002 23.517 ; 
        RECT 15.868 22.424 15.894 23.517 ; 
        RECT 15.76 22.424 15.786 23.517 ; 
        RECT 15.652 22.424 15.678 23.517 ; 
        RECT 15.544 22.424 15.57 23.517 ; 
        RECT 15.436 22.424 15.462 23.517 ; 
        RECT 15.328 22.424 15.354 23.517 ; 
        RECT 15.22 22.424 15.246 23.517 ; 
        RECT 15.112 22.424 15.138 23.517 ; 
        RECT 15.004 22.424 15.03 23.517 ; 
        RECT 14.896 22.424 14.922 23.517 ; 
        RECT 14.788 22.424 14.814 23.517 ; 
        RECT 14.68 22.424 14.706 23.517 ; 
        RECT 14.572 22.424 14.598 23.517 ; 
        RECT 14.464 22.424 14.49 23.517 ; 
        RECT 14.356 22.424 14.382 23.517 ; 
        RECT 14.248 22.424 14.274 23.517 ; 
        RECT 14.14 22.424 14.166 23.517 ; 
        RECT 14.032 22.424 14.058 23.517 ; 
        RECT 13.924 22.424 13.95 23.517 ; 
        RECT 13.816 22.424 13.842 23.517 ; 
        RECT 13.708 22.424 13.734 23.517 ; 
        RECT 13.6 22.424 13.626 23.517 ; 
        RECT 13.492 22.424 13.518 23.517 ; 
        RECT 13.384 22.424 13.41 23.517 ; 
        RECT 13.276 22.424 13.302 23.517 ; 
        RECT 13.168 22.424 13.194 23.517 ; 
        RECT 13.06 22.424 13.086 23.517 ; 
        RECT 12.952 22.424 12.978 23.517 ; 
        RECT 12.844 22.424 12.87 23.517 ; 
        RECT 12.736 22.424 12.762 23.517 ; 
        RECT 12.628 22.424 12.654 23.517 ; 
        RECT 12.52 22.424 12.546 23.517 ; 
        RECT 12.412 22.424 12.438 23.517 ; 
        RECT 12.304 22.424 12.33 23.517 ; 
        RECT 12.196 22.424 12.222 23.517 ; 
        RECT 12.088 22.424 12.114 23.517 ; 
        RECT 11.98 22.424 12.006 23.517 ; 
        RECT 11.872 22.424 11.898 23.517 ; 
        RECT 11.764 22.424 11.79 23.517 ; 
        RECT 11.656 22.424 11.682 23.517 ; 
        RECT 11.548 22.424 11.574 23.517 ; 
        RECT 11.44 22.424 11.466 23.517 ; 
        RECT 11.332 22.424 11.358 23.517 ; 
        RECT 11.224 22.424 11.25 23.517 ; 
        RECT 11.116 22.424 11.142 23.517 ; 
        RECT 11.008 22.424 11.034 23.517 ; 
        RECT 10.9 22.424 10.926 23.517 ; 
        RECT 10.792 22.424 10.818 23.517 ; 
        RECT 10.684 22.424 10.71 23.517 ; 
        RECT 10.576 22.424 10.602 23.517 ; 
        RECT 10.468 22.424 10.494 23.517 ; 
        RECT 10.36 22.424 10.386 23.517 ; 
        RECT 10.252 22.424 10.278 23.517 ; 
        RECT 10.144 22.424 10.17 23.517 ; 
        RECT 10.036 22.424 10.062 23.517 ; 
        RECT 9.928 22.424 9.954 23.517 ; 
        RECT 9.82 22.424 9.846 23.517 ; 
        RECT 9.712 22.424 9.738 23.517 ; 
        RECT 9.604 22.424 9.63 23.517 ; 
        RECT 9.496 22.424 9.522 23.517 ; 
        RECT 9.388 22.424 9.414 23.517 ; 
        RECT 9.175 22.424 9.252 23.517 ; 
        RECT 7.282 22.424 7.359 23.517 ; 
        RECT 7.12 22.424 7.146 23.517 ; 
        RECT 7.012 22.424 7.038 23.517 ; 
        RECT 6.904 22.424 6.93 23.517 ; 
        RECT 6.796 22.424 6.822 23.517 ; 
        RECT 6.688 22.424 6.714 23.517 ; 
        RECT 6.58 22.424 6.606 23.517 ; 
        RECT 6.472 22.424 6.498 23.517 ; 
        RECT 6.364 22.424 6.39 23.517 ; 
        RECT 6.256 22.424 6.282 23.517 ; 
        RECT 6.148 22.424 6.174 23.517 ; 
        RECT 6.04 22.424 6.066 23.517 ; 
        RECT 5.932 22.424 5.958 23.517 ; 
        RECT 5.824 22.424 5.85 23.517 ; 
        RECT 5.716 22.424 5.742 23.517 ; 
        RECT 5.608 22.424 5.634 23.517 ; 
        RECT 5.5 22.424 5.526 23.517 ; 
        RECT 5.392 22.424 5.418 23.517 ; 
        RECT 5.284 22.424 5.31 23.517 ; 
        RECT 5.176 22.424 5.202 23.517 ; 
        RECT 5.068 22.424 5.094 23.517 ; 
        RECT 4.96 22.424 4.986 23.517 ; 
        RECT 4.852 22.424 4.878 23.517 ; 
        RECT 4.744 22.424 4.77 23.517 ; 
        RECT 4.636 22.424 4.662 23.517 ; 
        RECT 4.528 22.424 4.554 23.517 ; 
        RECT 4.42 22.424 4.446 23.517 ; 
        RECT 4.312 22.424 4.338 23.517 ; 
        RECT 4.204 22.424 4.23 23.517 ; 
        RECT 4.096 22.424 4.122 23.517 ; 
        RECT 3.988 22.424 4.014 23.517 ; 
        RECT 3.88 22.424 3.906 23.517 ; 
        RECT 3.772 22.424 3.798 23.517 ; 
        RECT 3.664 22.424 3.69 23.517 ; 
        RECT 3.556 22.424 3.582 23.517 ; 
        RECT 3.448 22.424 3.474 23.517 ; 
        RECT 3.34 22.424 3.366 23.517 ; 
        RECT 3.232 22.424 3.258 23.517 ; 
        RECT 3.124 22.424 3.15 23.517 ; 
        RECT 3.016 22.424 3.042 23.517 ; 
        RECT 2.908 22.424 2.934 23.517 ; 
        RECT 2.8 22.424 2.826 23.517 ; 
        RECT 2.692 22.424 2.718 23.517 ; 
        RECT 2.584 22.424 2.61 23.517 ; 
        RECT 2.476 22.424 2.502 23.517 ; 
        RECT 2.368 22.424 2.394 23.517 ; 
        RECT 2.26 22.424 2.286 23.517 ; 
        RECT 2.152 22.424 2.178 23.517 ; 
        RECT 2.044 22.424 2.07 23.517 ; 
        RECT 1.936 22.424 1.962 23.517 ; 
        RECT 1.828 22.424 1.854 23.517 ; 
        RECT 1.72 22.424 1.746 23.517 ; 
        RECT 1.612 22.424 1.638 23.517 ; 
        RECT 1.504 22.424 1.53 23.517 ; 
        RECT 1.396 22.424 1.422 23.517 ; 
        RECT 1.288 22.424 1.314 23.517 ; 
        RECT 1.18 22.424 1.206 23.517 ; 
        RECT 1.072 22.424 1.098 23.517 ; 
        RECT 0.964 22.424 0.99 23.517 ; 
        RECT 0.856 22.424 0.882 23.517 ; 
        RECT 0.748 22.424 0.774 23.517 ; 
        RECT 0.64 22.424 0.666 23.517 ; 
        RECT 0.532 22.424 0.558 23.517 ; 
        RECT 0.424 22.424 0.45 23.517 ; 
        RECT 0.316 22.424 0.342 23.517 ; 
        RECT 0.208 22.424 0.234 23.517 ; 
        RECT 0.005 22.424 0.09 23.517 ; 
        RECT 8.641 23.504 8.769 24.597 ; 
        RECT 8.627 24.169 8.769 24.492 ; 
        RECT 8.479 23.896 8.541 24.597 ; 
        RECT 8.465 24.206 8.541 24.359 ; 
        RECT 8.479 23.504 8.505 24.597 ; 
        RECT 8.479 23.625 8.519 23.864 ; 
        RECT 8.479 23.504 8.541 23.593 ; 
        RECT 8.182 23.954 8.388 24.597 ; 
        RECT 8.362 23.504 8.388 24.597 ; 
        RECT 8.182 24.231 8.402 24.489 ; 
        RECT 8.182 23.504 8.28 24.597 ; 
        RECT 7.765 23.504 7.848 24.597 ; 
        RECT 7.765 23.592 7.862 24.528 ; 
        RECT 16.444 23.504 16.529 24.597 ; 
        RECT 16.3 23.504 16.326 24.597 ; 
        RECT 16.192 23.504 16.218 24.597 ; 
        RECT 16.084 23.504 16.11 24.597 ; 
        RECT 15.976 23.504 16.002 24.597 ; 
        RECT 15.868 23.504 15.894 24.597 ; 
        RECT 15.76 23.504 15.786 24.597 ; 
        RECT 15.652 23.504 15.678 24.597 ; 
        RECT 15.544 23.504 15.57 24.597 ; 
        RECT 15.436 23.504 15.462 24.597 ; 
        RECT 15.328 23.504 15.354 24.597 ; 
        RECT 15.22 23.504 15.246 24.597 ; 
        RECT 15.112 23.504 15.138 24.597 ; 
        RECT 15.004 23.504 15.03 24.597 ; 
        RECT 14.896 23.504 14.922 24.597 ; 
        RECT 14.788 23.504 14.814 24.597 ; 
        RECT 14.68 23.504 14.706 24.597 ; 
        RECT 14.572 23.504 14.598 24.597 ; 
        RECT 14.464 23.504 14.49 24.597 ; 
        RECT 14.356 23.504 14.382 24.597 ; 
        RECT 14.248 23.504 14.274 24.597 ; 
        RECT 14.14 23.504 14.166 24.597 ; 
        RECT 14.032 23.504 14.058 24.597 ; 
        RECT 13.924 23.504 13.95 24.597 ; 
        RECT 13.816 23.504 13.842 24.597 ; 
        RECT 13.708 23.504 13.734 24.597 ; 
        RECT 13.6 23.504 13.626 24.597 ; 
        RECT 13.492 23.504 13.518 24.597 ; 
        RECT 13.384 23.504 13.41 24.597 ; 
        RECT 13.276 23.504 13.302 24.597 ; 
        RECT 13.168 23.504 13.194 24.597 ; 
        RECT 13.06 23.504 13.086 24.597 ; 
        RECT 12.952 23.504 12.978 24.597 ; 
        RECT 12.844 23.504 12.87 24.597 ; 
        RECT 12.736 23.504 12.762 24.597 ; 
        RECT 12.628 23.504 12.654 24.597 ; 
        RECT 12.52 23.504 12.546 24.597 ; 
        RECT 12.412 23.504 12.438 24.597 ; 
        RECT 12.304 23.504 12.33 24.597 ; 
        RECT 12.196 23.504 12.222 24.597 ; 
        RECT 12.088 23.504 12.114 24.597 ; 
        RECT 11.98 23.504 12.006 24.597 ; 
        RECT 11.872 23.504 11.898 24.597 ; 
        RECT 11.764 23.504 11.79 24.597 ; 
        RECT 11.656 23.504 11.682 24.597 ; 
        RECT 11.548 23.504 11.574 24.597 ; 
        RECT 11.44 23.504 11.466 24.597 ; 
        RECT 11.332 23.504 11.358 24.597 ; 
        RECT 11.224 23.504 11.25 24.597 ; 
        RECT 11.116 23.504 11.142 24.597 ; 
        RECT 11.008 23.504 11.034 24.597 ; 
        RECT 10.9 23.504 10.926 24.597 ; 
        RECT 10.792 23.504 10.818 24.597 ; 
        RECT 10.684 23.504 10.71 24.597 ; 
        RECT 10.576 23.504 10.602 24.597 ; 
        RECT 10.468 23.504 10.494 24.597 ; 
        RECT 10.36 23.504 10.386 24.597 ; 
        RECT 10.252 23.504 10.278 24.597 ; 
        RECT 10.144 23.504 10.17 24.597 ; 
        RECT 10.036 23.504 10.062 24.597 ; 
        RECT 9.928 23.504 9.954 24.597 ; 
        RECT 9.82 23.504 9.846 24.597 ; 
        RECT 9.712 23.504 9.738 24.597 ; 
        RECT 9.604 23.504 9.63 24.597 ; 
        RECT 9.496 23.504 9.522 24.597 ; 
        RECT 9.388 23.504 9.414 24.597 ; 
        RECT 9.175 23.504 9.252 24.597 ; 
        RECT 7.282 23.504 7.359 24.597 ; 
        RECT 7.12 23.504 7.146 24.597 ; 
        RECT 7.012 23.504 7.038 24.597 ; 
        RECT 6.904 23.504 6.93 24.597 ; 
        RECT 6.796 23.504 6.822 24.597 ; 
        RECT 6.688 23.504 6.714 24.597 ; 
        RECT 6.58 23.504 6.606 24.597 ; 
        RECT 6.472 23.504 6.498 24.597 ; 
        RECT 6.364 23.504 6.39 24.597 ; 
        RECT 6.256 23.504 6.282 24.597 ; 
        RECT 6.148 23.504 6.174 24.597 ; 
        RECT 6.04 23.504 6.066 24.597 ; 
        RECT 5.932 23.504 5.958 24.597 ; 
        RECT 5.824 23.504 5.85 24.597 ; 
        RECT 5.716 23.504 5.742 24.597 ; 
        RECT 5.608 23.504 5.634 24.597 ; 
        RECT 5.5 23.504 5.526 24.597 ; 
        RECT 5.392 23.504 5.418 24.597 ; 
        RECT 5.284 23.504 5.31 24.597 ; 
        RECT 5.176 23.504 5.202 24.597 ; 
        RECT 5.068 23.504 5.094 24.597 ; 
        RECT 4.96 23.504 4.986 24.597 ; 
        RECT 4.852 23.504 4.878 24.597 ; 
        RECT 4.744 23.504 4.77 24.597 ; 
        RECT 4.636 23.504 4.662 24.597 ; 
        RECT 4.528 23.504 4.554 24.597 ; 
        RECT 4.42 23.504 4.446 24.597 ; 
        RECT 4.312 23.504 4.338 24.597 ; 
        RECT 4.204 23.504 4.23 24.597 ; 
        RECT 4.096 23.504 4.122 24.597 ; 
        RECT 3.988 23.504 4.014 24.597 ; 
        RECT 3.88 23.504 3.906 24.597 ; 
        RECT 3.772 23.504 3.798 24.597 ; 
        RECT 3.664 23.504 3.69 24.597 ; 
        RECT 3.556 23.504 3.582 24.597 ; 
        RECT 3.448 23.504 3.474 24.597 ; 
        RECT 3.34 23.504 3.366 24.597 ; 
        RECT 3.232 23.504 3.258 24.597 ; 
        RECT 3.124 23.504 3.15 24.597 ; 
        RECT 3.016 23.504 3.042 24.597 ; 
        RECT 2.908 23.504 2.934 24.597 ; 
        RECT 2.8 23.504 2.826 24.597 ; 
        RECT 2.692 23.504 2.718 24.597 ; 
        RECT 2.584 23.504 2.61 24.597 ; 
        RECT 2.476 23.504 2.502 24.597 ; 
        RECT 2.368 23.504 2.394 24.597 ; 
        RECT 2.26 23.504 2.286 24.597 ; 
        RECT 2.152 23.504 2.178 24.597 ; 
        RECT 2.044 23.504 2.07 24.597 ; 
        RECT 1.936 23.504 1.962 24.597 ; 
        RECT 1.828 23.504 1.854 24.597 ; 
        RECT 1.72 23.504 1.746 24.597 ; 
        RECT 1.612 23.504 1.638 24.597 ; 
        RECT 1.504 23.504 1.53 24.597 ; 
        RECT 1.396 23.504 1.422 24.597 ; 
        RECT 1.288 23.504 1.314 24.597 ; 
        RECT 1.18 23.504 1.206 24.597 ; 
        RECT 1.072 23.504 1.098 24.597 ; 
        RECT 0.964 23.504 0.99 24.597 ; 
        RECT 0.856 23.504 0.882 24.597 ; 
        RECT 0.748 23.504 0.774 24.597 ; 
        RECT 0.64 23.504 0.666 24.597 ; 
        RECT 0.532 23.504 0.558 24.597 ; 
        RECT 0.424 23.504 0.45 24.597 ; 
        RECT 0.316 23.504 0.342 24.597 ; 
        RECT 0.208 23.504 0.234 24.597 ; 
        RECT 0.005 23.504 0.09 24.597 ; 
        RECT 8.641 24.584 8.769 25.677 ; 
        RECT 8.627 25.249 8.769 25.572 ; 
        RECT 8.479 24.976 8.541 25.677 ; 
        RECT 8.465 25.286 8.541 25.439 ; 
        RECT 8.479 24.584 8.505 25.677 ; 
        RECT 8.479 24.705 8.519 24.944 ; 
        RECT 8.479 24.584 8.541 24.673 ; 
        RECT 8.182 25.034 8.388 25.677 ; 
        RECT 8.362 24.584 8.388 25.677 ; 
        RECT 8.182 25.311 8.402 25.569 ; 
        RECT 8.182 24.584 8.28 25.677 ; 
        RECT 7.765 24.584 7.848 25.677 ; 
        RECT 7.765 24.672 7.862 25.608 ; 
        RECT 16.444 24.584 16.529 25.677 ; 
        RECT 16.3 24.584 16.326 25.677 ; 
        RECT 16.192 24.584 16.218 25.677 ; 
        RECT 16.084 24.584 16.11 25.677 ; 
        RECT 15.976 24.584 16.002 25.677 ; 
        RECT 15.868 24.584 15.894 25.677 ; 
        RECT 15.76 24.584 15.786 25.677 ; 
        RECT 15.652 24.584 15.678 25.677 ; 
        RECT 15.544 24.584 15.57 25.677 ; 
        RECT 15.436 24.584 15.462 25.677 ; 
        RECT 15.328 24.584 15.354 25.677 ; 
        RECT 15.22 24.584 15.246 25.677 ; 
        RECT 15.112 24.584 15.138 25.677 ; 
        RECT 15.004 24.584 15.03 25.677 ; 
        RECT 14.896 24.584 14.922 25.677 ; 
        RECT 14.788 24.584 14.814 25.677 ; 
        RECT 14.68 24.584 14.706 25.677 ; 
        RECT 14.572 24.584 14.598 25.677 ; 
        RECT 14.464 24.584 14.49 25.677 ; 
        RECT 14.356 24.584 14.382 25.677 ; 
        RECT 14.248 24.584 14.274 25.677 ; 
        RECT 14.14 24.584 14.166 25.677 ; 
        RECT 14.032 24.584 14.058 25.677 ; 
        RECT 13.924 24.584 13.95 25.677 ; 
        RECT 13.816 24.584 13.842 25.677 ; 
        RECT 13.708 24.584 13.734 25.677 ; 
        RECT 13.6 24.584 13.626 25.677 ; 
        RECT 13.492 24.584 13.518 25.677 ; 
        RECT 13.384 24.584 13.41 25.677 ; 
        RECT 13.276 24.584 13.302 25.677 ; 
        RECT 13.168 24.584 13.194 25.677 ; 
        RECT 13.06 24.584 13.086 25.677 ; 
        RECT 12.952 24.584 12.978 25.677 ; 
        RECT 12.844 24.584 12.87 25.677 ; 
        RECT 12.736 24.584 12.762 25.677 ; 
        RECT 12.628 24.584 12.654 25.677 ; 
        RECT 12.52 24.584 12.546 25.677 ; 
        RECT 12.412 24.584 12.438 25.677 ; 
        RECT 12.304 24.584 12.33 25.677 ; 
        RECT 12.196 24.584 12.222 25.677 ; 
        RECT 12.088 24.584 12.114 25.677 ; 
        RECT 11.98 24.584 12.006 25.677 ; 
        RECT 11.872 24.584 11.898 25.677 ; 
        RECT 11.764 24.584 11.79 25.677 ; 
        RECT 11.656 24.584 11.682 25.677 ; 
        RECT 11.548 24.584 11.574 25.677 ; 
        RECT 11.44 24.584 11.466 25.677 ; 
        RECT 11.332 24.584 11.358 25.677 ; 
        RECT 11.224 24.584 11.25 25.677 ; 
        RECT 11.116 24.584 11.142 25.677 ; 
        RECT 11.008 24.584 11.034 25.677 ; 
        RECT 10.9 24.584 10.926 25.677 ; 
        RECT 10.792 24.584 10.818 25.677 ; 
        RECT 10.684 24.584 10.71 25.677 ; 
        RECT 10.576 24.584 10.602 25.677 ; 
        RECT 10.468 24.584 10.494 25.677 ; 
        RECT 10.36 24.584 10.386 25.677 ; 
        RECT 10.252 24.584 10.278 25.677 ; 
        RECT 10.144 24.584 10.17 25.677 ; 
        RECT 10.036 24.584 10.062 25.677 ; 
        RECT 9.928 24.584 9.954 25.677 ; 
        RECT 9.82 24.584 9.846 25.677 ; 
        RECT 9.712 24.584 9.738 25.677 ; 
        RECT 9.604 24.584 9.63 25.677 ; 
        RECT 9.496 24.584 9.522 25.677 ; 
        RECT 9.388 24.584 9.414 25.677 ; 
        RECT 9.175 24.584 9.252 25.677 ; 
        RECT 7.282 24.584 7.359 25.677 ; 
        RECT 7.12 24.584 7.146 25.677 ; 
        RECT 7.012 24.584 7.038 25.677 ; 
        RECT 6.904 24.584 6.93 25.677 ; 
        RECT 6.796 24.584 6.822 25.677 ; 
        RECT 6.688 24.584 6.714 25.677 ; 
        RECT 6.58 24.584 6.606 25.677 ; 
        RECT 6.472 24.584 6.498 25.677 ; 
        RECT 6.364 24.584 6.39 25.677 ; 
        RECT 6.256 24.584 6.282 25.677 ; 
        RECT 6.148 24.584 6.174 25.677 ; 
        RECT 6.04 24.584 6.066 25.677 ; 
        RECT 5.932 24.584 5.958 25.677 ; 
        RECT 5.824 24.584 5.85 25.677 ; 
        RECT 5.716 24.584 5.742 25.677 ; 
        RECT 5.608 24.584 5.634 25.677 ; 
        RECT 5.5 24.584 5.526 25.677 ; 
        RECT 5.392 24.584 5.418 25.677 ; 
        RECT 5.284 24.584 5.31 25.677 ; 
        RECT 5.176 24.584 5.202 25.677 ; 
        RECT 5.068 24.584 5.094 25.677 ; 
        RECT 4.96 24.584 4.986 25.677 ; 
        RECT 4.852 24.584 4.878 25.677 ; 
        RECT 4.744 24.584 4.77 25.677 ; 
        RECT 4.636 24.584 4.662 25.677 ; 
        RECT 4.528 24.584 4.554 25.677 ; 
        RECT 4.42 24.584 4.446 25.677 ; 
        RECT 4.312 24.584 4.338 25.677 ; 
        RECT 4.204 24.584 4.23 25.677 ; 
        RECT 4.096 24.584 4.122 25.677 ; 
        RECT 3.988 24.584 4.014 25.677 ; 
        RECT 3.88 24.584 3.906 25.677 ; 
        RECT 3.772 24.584 3.798 25.677 ; 
        RECT 3.664 24.584 3.69 25.677 ; 
        RECT 3.556 24.584 3.582 25.677 ; 
        RECT 3.448 24.584 3.474 25.677 ; 
        RECT 3.34 24.584 3.366 25.677 ; 
        RECT 3.232 24.584 3.258 25.677 ; 
        RECT 3.124 24.584 3.15 25.677 ; 
        RECT 3.016 24.584 3.042 25.677 ; 
        RECT 2.908 24.584 2.934 25.677 ; 
        RECT 2.8 24.584 2.826 25.677 ; 
        RECT 2.692 24.584 2.718 25.677 ; 
        RECT 2.584 24.584 2.61 25.677 ; 
        RECT 2.476 24.584 2.502 25.677 ; 
        RECT 2.368 24.584 2.394 25.677 ; 
        RECT 2.26 24.584 2.286 25.677 ; 
        RECT 2.152 24.584 2.178 25.677 ; 
        RECT 2.044 24.584 2.07 25.677 ; 
        RECT 1.936 24.584 1.962 25.677 ; 
        RECT 1.828 24.584 1.854 25.677 ; 
        RECT 1.72 24.584 1.746 25.677 ; 
        RECT 1.612 24.584 1.638 25.677 ; 
        RECT 1.504 24.584 1.53 25.677 ; 
        RECT 1.396 24.584 1.422 25.677 ; 
        RECT 1.288 24.584 1.314 25.677 ; 
        RECT 1.18 24.584 1.206 25.677 ; 
        RECT 1.072 24.584 1.098 25.677 ; 
        RECT 0.964 24.584 0.99 25.677 ; 
        RECT 0.856 24.584 0.882 25.677 ; 
        RECT 0.748 24.584 0.774 25.677 ; 
        RECT 0.64 24.584 0.666 25.677 ; 
        RECT 0.532 24.584 0.558 25.677 ; 
        RECT 0.424 24.584 0.45 25.677 ; 
        RECT 0.316 24.584 0.342 25.677 ; 
        RECT 0.208 24.584 0.234 25.677 ; 
        RECT 0.005 24.584 0.09 25.677 ; 
        RECT 8.641 25.664 8.769 26.757 ; 
        RECT 8.627 26.329 8.769 26.652 ; 
        RECT 8.479 26.056 8.541 26.757 ; 
        RECT 8.465 26.366 8.541 26.519 ; 
        RECT 8.479 25.664 8.505 26.757 ; 
        RECT 8.479 25.785 8.519 26.024 ; 
        RECT 8.479 25.664 8.541 25.753 ; 
        RECT 8.182 26.114 8.388 26.757 ; 
        RECT 8.362 25.664 8.388 26.757 ; 
        RECT 8.182 26.391 8.402 26.649 ; 
        RECT 8.182 25.664 8.28 26.757 ; 
        RECT 7.765 25.664 7.848 26.757 ; 
        RECT 7.765 25.752 7.862 26.688 ; 
        RECT 16.444 25.664 16.529 26.757 ; 
        RECT 16.3 25.664 16.326 26.757 ; 
        RECT 16.192 25.664 16.218 26.757 ; 
        RECT 16.084 25.664 16.11 26.757 ; 
        RECT 15.976 25.664 16.002 26.757 ; 
        RECT 15.868 25.664 15.894 26.757 ; 
        RECT 15.76 25.664 15.786 26.757 ; 
        RECT 15.652 25.664 15.678 26.757 ; 
        RECT 15.544 25.664 15.57 26.757 ; 
        RECT 15.436 25.664 15.462 26.757 ; 
        RECT 15.328 25.664 15.354 26.757 ; 
        RECT 15.22 25.664 15.246 26.757 ; 
        RECT 15.112 25.664 15.138 26.757 ; 
        RECT 15.004 25.664 15.03 26.757 ; 
        RECT 14.896 25.664 14.922 26.757 ; 
        RECT 14.788 25.664 14.814 26.757 ; 
        RECT 14.68 25.664 14.706 26.757 ; 
        RECT 14.572 25.664 14.598 26.757 ; 
        RECT 14.464 25.664 14.49 26.757 ; 
        RECT 14.356 25.664 14.382 26.757 ; 
        RECT 14.248 25.664 14.274 26.757 ; 
        RECT 14.14 25.664 14.166 26.757 ; 
        RECT 14.032 25.664 14.058 26.757 ; 
        RECT 13.924 25.664 13.95 26.757 ; 
        RECT 13.816 25.664 13.842 26.757 ; 
        RECT 13.708 25.664 13.734 26.757 ; 
        RECT 13.6 25.664 13.626 26.757 ; 
        RECT 13.492 25.664 13.518 26.757 ; 
        RECT 13.384 25.664 13.41 26.757 ; 
        RECT 13.276 25.664 13.302 26.757 ; 
        RECT 13.168 25.664 13.194 26.757 ; 
        RECT 13.06 25.664 13.086 26.757 ; 
        RECT 12.952 25.664 12.978 26.757 ; 
        RECT 12.844 25.664 12.87 26.757 ; 
        RECT 12.736 25.664 12.762 26.757 ; 
        RECT 12.628 25.664 12.654 26.757 ; 
        RECT 12.52 25.664 12.546 26.757 ; 
        RECT 12.412 25.664 12.438 26.757 ; 
        RECT 12.304 25.664 12.33 26.757 ; 
        RECT 12.196 25.664 12.222 26.757 ; 
        RECT 12.088 25.664 12.114 26.757 ; 
        RECT 11.98 25.664 12.006 26.757 ; 
        RECT 11.872 25.664 11.898 26.757 ; 
        RECT 11.764 25.664 11.79 26.757 ; 
        RECT 11.656 25.664 11.682 26.757 ; 
        RECT 11.548 25.664 11.574 26.757 ; 
        RECT 11.44 25.664 11.466 26.757 ; 
        RECT 11.332 25.664 11.358 26.757 ; 
        RECT 11.224 25.664 11.25 26.757 ; 
        RECT 11.116 25.664 11.142 26.757 ; 
        RECT 11.008 25.664 11.034 26.757 ; 
        RECT 10.9 25.664 10.926 26.757 ; 
        RECT 10.792 25.664 10.818 26.757 ; 
        RECT 10.684 25.664 10.71 26.757 ; 
        RECT 10.576 25.664 10.602 26.757 ; 
        RECT 10.468 25.664 10.494 26.757 ; 
        RECT 10.36 25.664 10.386 26.757 ; 
        RECT 10.252 25.664 10.278 26.757 ; 
        RECT 10.144 25.664 10.17 26.757 ; 
        RECT 10.036 25.664 10.062 26.757 ; 
        RECT 9.928 25.664 9.954 26.757 ; 
        RECT 9.82 25.664 9.846 26.757 ; 
        RECT 9.712 25.664 9.738 26.757 ; 
        RECT 9.604 25.664 9.63 26.757 ; 
        RECT 9.496 25.664 9.522 26.757 ; 
        RECT 9.388 25.664 9.414 26.757 ; 
        RECT 9.175 25.664 9.252 26.757 ; 
        RECT 7.282 25.664 7.359 26.757 ; 
        RECT 7.12 25.664 7.146 26.757 ; 
        RECT 7.012 25.664 7.038 26.757 ; 
        RECT 6.904 25.664 6.93 26.757 ; 
        RECT 6.796 25.664 6.822 26.757 ; 
        RECT 6.688 25.664 6.714 26.757 ; 
        RECT 6.58 25.664 6.606 26.757 ; 
        RECT 6.472 25.664 6.498 26.757 ; 
        RECT 6.364 25.664 6.39 26.757 ; 
        RECT 6.256 25.664 6.282 26.757 ; 
        RECT 6.148 25.664 6.174 26.757 ; 
        RECT 6.04 25.664 6.066 26.757 ; 
        RECT 5.932 25.664 5.958 26.757 ; 
        RECT 5.824 25.664 5.85 26.757 ; 
        RECT 5.716 25.664 5.742 26.757 ; 
        RECT 5.608 25.664 5.634 26.757 ; 
        RECT 5.5 25.664 5.526 26.757 ; 
        RECT 5.392 25.664 5.418 26.757 ; 
        RECT 5.284 25.664 5.31 26.757 ; 
        RECT 5.176 25.664 5.202 26.757 ; 
        RECT 5.068 25.664 5.094 26.757 ; 
        RECT 4.96 25.664 4.986 26.757 ; 
        RECT 4.852 25.664 4.878 26.757 ; 
        RECT 4.744 25.664 4.77 26.757 ; 
        RECT 4.636 25.664 4.662 26.757 ; 
        RECT 4.528 25.664 4.554 26.757 ; 
        RECT 4.42 25.664 4.446 26.757 ; 
        RECT 4.312 25.664 4.338 26.757 ; 
        RECT 4.204 25.664 4.23 26.757 ; 
        RECT 4.096 25.664 4.122 26.757 ; 
        RECT 3.988 25.664 4.014 26.757 ; 
        RECT 3.88 25.664 3.906 26.757 ; 
        RECT 3.772 25.664 3.798 26.757 ; 
        RECT 3.664 25.664 3.69 26.757 ; 
        RECT 3.556 25.664 3.582 26.757 ; 
        RECT 3.448 25.664 3.474 26.757 ; 
        RECT 3.34 25.664 3.366 26.757 ; 
        RECT 3.232 25.664 3.258 26.757 ; 
        RECT 3.124 25.664 3.15 26.757 ; 
        RECT 3.016 25.664 3.042 26.757 ; 
        RECT 2.908 25.664 2.934 26.757 ; 
        RECT 2.8 25.664 2.826 26.757 ; 
        RECT 2.692 25.664 2.718 26.757 ; 
        RECT 2.584 25.664 2.61 26.757 ; 
        RECT 2.476 25.664 2.502 26.757 ; 
        RECT 2.368 25.664 2.394 26.757 ; 
        RECT 2.26 25.664 2.286 26.757 ; 
        RECT 2.152 25.664 2.178 26.757 ; 
        RECT 2.044 25.664 2.07 26.757 ; 
        RECT 1.936 25.664 1.962 26.757 ; 
        RECT 1.828 25.664 1.854 26.757 ; 
        RECT 1.72 25.664 1.746 26.757 ; 
        RECT 1.612 25.664 1.638 26.757 ; 
        RECT 1.504 25.664 1.53 26.757 ; 
        RECT 1.396 25.664 1.422 26.757 ; 
        RECT 1.288 25.664 1.314 26.757 ; 
        RECT 1.18 25.664 1.206 26.757 ; 
        RECT 1.072 25.664 1.098 26.757 ; 
        RECT 0.964 25.664 0.99 26.757 ; 
        RECT 0.856 25.664 0.882 26.757 ; 
        RECT 0.748 25.664 0.774 26.757 ; 
        RECT 0.64 25.664 0.666 26.757 ; 
        RECT 0.532 25.664 0.558 26.757 ; 
        RECT 0.424 25.664 0.45 26.757 ; 
        RECT 0.316 25.664 0.342 26.757 ; 
        RECT 0.208 25.664 0.234 26.757 ; 
        RECT 0.005 25.664 0.09 26.757 ; 
        RECT 8.641 26.744 8.769 27.837 ; 
        RECT 8.627 27.409 8.769 27.732 ; 
        RECT 8.479 27.136 8.541 27.837 ; 
        RECT 8.465 27.446 8.541 27.599 ; 
        RECT 8.479 26.744 8.505 27.837 ; 
        RECT 8.479 26.865 8.519 27.104 ; 
        RECT 8.479 26.744 8.541 26.833 ; 
        RECT 8.182 27.194 8.388 27.837 ; 
        RECT 8.362 26.744 8.388 27.837 ; 
        RECT 8.182 27.471 8.402 27.729 ; 
        RECT 8.182 26.744 8.28 27.837 ; 
        RECT 7.765 26.744 7.848 27.837 ; 
        RECT 7.765 26.832 7.862 27.768 ; 
        RECT 16.444 26.744 16.529 27.837 ; 
        RECT 16.3 26.744 16.326 27.837 ; 
        RECT 16.192 26.744 16.218 27.837 ; 
        RECT 16.084 26.744 16.11 27.837 ; 
        RECT 15.976 26.744 16.002 27.837 ; 
        RECT 15.868 26.744 15.894 27.837 ; 
        RECT 15.76 26.744 15.786 27.837 ; 
        RECT 15.652 26.744 15.678 27.837 ; 
        RECT 15.544 26.744 15.57 27.837 ; 
        RECT 15.436 26.744 15.462 27.837 ; 
        RECT 15.328 26.744 15.354 27.837 ; 
        RECT 15.22 26.744 15.246 27.837 ; 
        RECT 15.112 26.744 15.138 27.837 ; 
        RECT 15.004 26.744 15.03 27.837 ; 
        RECT 14.896 26.744 14.922 27.837 ; 
        RECT 14.788 26.744 14.814 27.837 ; 
        RECT 14.68 26.744 14.706 27.837 ; 
        RECT 14.572 26.744 14.598 27.837 ; 
        RECT 14.464 26.744 14.49 27.837 ; 
        RECT 14.356 26.744 14.382 27.837 ; 
        RECT 14.248 26.744 14.274 27.837 ; 
        RECT 14.14 26.744 14.166 27.837 ; 
        RECT 14.032 26.744 14.058 27.837 ; 
        RECT 13.924 26.744 13.95 27.837 ; 
        RECT 13.816 26.744 13.842 27.837 ; 
        RECT 13.708 26.744 13.734 27.837 ; 
        RECT 13.6 26.744 13.626 27.837 ; 
        RECT 13.492 26.744 13.518 27.837 ; 
        RECT 13.384 26.744 13.41 27.837 ; 
        RECT 13.276 26.744 13.302 27.837 ; 
        RECT 13.168 26.744 13.194 27.837 ; 
        RECT 13.06 26.744 13.086 27.837 ; 
        RECT 12.952 26.744 12.978 27.837 ; 
        RECT 12.844 26.744 12.87 27.837 ; 
        RECT 12.736 26.744 12.762 27.837 ; 
        RECT 12.628 26.744 12.654 27.837 ; 
        RECT 12.52 26.744 12.546 27.837 ; 
        RECT 12.412 26.744 12.438 27.837 ; 
        RECT 12.304 26.744 12.33 27.837 ; 
        RECT 12.196 26.744 12.222 27.837 ; 
        RECT 12.088 26.744 12.114 27.837 ; 
        RECT 11.98 26.744 12.006 27.837 ; 
        RECT 11.872 26.744 11.898 27.837 ; 
        RECT 11.764 26.744 11.79 27.837 ; 
        RECT 11.656 26.744 11.682 27.837 ; 
        RECT 11.548 26.744 11.574 27.837 ; 
        RECT 11.44 26.744 11.466 27.837 ; 
        RECT 11.332 26.744 11.358 27.837 ; 
        RECT 11.224 26.744 11.25 27.837 ; 
        RECT 11.116 26.744 11.142 27.837 ; 
        RECT 11.008 26.744 11.034 27.837 ; 
        RECT 10.9 26.744 10.926 27.837 ; 
        RECT 10.792 26.744 10.818 27.837 ; 
        RECT 10.684 26.744 10.71 27.837 ; 
        RECT 10.576 26.744 10.602 27.837 ; 
        RECT 10.468 26.744 10.494 27.837 ; 
        RECT 10.36 26.744 10.386 27.837 ; 
        RECT 10.252 26.744 10.278 27.837 ; 
        RECT 10.144 26.744 10.17 27.837 ; 
        RECT 10.036 26.744 10.062 27.837 ; 
        RECT 9.928 26.744 9.954 27.837 ; 
        RECT 9.82 26.744 9.846 27.837 ; 
        RECT 9.712 26.744 9.738 27.837 ; 
        RECT 9.604 26.744 9.63 27.837 ; 
        RECT 9.496 26.744 9.522 27.837 ; 
        RECT 9.388 26.744 9.414 27.837 ; 
        RECT 9.175 26.744 9.252 27.837 ; 
        RECT 7.282 26.744 7.359 27.837 ; 
        RECT 7.12 26.744 7.146 27.837 ; 
        RECT 7.012 26.744 7.038 27.837 ; 
        RECT 6.904 26.744 6.93 27.837 ; 
        RECT 6.796 26.744 6.822 27.837 ; 
        RECT 6.688 26.744 6.714 27.837 ; 
        RECT 6.58 26.744 6.606 27.837 ; 
        RECT 6.472 26.744 6.498 27.837 ; 
        RECT 6.364 26.744 6.39 27.837 ; 
        RECT 6.256 26.744 6.282 27.837 ; 
        RECT 6.148 26.744 6.174 27.837 ; 
        RECT 6.04 26.744 6.066 27.837 ; 
        RECT 5.932 26.744 5.958 27.837 ; 
        RECT 5.824 26.744 5.85 27.837 ; 
        RECT 5.716 26.744 5.742 27.837 ; 
        RECT 5.608 26.744 5.634 27.837 ; 
        RECT 5.5 26.744 5.526 27.837 ; 
        RECT 5.392 26.744 5.418 27.837 ; 
        RECT 5.284 26.744 5.31 27.837 ; 
        RECT 5.176 26.744 5.202 27.837 ; 
        RECT 5.068 26.744 5.094 27.837 ; 
        RECT 4.96 26.744 4.986 27.837 ; 
        RECT 4.852 26.744 4.878 27.837 ; 
        RECT 4.744 26.744 4.77 27.837 ; 
        RECT 4.636 26.744 4.662 27.837 ; 
        RECT 4.528 26.744 4.554 27.837 ; 
        RECT 4.42 26.744 4.446 27.837 ; 
        RECT 4.312 26.744 4.338 27.837 ; 
        RECT 4.204 26.744 4.23 27.837 ; 
        RECT 4.096 26.744 4.122 27.837 ; 
        RECT 3.988 26.744 4.014 27.837 ; 
        RECT 3.88 26.744 3.906 27.837 ; 
        RECT 3.772 26.744 3.798 27.837 ; 
        RECT 3.664 26.744 3.69 27.837 ; 
        RECT 3.556 26.744 3.582 27.837 ; 
        RECT 3.448 26.744 3.474 27.837 ; 
        RECT 3.34 26.744 3.366 27.837 ; 
        RECT 3.232 26.744 3.258 27.837 ; 
        RECT 3.124 26.744 3.15 27.837 ; 
        RECT 3.016 26.744 3.042 27.837 ; 
        RECT 2.908 26.744 2.934 27.837 ; 
        RECT 2.8 26.744 2.826 27.837 ; 
        RECT 2.692 26.744 2.718 27.837 ; 
        RECT 2.584 26.744 2.61 27.837 ; 
        RECT 2.476 26.744 2.502 27.837 ; 
        RECT 2.368 26.744 2.394 27.837 ; 
        RECT 2.26 26.744 2.286 27.837 ; 
        RECT 2.152 26.744 2.178 27.837 ; 
        RECT 2.044 26.744 2.07 27.837 ; 
        RECT 1.936 26.744 1.962 27.837 ; 
        RECT 1.828 26.744 1.854 27.837 ; 
        RECT 1.72 26.744 1.746 27.837 ; 
        RECT 1.612 26.744 1.638 27.837 ; 
        RECT 1.504 26.744 1.53 27.837 ; 
        RECT 1.396 26.744 1.422 27.837 ; 
        RECT 1.288 26.744 1.314 27.837 ; 
        RECT 1.18 26.744 1.206 27.837 ; 
        RECT 1.072 26.744 1.098 27.837 ; 
        RECT 0.964 26.744 0.99 27.837 ; 
        RECT 0.856 26.744 0.882 27.837 ; 
        RECT 0.748 26.744 0.774 27.837 ; 
        RECT 0.64 26.744 0.666 27.837 ; 
        RECT 0.532 26.744 0.558 27.837 ; 
        RECT 0.424 26.744 0.45 27.837 ; 
        RECT 0.316 26.744 0.342 27.837 ; 
        RECT 0.208 26.744 0.234 27.837 ; 
        RECT 0.005 26.744 0.09 27.837 ; 
        RECT 8.641 27.824 8.769 28.917 ; 
        RECT 8.627 28.489 8.769 28.812 ; 
        RECT 8.479 28.216 8.541 28.917 ; 
        RECT 8.465 28.526 8.541 28.679 ; 
        RECT 8.479 27.824 8.505 28.917 ; 
        RECT 8.479 27.945 8.519 28.184 ; 
        RECT 8.479 27.824 8.541 27.913 ; 
        RECT 8.182 28.274 8.388 28.917 ; 
        RECT 8.362 27.824 8.388 28.917 ; 
        RECT 8.182 28.551 8.402 28.809 ; 
        RECT 8.182 27.824 8.28 28.917 ; 
        RECT 7.765 27.824 7.848 28.917 ; 
        RECT 7.765 27.912 7.862 28.848 ; 
        RECT 16.444 27.824 16.529 28.917 ; 
        RECT 16.3 27.824 16.326 28.917 ; 
        RECT 16.192 27.824 16.218 28.917 ; 
        RECT 16.084 27.824 16.11 28.917 ; 
        RECT 15.976 27.824 16.002 28.917 ; 
        RECT 15.868 27.824 15.894 28.917 ; 
        RECT 15.76 27.824 15.786 28.917 ; 
        RECT 15.652 27.824 15.678 28.917 ; 
        RECT 15.544 27.824 15.57 28.917 ; 
        RECT 15.436 27.824 15.462 28.917 ; 
        RECT 15.328 27.824 15.354 28.917 ; 
        RECT 15.22 27.824 15.246 28.917 ; 
        RECT 15.112 27.824 15.138 28.917 ; 
        RECT 15.004 27.824 15.03 28.917 ; 
        RECT 14.896 27.824 14.922 28.917 ; 
        RECT 14.788 27.824 14.814 28.917 ; 
        RECT 14.68 27.824 14.706 28.917 ; 
        RECT 14.572 27.824 14.598 28.917 ; 
        RECT 14.464 27.824 14.49 28.917 ; 
        RECT 14.356 27.824 14.382 28.917 ; 
        RECT 14.248 27.824 14.274 28.917 ; 
        RECT 14.14 27.824 14.166 28.917 ; 
        RECT 14.032 27.824 14.058 28.917 ; 
        RECT 13.924 27.824 13.95 28.917 ; 
        RECT 13.816 27.824 13.842 28.917 ; 
        RECT 13.708 27.824 13.734 28.917 ; 
        RECT 13.6 27.824 13.626 28.917 ; 
        RECT 13.492 27.824 13.518 28.917 ; 
        RECT 13.384 27.824 13.41 28.917 ; 
        RECT 13.276 27.824 13.302 28.917 ; 
        RECT 13.168 27.824 13.194 28.917 ; 
        RECT 13.06 27.824 13.086 28.917 ; 
        RECT 12.952 27.824 12.978 28.917 ; 
        RECT 12.844 27.824 12.87 28.917 ; 
        RECT 12.736 27.824 12.762 28.917 ; 
        RECT 12.628 27.824 12.654 28.917 ; 
        RECT 12.52 27.824 12.546 28.917 ; 
        RECT 12.412 27.824 12.438 28.917 ; 
        RECT 12.304 27.824 12.33 28.917 ; 
        RECT 12.196 27.824 12.222 28.917 ; 
        RECT 12.088 27.824 12.114 28.917 ; 
        RECT 11.98 27.824 12.006 28.917 ; 
        RECT 11.872 27.824 11.898 28.917 ; 
        RECT 11.764 27.824 11.79 28.917 ; 
        RECT 11.656 27.824 11.682 28.917 ; 
        RECT 11.548 27.824 11.574 28.917 ; 
        RECT 11.44 27.824 11.466 28.917 ; 
        RECT 11.332 27.824 11.358 28.917 ; 
        RECT 11.224 27.824 11.25 28.917 ; 
        RECT 11.116 27.824 11.142 28.917 ; 
        RECT 11.008 27.824 11.034 28.917 ; 
        RECT 10.9 27.824 10.926 28.917 ; 
        RECT 10.792 27.824 10.818 28.917 ; 
        RECT 10.684 27.824 10.71 28.917 ; 
        RECT 10.576 27.824 10.602 28.917 ; 
        RECT 10.468 27.824 10.494 28.917 ; 
        RECT 10.36 27.824 10.386 28.917 ; 
        RECT 10.252 27.824 10.278 28.917 ; 
        RECT 10.144 27.824 10.17 28.917 ; 
        RECT 10.036 27.824 10.062 28.917 ; 
        RECT 9.928 27.824 9.954 28.917 ; 
        RECT 9.82 27.824 9.846 28.917 ; 
        RECT 9.712 27.824 9.738 28.917 ; 
        RECT 9.604 27.824 9.63 28.917 ; 
        RECT 9.496 27.824 9.522 28.917 ; 
        RECT 9.388 27.824 9.414 28.917 ; 
        RECT 9.175 27.824 9.252 28.917 ; 
        RECT 7.282 27.824 7.359 28.917 ; 
        RECT 7.12 27.824 7.146 28.917 ; 
        RECT 7.012 27.824 7.038 28.917 ; 
        RECT 6.904 27.824 6.93 28.917 ; 
        RECT 6.796 27.824 6.822 28.917 ; 
        RECT 6.688 27.824 6.714 28.917 ; 
        RECT 6.58 27.824 6.606 28.917 ; 
        RECT 6.472 27.824 6.498 28.917 ; 
        RECT 6.364 27.824 6.39 28.917 ; 
        RECT 6.256 27.824 6.282 28.917 ; 
        RECT 6.148 27.824 6.174 28.917 ; 
        RECT 6.04 27.824 6.066 28.917 ; 
        RECT 5.932 27.824 5.958 28.917 ; 
        RECT 5.824 27.824 5.85 28.917 ; 
        RECT 5.716 27.824 5.742 28.917 ; 
        RECT 5.608 27.824 5.634 28.917 ; 
        RECT 5.5 27.824 5.526 28.917 ; 
        RECT 5.392 27.824 5.418 28.917 ; 
        RECT 5.284 27.824 5.31 28.917 ; 
        RECT 5.176 27.824 5.202 28.917 ; 
        RECT 5.068 27.824 5.094 28.917 ; 
        RECT 4.96 27.824 4.986 28.917 ; 
        RECT 4.852 27.824 4.878 28.917 ; 
        RECT 4.744 27.824 4.77 28.917 ; 
        RECT 4.636 27.824 4.662 28.917 ; 
        RECT 4.528 27.824 4.554 28.917 ; 
        RECT 4.42 27.824 4.446 28.917 ; 
        RECT 4.312 27.824 4.338 28.917 ; 
        RECT 4.204 27.824 4.23 28.917 ; 
        RECT 4.096 27.824 4.122 28.917 ; 
        RECT 3.988 27.824 4.014 28.917 ; 
        RECT 3.88 27.824 3.906 28.917 ; 
        RECT 3.772 27.824 3.798 28.917 ; 
        RECT 3.664 27.824 3.69 28.917 ; 
        RECT 3.556 27.824 3.582 28.917 ; 
        RECT 3.448 27.824 3.474 28.917 ; 
        RECT 3.34 27.824 3.366 28.917 ; 
        RECT 3.232 27.824 3.258 28.917 ; 
        RECT 3.124 27.824 3.15 28.917 ; 
        RECT 3.016 27.824 3.042 28.917 ; 
        RECT 2.908 27.824 2.934 28.917 ; 
        RECT 2.8 27.824 2.826 28.917 ; 
        RECT 2.692 27.824 2.718 28.917 ; 
        RECT 2.584 27.824 2.61 28.917 ; 
        RECT 2.476 27.824 2.502 28.917 ; 
        RECT 2.368 27.824 2.394 28.917 ; 
        RECT 2.26 27.824 2.286 28.917 ; 
        RECT 2.152 27.824 2.178 28.917 ; 
        RECT 2.044 27.824 2.07 28.917 ; 
        RECT 1.936 27.824 1.962 28.917 ; 
        RECT 1.828 27.824 1.854 28.917 ; 
        RECT 1.72 27.824 1.746 28.917 ; 
        RECT 1.612 27.824 1.638 28.917 ; 
        RECT 1.504 27.824 1.53 28.917 ; 
        RECT 1.396 27.824 1.422 28.917 ; 
        RECT 1.288 27.824 1.314 28.917 ; 
        RECT 1.18 27.824 1.206 28.917 ; 
        RECT 1.072 27.824 1.098 28.917 ; 
        RECT 0.964 27.824 0.99 28.917 ; 
        RECT 0.856 27.824 0.882 28.917 ; 
        RECT 0.748 27.824 0.774 28.917 ; 
        RECT 0.64 27.824 0.666 28.917 ; 
        RECT 0.532 27.824 0.558 28.917 ; 
        RECT 0.424 27.824 0.45 28.917 ; 
        RECT 0.316 27.824 0.342 28.917 ; 
        RECT 0.208 27.824 0.234 28.917 ; 
        RECT 0.005 27.824 0.09 28.917 ; 
        RECT 8.641 28.904 8.769 29.997 ; 
        RECT 8.627 29.569 8.769 29.892 ; 
        RECT 8.479 29.296 8.541 29.997 ; 
        RECT 8.465 29.606 8.541 29.759 ; 
        RECT 8.479 28.904 8.505 29.997 ; 
        RECT 8.479 29.025 8.519 29.264 ; 
        RECT 8.479 28.904 8.541 28.993 ; 
        RECT 8.182 29.354 8.388 29.997 ; 
        RECT 8.362 28.904 8.388 29.997 ; 
        RECT 8.182 29.631 8.402 29.889 ; 
        RECT 8.182 28.904 8.28 29.997 ; 
        RECT 7.765 28.904 7.848 29.997 ; 
        RECT 7.765 28.992 7.862 29.928 ; 
        RECT 16.444 28.904 16.529 29.997 ; 
        RECT 16.3 28.904 16.326 29.997 ; 
        RECT 16.192 28.904 16.218 29.997 ; 
        RECT 16.084 28.904 16.11 29.997 ; 
        RECT 15.976 28.904 16.002 29.997 ; 
        RECT 15.868 28.904 15.894 29.997 ; 
        RECT 15.76 28.904 15.786 29.997 ; 
        RECT 15.652 28.904 15.678 29.997 ; 
        RECT 15.544 28.904 15.57 29.997 ; 
        RECT 15.436 28.904 15.462 29.997 ; 
        RECT 15.328 28.904 15.354 29.997 ; 
        RECT 15.22 28.904 15.246 29.997 ; 
        RECT 15.112 28.904 15.138 29.997 ; 
        RECT 15.004 28.904 15.03 29.997 ; 
        RECT 14.896 28.904 14.922 29.997 ; 
        RECT 14.788 28.904 14.814 29.997 ; 
        RECT 14.68 28.904 14.706 29.997 ; 
        RECT 14.572 28.904 14.598 29.997 ; 
        RECT 14.464 28.904 14.49 29.997 ; 
        RECT 14.356 28.904 14.382 29.997 ; 
        RECT 14.248 28.904 14.274 29.997 ; 
        RECT 14.14 28.904 14.166 29.997 ; 
        RECT 14.032 28.904 14.058 29.997 ; 
        RECT 13.924 28.904 13.95 29.997 ; 
        RECT 13.816 28.904 13.842 29.997 ; 
        RECT 13.708 28.904 13.734 29.997 ; 
        RECT 13.6 28.904 13.626 29.997 ; 
        RECT 13.492 28.904 13.518 29.997 ; 
        RECT 13.384 28.904 13.41 29.997 ; 
        RECT 13.276 28.904 13.302 29.997 ; 
        RECT 13.168 28.904 13.194 29.997 ; 
        RECT 13.06 28.904 13.086 29.997 ; 
        RECT 12.952 28.904 12.978 29.997 ; 
        RECT 12.844 28.904 12.87 29.997 ; 
        RECT 12.736 28.904 12.762 29.997 ; 
        RECT 12.628 28.904 12.654 29.997 ; 
        RECT 12.52 28.904 12.546 29.997 ; 
        RECT 12.412 28.904 12.438 29.997 ; 
        RECT 12.304 28.904 12.33 29.997 ; 
        RECT 12.196 28.904 12.222 29.997 ; 
        RECT 12.088 28.904 12.114 29.997 ; 
        RECT 11.98 28.904 12.006 29.997 ; 
        RECT 11.872 28.904 11.898 29.997 ; 
        RECT 11.764 28.904 11.79 29.997 ; 
        RECT 11.656 28.904 11.682 29.997 ; 
        RECT 11.548 28.904 11.574 29.997 ; 
        RECT 11.44 28.904 11.466 29.997 ; 
        RECT 11.332 28.904 11.358 29.997 ; 
        RECT 11.224 28.904 11.25 29.997 ; 
        RECT 11.116 28.904 11.142 29.997 ; 
        RECT 11.008 28.904 11.034 29.997 ; 
        RECT 10.9 28.904 10.926 29.997 ; 
        RECT 10.792 28.904 10.818 29.997 ; 
        RECT 10.684 28.904 10.71 29.997 ; 
        RECT 10.576 28.904 10.602 29.997 ; 
        RECT 10.468 28.904 10.494 29.997 ; 
        RECT 10.36 28.904 10.386 29.997 ; 
        RECT 10.252 28.904 10.278 29.997 ; 
        RECT 10.144 28.904 10.17 29.997 ; 
        RECT 10.036 28.904 10.062 29.997 ; 
        RECT 9.928 28.904 9.954 29.997 ; 
        RECT 9.82 28.904 9.846 29.997 ; 
        RECT 9.712 28.904 9.738 29.997 ; 
        RECT 9.604 28.904 9.63 29.997 ; 
        RECT 9.496 28.904 9.522 29.997 ; 
        RECT 9.388 28.904 9.414 29.997 ; 
        RECT 9.175 28.904 9.252 29.997 ; 
        RECT 7.282 28.904 7.359 29.997 ; 
        RECT 7.12 28.904 7.146 29.997 ; 
        RECT 7.012 28.904 7.038 29.997 ; 
        RECT 6.904 28.904 6.93 29.997 ; 
        RECT 6.796 28.904 6.822 29.997 ; 
        RECT 6.688 28.904 6.714 29.997 ; 
        RECT 6.58 28.904 6.606 29.997 ; 
        RECT 6.472 28.904 6.498 29.997 ; 
        RECT 6.364 28.904 6.39 29.997 ; 
        RECT 6.256 28.904 6.282 29.997 ; 
        RECT 6.148 28.904 6.174 29.997 ; 
        RECT 6.04 28.904 6.066 29.997 ; 
        RECT 5.932 28.904 5.958 29.997 ; 
        RECT 5.824 28.904 5.85 29.997 ; 
        RECT 5.716 28.904 5.742 29.997 ; 
        RECT 5.608 28.904 5.634 29.997 ; 
        RECT 5.5 28.904 5.526 29.997 ; 
        RECT 5.392 28.904 5.418 29.997 ; 
        RECT 5.284 28.904 5.31 29.997 ; 
        RECT 5.176 28.904 5.202 29.997 ; 
        RECT 5.068 28.904 5.094 29.997 ; 
        RECT 4.96 28.904 4.986 29.997 ; 
        RECT 4.852 28.904 4.878 29.997 ; 
        RECT 4.744 28.904 4.77 29.997 ; 
        RECT 4.636 28.904 4.662 29.997 ; 
        RECT 4.528 28.904 4.554 29.997 ; 
        RECT 4.42 28.904 4.446 29.997 ; 
        RECT 4.312 28.904 4.338 29.997 ; 
        RECT 4.204 28.904 4.23 29.997 ; 
        RECT 4.096 28.904 4.122 29.997 ; 
        RECT 3.988 28.904 4.014 29.997 ; 
        RECT 3.88 28.904 3.906 29.997 ; 
        RECT 3.772 28.904 3.798 29.997 ; 
        RECT 3.664 28.904 3.69 29.997 ; 
        RECT 3.556 28.904 3.582 29.997 ; 
        RECT 3.448 28.904 3.474 29.997 ; 
        RECT 3.34 28.904 3.366 29.997 ; 
        RECT 3.232 28.904 3.258 29.997 ; 
        RECT 3.124 28.904 3.15 29.997 ; 
        RECT 3.016 28.904 3.042 29.997 ; 
        RECT 2.908 28.904 2.934 29.997 ; 
        RECT 2.8 28.904 2.826 29.997 ; 
        RECT 2.692 28.904 2.718 29.997 ; 
        RECT 2.584 28.904 2.61 29.997 ; 
        RECT 2.476 28.904 2.502 29.997 ; 
        RECT 2.368 28.904 2.394 29.997 ; 
        RECT 2.26 28.904 2.286 29.997 ; 
        RECT 2.152 28.904 2.178 29.997 ; 
        RECT 2.044 28.904 2.07 29.997 ; 
        RECT 1.936 28.904 1.962 29.997 ; 
        RECT 1.828 28.904 1.854 29.997 ; 
        RECT 1.72 28.904 1.746 29.997 ; 
        RECT 1.612 28.904 1.638 29.997 ; 
        RECT 1.504 28.904 1.53 29.997 ; 
        RECT 1.396 28.904 1.422 29.997 ; 
        RECT 1.288 28.904 1.314 29.997 ; 
        RECT 1.18 28.904 1.206 29.997 ; 
        RECT 1.072 28.904 1.098 29.997 ; 
        RECT 0.964 28.904 0.99 29.997 ; 
        RECT 0.856 28.904 0.882 29.997 ; 
        RECT 0.748 28.904 0.774 29.997 ; 
        RECT 0.64 28.904 0.666 29.997 ; 
        RECT 0.532 28.904 0.558 29.997 ; 
        RECT 0.424 28.904 0.45 29.997 ; 
        RECT 0.316 28.904 0.342 29.997 ; 
        RECT 0.208 28.904 0.234 29.997 ; 
        RECT 0.005 28.904 0.09 29.997 ; 
  LAYER V3 SPACING 0.072 ; 
      RECT 0.005 1.22 16.529 1.35 ; 
      RECT 16.412 0.257 16.529 1.35 ; 
      RECT 9.302 1.124 16.394 1.35 ; 
      RECT 7.97 1.124 9.284 1.35 ; 
      RECT 7.25 0.257 7.88 1.35 ; 
      RECT 0.14 1.124 7.232 1.35 ; 
      RECT 0.005 0.257 0.122 1.35 ; 
      RECT 16.376 0.257 16.529 1.172 ; 
      RECT 9.356 0.257 16.358 1.35 ; 
      RECT 8.609 0.257 9.338 1.172 ; 
      RECT 8.447 0.452 8.573 1.35 ; 
      RECT 7.196 0.356 8.42 1.172 ; 
      RECT 0.176 0.257 7.178 1.35 ; 
      RECT 0.005 0.257 0.158 1.172 ; 
      RECT 8.555 0.257 16.529 1.076 ; 
      RECT 0.005 0.356 8.537 1.076 ; 
      RECT 8.33 0.257 16.529 0.428 ; 
      RECT 0.005 0.257 8.312 1.076 ; 
      RECT 0.005 0.257 16.529 0.332 ; 
      RECT 0.005 2.3 16.529 2.43 ; 
      RECT 16.412 1.337 16.529 2.43 ; 
      RECT 9.302 2.204 16.394 2.43 ; 
      RECT 7.97 2.204 9.284 2.43 ; 
      RECT 7.25 1.337 7.88 2.43 ; 
      RECT 0.14 2.204 7.232 2.43 ; 
      RECT 0.005 1.337 0.122 2.43 ; 
      RECT 16.376 1.337 16.529 2.252 ; 
      RECT 9.356 1.337 16.358 2.43 ; 
      RECT 8.609 1.337 9.338 2.252 ; 
      RECT 8.447 1.532 8.573 2.43 ; 
      RECT 7.196 1.436 8.42 2.252 ; 
      RECT 0.176 1.337 7.178 2.43 ; 
      RECT 0.005 1.337 0.158 2.252 ; 
      RECT 8.555 1.337 16.529 2.156 ; 
      RECT 0.005 1.436 8.537 2.156 ; 
      RECT 8.33 1.337 16.529 1.508 ; 
      RECT 0.005 1.337 8.312 2.156 ; 
      RECT 0.005 1.337 16.529 1.412 ; 
      RECT 0.005 3.38 16.529 3.51 ; 
      RECT 16.412 2.417 16.529 3.51 ; 
      RECT 9.302 3.284 16.394 3.51 ; 
      RECT 7.97 3.284 9.284 3.51 ; 
      RECT 7.25 2.417 7.88 3.51 ; 
      RECT 0.14 3.284 7.232 3.51 ; 
      RECT 0.005 2.417 0.122 3.51 ; 
      RECT 16.376 2.417 16.529 3.332 ; 
      RECT 9.356 2.417 16.358 3.51 ; 
      RECT 8.609 2.417 9.338 3.332 ; 
      RECT 8.447 2.612 8.573 3.51 ; 
      RECT 7.196 2.516 8.42 3.332 ; 
      RECT 0.176 2.417 7.178 3.51 ; 
      RECT 0.005 2.417 0.158 3.332 ; 
      RECT 8.555 2.417 16.529 3.236 ; 
      RECT 0.005 2.516 8.537 3.236 ; 
      RECT 8.33 2.417 16.529 2.588 ; 
      RECT 0.005 2.417 8.312 3.236 ; 
      RECT 0.005 2.417 16.529 2.492 ; 
      RECT 0.005 4.46 16.529 4.59 ; 
      RECT 16.412 3.497 16.529 4.59 ; 
      RECT 9.302 4.364 16.394 4.59 ; 
      RECT 7.97 4.364 9.284 4.59 ; 
      RECT 7.25 3.497 7.88 4.59 ; 
      RECT 0.14 4.364 7.232 4.59 ; 
      RECT 0.005 3.497 0.122 4.59 ; 
      RECT 16.376 3.497 16.529 4.412 ; 
      RECT 9.356 3.497 16.358 4.59 ; 
      RECT 8.609 3.497 9.338 4.412 ; 
      RECT 8.447 3.692 8.573 4.59 ; 
      RECT 7.196 3.596 8.42 4.412 ; 
      RECT 0.176 3.497 7.178 4.59 ; 
      RECT 0.005 3.497 0.158 4.412 ; 
      RECT 8.555 3.497 16.529 4.316 ; 
      RECT 0.005 3.596 8.537 4.316 ; 
      RECT 8.33 3.497 16.529 3.668 ; 
      RECT 0.005 3.497 8.312 4.316 ; 
      RECT 0.005 3.497 16.529 3.572 ; 
      RECT 0.005 5.54 16.529 5.67 ; 
      RECT 16.412 4.577 16.529 5.67 ; 
      RECT 9.302 5.444 16.394 5.67 ; 
      RECT 7.97 5.444 9.284 5.67 ; 
      RECT 7.25 4.577 7.88 5.67 ; 
      RECT 0.14 5.444 7.232 5.67 ; 
      RECT 0.005 4.577 0.122 5.67 ; 
      RECT 16.376 4.577 16.529 5.492 ; 
      RECT 9.356 4.577 16.358 5.67 ; 
      RECT 8.609 4.577 9.338 5.492 ; 
      RECT 8.447 4.772 8.573 5.67 ; 
      RECT 7.196 4.676 8.42 5.492 ; 
      RECT 0.176 4.577 7.178 5.67 ; 
      RECT 0.005 4.577 0.158 5.492 ; 
      RECT 8.555 4.577 16.529 5.396 ; 
      RECT 0.005 4.676 8.537 5.396 ; 
      RECT 8.33 4.577 16.529 4.748 ; 
      RECT 0.005 4.577 8.312 5.396 ; 
      RECT 0.005 4.577 16.529 4.652 ; 
      RECT 0.005 6.62 16.529 6.75 ; 
      RECT 16.412 5.657 16.529 6.75 ; 
      RECT 9.302 6.524 16.394 6.75 ; 
      RECT 7.97 6.524 9.284 6.75 ; 
      RECT 7.25 5.657 7.88 6.75 ; 
      RECT 0.14 6.524 7.232 6.75 ; 
      RECT 0.005 5.657 0.122 6.75 ; 
      RECT 16.376 5.657 16.529 6.572 ; 
      RECT 9.356 5.657 16.358 6.75 ; 
      RECT 8.609 5.657 9.338 6.572 ; 
      RECT 8.447 5.852 8.573 6.75 ; 
      RECT 7.196 5.756 8.42 6.572 ; 
      RECT 0.176 5.657 7.178 6.75 ; 
      RECT 0.005 5.657 0.158 6.572 ; 
      RECT 8.555 5.657 16.529 6.476 ; 
      RECT 0.005 5.756 8.537 6.476 ; 
      RECT 8.33 5.657 16.529 5.828 ; 
      RECT 0.005 5.657 8.312 6.476 ; 
      RECT 0.005 5.657 16.529 5.732 ; 
      RECT 0.005 7.7 16.529 7.83 ; 
      RECT 16.412 6.737 16.529 7.83 ; 
      RECT 9.302 7.604 16.394 7.83 ; 
      RECT 7.97 7.604 9.284 7.83 ; 
      RECT 7.25 6.737 7.88 7.83 ; 
      RECT 0.14 7.604 7.232 7.83 ; 
      RECT 0.005 6.737 0.122 7.83 ; 
      RECT 16.376 6.737 16.529 7.652 ; 
      RECT 9.356 6.737 16.358 7.83 ; 
      RECT 8.609 6.737 9.338 7.652 ; 
      RECT 8.447 6.932 8.573 7.83 ; 
      RECT 7.196 6.836 8.42 7.652 ; 
      RECT 0.176 6.737 7.178 7.83 ; 
      RECT 0.005 6.737 0.158 7.652 ; 
      RECT 8.555 6.737 16.529 7.556 ; 
      RECT 0.005 6.836 8.537 7.556 ; 
      RECT 8.33 6.737 16.529 6.908 ; 
      RECT 0.005 6.737 8.312 7.556 ; 
      RECT 0.005 6.737 16.529 6.812 ; 
      RECT 0.005 8.78 16.529 8.91 ; 
      RECT 16.412 7.817 16.529 8.91 ; 
      RECT 9.302 8.684 16.394 8.91 ; 
      RECT 7.97 8.684 9.284 8.91 ; 
      RECT 7.25 7.817 7.88 8.91 ; 
      RECT 0.14 8.684 7.232 8.91 ; 
      RECT 0.005 7.817 0.122 8.91 ; 
      RECT 16.376 7.817 16.529 8.732 ; 
      RECT 9.356 7.817 16.358 8.91 ; 
      RECT 8.609 7.817 9.338 8.732 ; 
      RECT 8.447 8.012 8.573 8.91 ; 
      RECT 7.196 7.916 8.42 8.732 ; 
      RECT 0.176 7.817 7.178 8.91 ; 
      RECT 0.005 7.817 0.158 8.732 ; 
      RECT 8.555 7.817 16.529 8.636 ; 
      RECT 0.005 7.916 8.537 8.636 ; 
      RECT 8.33 7.817 16.529 7.988 ; 
      RECT 0.005 7.817 8.312 8.636 ; 
      RECT 0.005 7.817 16.529 7.892 ; 
      RECT 0.005 9.86 16.529 9.99 ; 
      RECT 16.412 8.897 16.529 9.99 ; 
      RECT 9.302 9.764 16.394 9.99 ; 
      RECT 7.97 9.764 9.284 9.99 ; 
      RECT 7.25 8.897 7.88 9.99 ; 
      RECT 0.14 9.764 7.232 9.99 ; 
      RECT 0.005 8.897 0.122 9.99 ; 
      RECT 16.376 8.897 16.529 9.812 ; 
      RECT 9.356 8.897 16.358 9.99 ; 
      RECT 8.609 8.897 9.338 9.812 ; 
      RECT 8.447 9.092 8.573 9.99 ; 
      RECT 7.196 8.996 8.42 9.812 ; 
      RECT 0.176 8.897 7.178 9.99 ; 
      RECT 0.005 8.897 0.158 9.812 ; 
      RECT 8.555 8.897 16.529 9.716 ; 
      RECT 0.005 8.996 8.537 9.716 ; 
      RECT 8.33 8.897 16.529 9.068 ; 
      RECT 0.005 8.897 8.312 9.716 ; 
      RECT 0.005 8.897 16.529 8.972 ; 
      RECT 0.005 10.94 16.529 11.07 ; 
      RECT 16.412 9.977 16.529 11.07 ; 
      RECT 9.302 10.844 16.394 11.07 ; 
      RECT 7.97 10.844 9.284 11.07 ; 
      RECT 7.25 9.977 7.88 11.07 ; 
      RECT 0.14 10.844 7.232 11.07 ; 
      RECT 0.005 9.977 0.122 11.07 ; 
      RECT 16.376 9.977 16.529 10.892 ; 
      RECT 9.356 9.977 16.358 11.07 ; 
      RECT 8.609 9.977 9.338 10.892 ; 
      RECT 8.447 10.172 8.573 11.07 ; 
      RECT 7.196 10.076 8.42 10.892 ; 
      RECT 0.176 9.977 7.178 11.07 ; 
      RECT 0.005 9.977 0.158 10.892 ; 
      RECT 8.555 9.977 16.529 10.796 ; 
      RECT 0.005 10.076 8.537 10.796 ; 
      RECT 8.33 9.977 16.529 10.148 ; 
      RECT 0.005 9.977 8.312 10.796 ; 
      RECT 0.005 9.977 16.529 10.052 ; 
      RECT 0 18.357 16.524 19.691 ; 
      RECT 10.809 11.037 16.524 19.691 ; 
      RECT 8.609 14.901 16.524 19.691 ; 
      RECT 9.513 12.309 16.524 19.691 ; 
      RECT 8.557 11.037 8.591 19.691 ; 
      RECT 8.505 11.037 8.539 19.691 ; 
      RECT 8.453 11.037 8.487 19.691 ; 
      RECT 8.401 11.037 8.435 19.691 ; 
      RECT 0 17.925 8.383 19.691 ; 
      RECT 8.141 15.189 16.524 18.141 ; 
      RECT 8.089 11.037 8.123 19.691 ; 
      RECT 8.037 11.037 8.071 19.691 ; 
      RECT 7.985 11.037 8.019 19.691 ; 
      RECT 7.933 11.037 7.967 19.691 ; 
      RECT 0 12.597 7.915 19.691 ; 
      RECT 0 14.757 8.383 17.709 ; 
      RECT 8.141 12.021 9.279 14.973 ; 
      RECT 9.315 12.501 16.524 19.691 ; 
      RECT 0 14.757 9.297 14.973 ; 
      RECT 8.141 12.501 16.524 14.877 ; 
      RECT 7.461 11.589 8.235 14.541 ; 
      RECT 7.245 11.733 7.915 19.691 ; 
      RECT 0 12.309 7.227 19.691 ; 
      RECT 6.813 11.037 7.263 12.573 ; 
      RECT 0 12.405 9.495 12.573 ; 
      RECT 9.297 12.309 16.524 12.477 ; 
      RECT 10.593 11.037 10.791 19.691 ; 
      RECT 6.813 12.117 10.575 12.381 ; 
      RECT 5.949 11.733 6.795 19.691 ; 
      RECT 0 11.037 5.931 19.691 ; 
      RECT 10.377 11.037 16.524 12.285 ; 
      RECT 10.161 11.733 16.524 12.285 ; 
      RECT 0 12.022 10.143 12.285 ; 
      RECT 9.945 11.037 10.359 12.093 ; 
      RECT 9.351 11.733 16.524 12.093 ; 
      RECT 8.609 11.733 9.333 12.381 ; 
      RECT 8.141 11.685 8.383 19.691 ; 
      RECT 8.253 11.037 8.631 11.805 ; 
      RECT 8.649 11.685 9.927 11.806 ; 
      RECT 6.597 11.685 7.443 12.285 ; 
      RECT 6.165 11.685 6.579 19.691 ; 
      RECT 0 11.037 6.147 12.285 ; 
      RECT 9.729 11.037 16.524 11.709 ; 
      RECT 8.253 11.117 9.711 11.709 ; 
      RECT 7.281 11.589 8.235 11.709 ; 
      RECT 6.381 11.037 7.263 11.709 ; 
      RECT 0 11.037 6.363 11.709 ; 
      RECT 9.297 11.037 16.524 11.661 ; 
      RECT 8.141 11.117 16.524 11.661 ; 
      RECT 0 11.037 7.915 11.661 ; 
      RECT 0 11.037 9.279 11.373 ; 
      RECT 0 11.037 16.524 11.093 ; 
        RECT 0.005 20.147 16.529 20.277 ; 
        RECT 16.412 19.184 16.529 20.277 ; 
        RECT 9.302 20.051 16.394 20.277 ; 
        RECT 7.97 20.051 9.284 20.277 ; 
        RECT 7.25 19.184 7.88 20.277 ; 
        RECT 0.14 20.051 7.232 20.277 ; 
        RECT 0.005 19.184 0.122 20.277 ; 
        RECT 16.376 19.184 16.529 20.099 ; 
        RECT 9.356 19.184 16.358 20.277 ; 
        RECT 8.609 19.184 9.338 20.099 ; 
        RECT 8.447 19.379 8.573 20.277 ; 
        RECT 7.196 19.283 8.42 20.099 ; 
        RECT 0.176 19.184 7.178 20.277 ; 
        RECT 0.005 19.184 0.158 20.099 ; 
        RECT 8.555 19.184 16.529 20.003 ; 
        RECT 0.005 19.283 8.537 20.003 ; 
        RECT 8.33 19.184 16.529 19.355 ; 
        RECT 0.005 19.184 8.312 20.003 ; 
        RECT 0.005 19.184 16.529 19.259 ; 
        RECT 0.005 21.227 16.529 21.357 ; 
        RECT 16.412 20.264 16.529 21.357 ; 
        RECT 9.302 21.131 16.394 21.357 ; 
        RECT 7.97 21.131 9.284 21.357 ; 
        RECT 7.25 20.264 7.88 21.357 ; 
        RECT 0.14 21.131 7.232 21.357 ; 
        RECT 0.005 20.264 0.122 21.357 ; 
        RECT 16.376 20.264 16.529 21.179 ; 
        RECT 9.356 20.264 16.358 21.357 ; 
        RECT 8.609 20.264 9.338 21.179 ; 
        RECT 8.447 20.459 8.573 21.357 ; 
        RECT 7.196 20.363 8.42 21.179 ; 
        RECT 0.176 20.264 7.178 21.357 ; 
        RECT 0.005 20.264 0.158 21.179 ; 
        RECT 8.555 20.264 16.529 21.083 ; 
        RECT 0.005 20.363 8.537 21.083 ; 
        RECT 8.33 20.264 16.529 20.435 ; 
        RECT 0.005 20.264 8.312 21.083 ; 
        RECT 0.005 20.264 16.529 20.339 ; 
        RECT 0.005 22.307 16.529 22.437 ; 
        RECT 16.412 21.344 16.529 22.437 ; 
        RECT 9.302 22.211 16.394 22.437 ; 
        RECT 7.97 22.211 9.284 22.437 ; 
        RECT 7.25 21.344 7.88 22.437 ; 
        RECT 0.14 22.211 7.232 22.437 ; 
        RECT 0.005 21.344 0.122 22.437 ; 
        RECT 16.376 21.344 16.529 22.259 ; 
        RECT 9.356 21.344 16.358 22.437 ; 
        RECT 8.609 21.344 9.338 22.259 ; 
        RECT 8.447 21.539 8.573 22.437 ; 
        RECT 7.196 21.443 8.42 22.259 ; 
        RECT 0.176 21.344 7.178 22.437 ; 
        RECT 0.005 21.344 0.158 22.259 ; 
        RECT 8.555 21.344 16.529 22.163 ; 
        RECT 0.005 21.443 8.537 22.163 ; 
        RECT 8.33 21.344 16.529 21.515 ; 
        RECT 0.005 21.344 8.312 22.163 ; 
        RECT 0.005 21.344 16.529 21.419 ; 
        RECT 0.005 23.387 16.529 23.517 ; 
        RECT 16.412 22.424 16.529 23.517 ; 
        RECT 9.302 23.291 16.394 23.517 ; 
        RECT 7.97 23.291 9.284 23.517 ; 
        RECT 7.25 22.424 7.88 23.517 ; 
        RECT 0.14 23.291 7.232 23.517 ; 
        RECT 0.005 22.424 0.122 23.517 ; 
        RECT 16.376 22.424 16.529 23.339 ; 
        RECT 9.356 22.424 16.358 23.517 ; 
        RECT 8.609 22.424 9.338 23.339 ; 
        RECT 8.447 22.619 8.573 23.517 ; 
        RECT 7.196 22.523 8.42 23.339 ; 
        RECT 0.176 22.424 7.178 23.517 ; 
        RECT 0.005 22.424 0.158 23.339 ; 
        RECT 8.555 22.424 16.529 23.243 ; 
        RECT 0.005 22.523 8.537 23.243 ; 
        RECT 8.33 22.424 16.529 22.595 ; 
        RECT 0.005 22.424 8.312 23.243 ; 
        RECT 0.005 22.424 16.529 22.499 ; 
        RECT 0.005 24.467 16.529 24.597 ; 
        RECT 16.412 23.504 16.529 24.597 ; 
        RECT 9.302 24.371 16.394 24.597 ; 
        RECT 7.97 24.371 9.284 24.597 ; 
        RECT 7.25 23.504 7.88 24.597 ; 
        RECT 0.14 24.371 7.232 24.597 ; 
        RECT 0.005 23.504 0.122 24.597 ; 
        RECT 16.376 23.504 16.529 24.419 ; 
        RECT 9.356 23.504 16.358 24.597 ; 
        RECT 8.609 23.504 9.338 24.419 ; 
        RECT 8.447 23.699 8.573 24.597 ; 
        RECT 7.196 23.603 8.42 24.419 ; 
        RECT 0.176 23.504 7.178 24.597 ; 
        RECT 0.005 23.504 0.158 24.419 ; 
        RECT 8.555 23.504 16.529 24.323 ; 
        RECT 0.005 23.603 8.537 24.323 ; 
        RECT 8.33 23.504 16.529 23.675 ; 
        RECT 0.005 23.504 8.312 24.323 ; 
        RECT 0.005 23.504 16.529 23.579 ; 
        RECT 0.005 25.547 16.529 25.677 ; 
        RECT 16.412 24.584 16.529 25.677 ; 
        RECT 9.302 25.451 16.394 25.677 ; 
        RECT 7.97 25.451 9.284 25.677 ; 
        RECT 7.25 24.584 7.88 25.677 ; 
        RECT 0.14 25.451 7.232 25.677 ; 
        RECT 0.005 24.584 0.122 25.677 ; 
        RECT 16.376 24.584 16.529 25.499 ; 
        RECT 9.356 24.584 16.358 25.677 ; 
        RECT 8.609 24.584 9.338 25.499 ; 
        RECT 8.447 24.779 8.573 25.677 ; 
        RECT 7.196 24.683 8.42 25.499 ; 
        RECT 0.176 24.584 7.178 25.677 ; 
        RECT 0.005 24.584 0.158 25.499 ; 
        RECT 8.555 24.584 16.529 25.403 ; 
        RECT 0.005 24.683 8.537 25.403 ; 
        RECT 8.33 24.584 16.529 24.755 ; 
        RECT 0.005 24.584 8.312 25.403 ; 
        RECT 0.005 24.584 16.529 24.659 ; 
        RECT 0.005 26.627 16.529 26.757 ; 
        RECT 16.412 25.664 16.529 26.757 ; 
        RECT 9.302 26.531 16.394 26.757 ; 
        RECT 7.97 26.531 9.284 26.757 ; 
        RECT 7.25 25.664 7.88 26.757 ; 
        RECT 0.14 26.531 7.232 26.757 ; 
        RECT 0.005 25.664 0.122 26.757 ; 
        RECT 16.376 25.664 16.529 26.579 ; 
        RECT 9.356 25.664 16.358 26.757 ; 
        RECT 8.609 25.664 9.338 26.579 ; 
        RECT 8.447 25.859 8.573 26.757 ; 
        RECT 7.196 25.763 8.42 26.579 ; 
        RECT 0.176 25.664 7.178 26.757 ; 
        RECT 0.005 25.664 0.158 26.579 ; 
        RECT 8.555 25.664 16.529 26.483 ; 
        RECT 0.005 25.763 8.537 26.483 ; 
        RECT 8.33 25.664 16.529 25.835 ; 
        RECT 0.005 25.664 8.312 26.483 ; 
        RECT 0.005 25.664 16.529 25.739 ; 
        RECT 0.005 27.707 16.529 27.837 ; 
        RECT 16.412 26.744 16.529 27.837 ; 
        RECT 9.302 27.611 16.394 27.837 ; 
        RECT 7.97 27.611 9.284 27.837 ; 
        RECT 7.25 26.744 7.88 27.837 ; 
        RECT 0.14 27.611 7.232 27.837 ; 
        RECT 0.005 26.744 0.122 27.837 ; 
        RECT 16.376 26.744 16.529 27.659 ; 
        RECT 9.356 26.744 16.358 27.837 ; 
        RECT 8.609 26.744 9.338 27.659 ; 
        RECT 8.447 26.939 8.573 27.837 ; 
        RECT 7.196 26.843 8.42 27.659 ; 
        RECT 0.176 26.744 7.178 27.837 ; 
        RECT 0.005 26.744 0.158 27.659 ; 
        RECT 8.555 26.744 16.529 27.563 ; 
        RECT 0.005 26.843 8.537 27.563 ; 
        RECT 8.33 26.744 16.529 26.915 ; 
        RECT 0.005 26.744 8.312 27.563 ; 
        RECT 0.005 26.744 16.529 26.819 ; 
        RECT 0.005 28.787 16.529 28.917 ; 
        RECT 16.412 27.824 16.529 28.917 ; 
        RECT 9.302 28.691 16.394 28.917 ; 
        RECT 7.97 28.691 9.284 28.917 ; 
        RECT 7.25 27.824 7.88 28.917 ; 
        RECT 0.14 28.691 7.232 28.917 ; 
        RECT 0.005 27.824 0.122 28.917 ; 
        RECT 16.376 27.824 16.529 28.739 ; 
        RECT 9.356 27.824 16.358 28.917 ; 
        RECT 8.609 27.824 9.338 28.739 ; 
        RECT 8.447 28.019 8.573 28.917 ; 
        RECT 7.196 27.923 8.42 28.739 ; 
        RECT 0.176 27.824 7.178 28.917 ; 
        RECT 0.005 27.824 0.158 28.739 ; 
        RECT 8.555 27.824 16.529 28.643 ; 
        RECT 0.005 27.923 8.537 28.643 ; 
        RECT 8.33 27.824 16.529 27.995 ; 
        RECT 0.005 27.824 8.312 28.643 ; 
        RECT 0.005 27.824 16.529 27.899 ; 
        RECT 0.005 29.867 16.529 29.997 ; 
        RECT 16.412 28.904 16.529 29.997 ; 
        RECT 9.302 29.771 16.394 29.997 ; 
        RECT 7.97 29.771 9.284 29.997 ; 
        RECT 7.25 28.904 7.88 29.997 ; 
        RECT 0.14 29.771 7.232 29.997 ; 
        RECT 0.005 28.904 0.122 29.997 ; 
        RECT 16.376 28.904 16.529 29.819 ; 
        RECT 9.356 28.904 16.358 29.997 ; 
        RECT 8.609 28.904 9.338 29.819 ; 
        RECT 8.447 29.099 8.573 29.997 ; 
        RECT 7.196 29.003 8.42 29.819 ; 
        RECT 0.176 28.904 7.178 29.997 ; 
        RECT 0.005 28.904 0.158 29.819 ; 
        RECT 8.555 28.904 16.529 29.723 ; 
        RECT 0.005 29.003 8.537 29.723 ; 
        RECT 8.33 28.904 16.529 29.075 ; 
        RECT 0.005 28.904 8.312 29.723 ; 
        RECT 0.005 28.904 16.529 28.979 ; 
  LAYER M4 ; 
      RECT 1.569 12.75 15.01 12.774 ; 
      RECT 1.569 13.038 15.01 13.062 ; 
      RECT 1.569 13.422 15.01 13.446 ; 
      RECT 1.569 13.518 15.01 13.542 ; 
      RECT 1.569 13.854 15.01 13.878 ; 
      RECT 1.569 14.238 15.01 14.262 ; 
      RECT 10.955 11.709 11.039 11.733 ; 
      RECT 10.767 12.141 10.897 12.165 ; 
      RECT 10.775 12.799 10.892 12.823 ; 
      RECT 10.775 13.086 10.892 13.11 ; 
      RECT 10.136 12.141 10.707 12.165 ; 
      RECT 10.196 12.918 10.304 12.942 ; 
      RECT 8.863 13.293 9.956 13.317 ; 
      RECT 9.551 12.861 9.635 12.885 ; 
      RECT 8.767 14.061 9.635 14.085 ; 
      RECT 9.551 14.157 9.635 14.181 ; 
      RECT 9.373 12.381 9.457 12.405 ; 
      RECT 9.335 13.725 9.419 13.749 ; 
      RECT 9.335 14.445 9.419 14.469 ; 
      RECT 9.157 12.285 9.241 12.309 ; 
      RECT 8.943 10.997 9.206 11.021 ; 
      RECT 8.943 19.621 9.206 19.645 ; 
      RECT 8.959 13.773 9.203 13.797 ; 
      RECT 9.119 13.917 9.203 13.941 ; 
      RECT 7.663 14.157 9.203 14.181 ; 
      RECT 9.119 14.445 9.203 14.469 ; 
      RECT 8.885 19.525 9.148 19.549 ; 
      RECT 8.884 10.901 9.147 10.925 ; 
      RECT 8.846 10.805 9.109 10.829 ; 
      RECT 8.846 19.333 9.109 19.357 ; 
      RECT 9.011 14.877 9.095 14.901 ; 
      RECT 8.239 15.261 9.095 15.285 ; 
      RECT 8.623 17.517 9.095 17.541 ; 
      RECT 9.011 17.613 9.095 17.637 ; 
      RECT 8.798 10.709 9.061 10.733 ; 
      RECT 8.798 19.237 9.061 19.261 ; 
      RECT 8.575 16.605 9.02 16.629 ; 
      RECT 8.754 10.613 9.017 10.637 ; 
      RECT 8.754 19.573 9.017 19.597 ; 
      RECT 8.705 10.949 8.968 10.973 ; 
      RECT 8.705 19.477 8.968 19.501 ; 
      RECT 8.836 13.917 8.957 13.941 ; 
      RECT 8.815 16.029 8.948 16.053 ; 
      RECT 8.658 10.853 8.921 10.877 ; 
      RECT 8.658 19.381 8.921 19.405 ; 
      RECT 8.623 10.565 8.886 10.589 ; 
      RECT 8.623 19.285 8.886 19.309 ; 
      RECT 7.807 17.613 8.876 17.637 ; 
      RECT 8.792 18.765 8.876 18.789 ; 
      RECT 8.567 10.421 8.83 10.445 ; 
      RECT 8.567 19.189 8.83 19.213 ; 
      RECT 8.719 14.877 8.804 14.901 ; 
      RECT 7.615 15.453 8.732 15.477 ; 
      RECT 8.26 13.293 8.717 13.317 ; 
      RECT 8.087 11.141 8.354 11.165 ; 
      RECT 8.087 19.045 8.354 19.069 ; 
      RECT 8.224 14.829 8.333 14.853 ; 
      RECT 8.064 11.045 8.306 11.069 ; 
      RECT 8.064 19.669 8.306 19.693 ; 
      RECT 8.008 10.565 8.25 10.589 ; 
      RECT 8.037 19.765 8.25 19.789 ; 
      RECT 8.153 14.445 8.237 14.469 ; 
      RECT 7.954 10.661 8.202 10.685 ; 
      RECT 7.954 19.621 8.202 19.645 ; 
      RECT 7.72 17.037 8.141 17.061 ; 
      RECT 7.688 10.997 7.955 11.021 ; 
      RECT 7.688 19.765 7.955 19.789 ; 
      RECT 7.828 15.597 7.949 15.621 ; 
      RECT 7.82 18.765 7.904 18.789 ; 
      RECT 7.654 10.901 7.901 10.925 ; 
      RECT 7.587 19.333 7.901 19.357 ; 
      RECT 7.628 10.805 7.858 10.829 ; 
      RECT 7.616 19.669 7.858 19.693 ; 
      RECT 7.575 10.709 7.805 10.733 ; 
      RECT 7.721 17.181 7.805 17.205 ; 
      RECT 7.525 19.237 7.805 19.261 ; 
      RECT 7.53 10.613 7.76 10.637 ; 
      RECT 7.53 19.573 7.76 19.597 ; 
      RECT 6.568 14.445 7.757 14.469 ; 
      RECT 7.492 10.853 7.722 10.877 ; 
      RECT 7.492 19.477 7.722 19.501 ; 
      RECT 7.474 10.757 7.667 10.781 ; 
      RECT 7.474 19.381 7.667 19.405 ; 
      RECT 7.425 10.661 7.618 10.685 ; 
      RECT 7.425 19.285 7.618 19.309 ; 
      RECT 7.429 15.357 7.613 15.381 ; 
      RECT 7.373 10.565 7.566 10.589 ; 
      RECT 7.373 19.189 7.566 19.213 ; 
      RECT 6.889 12.669 7.565 12.693 ; 
      RECT 7.429 15.453 7.513 15.477 ; 
      RECT 7.16 11.093 7.423 11.117 ; 
      RECT 7.193 14.877 7.326 14.901 ; 
      RECT 6.851 12.861 6.935 12.885 ; 
  LAYER V4 ; 
      RECT 11.004 11.709 11.028 11.733 ; 
      RECT 11.004 12.75 11.028 12.774 ; 
      RECT 10.836 12.141 10.86 12.165 ; 
      RECT 10.836 12.799 10.86 12.823 ; 
      RECT 10.836 13.086 10.86 13.11 ; 
      RECT 10.212 12.141 10.236 12.165 ; 
      RECT 10.212 12.918 10.236 12.942 ; 
      RECT 9.6 12.861 9.624 12.885 ; 
      RECT 9.6 13.038 9.624 13.062 ; 
      RECT 9.6 14.061 9.624 14.085 ; 
      RECT 9.6 14.157 9.624 14.181 ; 
      RECT 9.384 12.381 9.408 12.405 ; 
      RECT 9.384 13.422 9.408 13.446 ; 
      RECT 9.384 13.725 9.408 13.749 ; 
      RECT 9.384 13.854 9.408 13.878 ; 
      RECT 9.384 14.238 9.408 14.262 ; 
      RECT 9.384 14.445 9.408 14.469 ; 
      RECT 9.168 12.285 9.192 12.309 ; 
      RECT 9.168 13.518 9.192 13.542 ; 
      RECT 9.168 13.773 9.192 13.797 ; 
      RECT 9.168 13.917 9.192 13.941 ; 
      RECT 9.168 14.157 9.192 14.181 ; 
      RECT 9.168 14.445 9.192 14.469 ; 
      RECT 9.06 14.877 9.084 14.901 ; 
      RECT 9.06 15.261 9.084 15.285 ; 
      RECT 9.06 17.517 9.084 17.541 ; 
      RECT 9.06 17.613 9.084 17.637 ; 
      RECT 8.97 10.997 8.994 11.021 ; 
      RECT 8.97 13.773 8.994 13.797 ; 
      RECT 8.97 19.621 8.994 19.645 ; 
      RECT 8.922 10.901 8.946 10.925 ; 
      RECT 8.922 13.917 8.946 13.941 ; 
      RECT 8.922 19.525 8.946 19.549 ; 
      RECT 8.874 10.805 8.898 10.829 ; 
      RECT 8.874 13.293 8.898 13.317 ; 
      RECT 8.874 19.333 8.898 19.357 ; 
      RECT 8.826 10.709 8.85 10.733 ; 
      RECT 8.826 16.029 8.85 16.053 ; 
      RECT 8.826 18.765 8.85 18.789 ; 
      RECT 8.826 19.237 8.85 19.261 ; 
      RECT 8.778 10.613 8.802 10.637 ; 
      RECT 8.778 14.061 8.802 14.085 ; 
      RECT 8.778 19.573 8.802 19.597 ; 
      RECT 8.73 10.949 8.754 10.973 ; 
      RECT 8.73 14.877 8.754 14.901 ; 
      RECT 8.73 19.477 8.754 19.501 ; 
      RECT 8.682 10.853 8.706 10.877 ; 
      RECT 8.682 13.293 8.706 13.317 ; 
      RECT 8.682 19.381 8.706 19.405 ; 
      RECT 8.634 10.565 8.658 10.589 ; 
      RECT 8.634 17.517 8.658 17.541 ; 
      RECT 8.634 19.285 8.658 19.309 ; 
      RECT 8.586 10.421 8.61 10.445 ; 
      RECT 8.586 16.605 8.61 16.629 ; 
      RECT 8.586 19.189 8.61 19.213 ; 
      RECT 8.298 11.141 8.322 11.165 ; 
      RECT 8.298 14.829 8.322 14.853 ; 
      RECT 8.298 19.045 8.322 19.069 ; 
      RECT 8.25 11.045 8.274 11.069 ; 
      RECT 8.25 15.261 8.274 15.285 ; 
      RECT 8.25 19.669 8.274 19.693 ; 
      RECT 8.202 10.565 8.226 10.589 ; 
      RECT 8.202 14.445 8.226 14.469 ; 
      RECT 8.202 19.765 8.226 19.789 ; 
      RECT 8.106 10.661 8.13 10.685 ; 
      RECT 8.106 17.037 8.13 17.061 ; 
      RECT 8.106 19.621 8.13 19.645 ; 
      RECT 7.914 10.997 7.938 11.021 ; 
      RECT 7.914 15.597 7.938 15.621 ; 
      RECT 7.914 19.765 7.938 19.789 ; 
      RECT 7.866 10.901 7.89 10.925 ; 
      RECT 7.866 18.765 7.89 18.789 ; 
      RECT 7.866 19.333 7.89 19.357 ; 
      RECT 7.818 10.805 7.842 10.829 ; 
      RECT 7.818 17.613 7.842 17.637 ; 
      RECT 7.818 19.669 7.842 19.693 ; 
      RECT 7.77 10.709 7.794 10.733 ; 
      RECT 7.77 17.181 7.794 17.205 ; 
      RECT 7.77 19.237 7.794 19.261 ; 
      RECT 7.722 10.613 7.746 10.637 ; 
      RECT 7.722 14.445 7.746 14.469 ; 
      RECT 7.722 19.573 7.746 19.597 ; 
      RECT 7.674 10.853 7.698 10.877 ; 
      RECT 7.674 14.157 7.698 14.181 ; 
      RECT 7.674 19.477 7.698 19.501 ; 
      RECT 7.626 10.757 7.65 10.781 ; 
      RECT 7.626 15.453 7.65 15.477 ; 
      RECT 7.626 19.381 7.65 19.405 ; 
      RECT 7.578 10.661 7.602 10.685 ; 
      RECT 7.578 15.357 7.602 15.381 ; 
      RECT 7.578 19.285 7.602 19.309 ; 
      RECT 7.53 10.565 7.554 10.589 ; 
      RECT 7.53 12.669 7.554 12.693 ; 
      RECT 7.53 19.189 7.554 19.213 ; 
      RECT 7.44 15.357 7.464 15.381 ; 
      RECT 7.44 15.453 7.464 15.477 ; 
      RECT 7.272 11.093 7.296 11.117 ; 
      RECT 7.272 14.877 7.296 14.901 ; 
      RECT 6.9 12.669 6.924 12.693 ; 
      RECT 6.9 12.861 6.924 12.885 ; 
  LAYER M5 ; 
      RECT 11.004 11.698 11.028 12.785 ; 
      RECT 10.836 12.113 10.86 13.174 ; 
      RECT 10.212 12.122 10.236 12.954 ; 
      RECT 9.6 12.85 9.624 13.073 ; 
      RECT 9.6 14.05 9.624 14.192 ; 
      RECT 9.384 12.37 9.408 13.457 ; 
      RECT 9.384 13.714 9.408 13.889 ; 
      RECT 9.384 14.227 9.408 14.48 ; 
      RECT 9.168 12.274 9.192 13.553 ; 
      RECT 9.168 13.762 9.192 13.952 ; 
      RECT 9.168 14.146 9.192 14.48 ; 
      RECT 9.06 14.866 9.084 15.296 ; 
      RECT 9.06 17.506 9.084 17.648 ; 
      RECT 8.97 11.334 8.994 18.917 ; 
      RECT 8.922 11.334 8.946 18.917 ; 
      RECT 8.874 11.334 8.898 18.917 ; 
      RECT 8.826 11.334 8.85 18.917 ; 
      RECT 8.778 11.334 8.802 18.917 ; 
      RECT 8.73 11.334 8.754 18.917 ; 
      RECT 8.682 11.334 8.706 18.917 ; 
      RECT 8.634 11.334 8.658 18.917 ; 
      RECT 8.586 11.334 8.61 18.917 ; 
      RECT 8.298 11.334 8.322 18.917 ; 
      RECT 8.25 11.334 8.274 18.917 ; 
      RECT 8.202 11.334 8.226 18.917 ; 
      RECT 8.106 11.334 8.13 18.917 ; 
      RECT 7.914 11.334 7.938 18.917 ; 
      RECT 7.866 11.334 7.89 18.917 ; 
      RECT 7.818 11.334 7.842 18.917 ; 
      RECT 7.77 11.334 7.794 18.917 ; 
      RECT 7.722 11.334 7.746 18.917 ; 
      RECT 7.674 11.334 7.698 18.917 ; 
      RECT 7.626 10.492 7.65 19.547 ; 
      RECT 7.578 10.455 7.602 19.501 ; 
      RECT 7.53 10.401 7.554 19.447 ; 
      RECT 7.44 15.346 7.464 15.488 ; 
      RECT 7.272 11.075 7.296 14.919 ; 
      RECT 6.9 12.658 6.924 12.896 ; 
  LAYER M2 ; 
    RECT 0.108 0.036 15.892 30.204 ; 
  LAYER M1 ; 
    RECT 0.108 0.036 15.892 30.204 ; 
  END 
END srambank_128x4x20_6t122 
